VERSION 5.8 ;
BUSBITCHARS "[]" ;
DIVIDERCHAR "/" ;


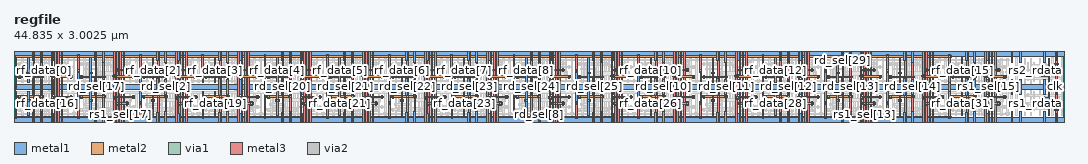
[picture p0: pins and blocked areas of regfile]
MACRO regfile
  CLASS BLOCK ;
  ORIGIN 0 0 ;
  FOREIGN regfile 0 0 ;
  SIZE 44.835 BY 3.0025 ;
  SYMMETRY X Y ;
  PIN vdd!
    DIRECTION INOUT ;
    USE POWER ;
    SHAPE ABUTMENT ;
    PORT
      LAYER metal1 ;
        RECT 0 0 44.835 0.2 ;
        RECT 44.5025 0 44.5675 0.36 ;
        RECT 43.97 0 44.035 0.45 ;
        RECT 42.95 0 43.015 0.45 ;
        RECT 42.58 0 42.645 0.45 ;
        RECT 41.5325 0 41.5975 0.3625 ;
        RECT 40.985 0 41.05 0.45 ;
        RECT 40.64 0 40.705 0.395 ;
        RECT 38.875 0 38.94 0.3625 ;
        RECT 38.3275 0 38.3925 0.45 ;
        RECT 37.9825 0 38.0475 0.395 ;
        RECT 36.2175 0 36.2825 0.3625 ;
        RECT 35.67 0 35.735 0.45 ;
        RECT 35.325 0 35.39 0.395 ;
        RECT 33.56 0 33.625 0.3625 ;
        RECT 33.0125 0 33.0775 0.45 ;
        RECT 32.6675 0 32.7325 0.395 ;
        RECT 30.9025 0 30.9675 0.3625 ;
        RECT 30.355 0 30.42 0.45 ;
        RECT 30.01 0 30.075 0.395 ;
        RECT 28.245 0 28.31 0.3625 ;
        RECT 27.6975 0 27.7625 0.45 ;
        RECT 27.3525 0 27.4175 0.395 ;
        RECT 25.5875 0 25.6525 0.3625 ;
        RECT 25.04 0 25.105 0.45 ;
        RECT 24.695 0 24.76 0.395 ;
        RECT 22.93 0 22.995 0.3625 ;
        RECT 22.3825 0 22.4475 0.45 ;
        RECT 22.0375 0 22.1025 0.395 ;
        RECT 20.2725 0 20.3375 0.3625 ;
        RECT 19.725 0 19.79 0.45 ;
        RECT 19.38 0 19.445 0.395 ;
        RECT 17.615 0 17.68 0.3625 ;
        RECT 17.0675 0 17.1325 0.45 ;
        RECT 16.7225 0 16.7875 0.395 ;
        RECT 14.9575 0 15.0225 0.3625 ;
        RECT 14.41 0 14.475 0.45 ;
        RECT 14.065 0 14.13 0.395 ;
        RECT 12.3 0 12.365 0.3625 ;
        RECT 11.7525 0 11.8175 0.45 ;
        RECT 11.4075 0 11.4725 0.395 ;
        RECT 9.6425 0 9.7075 0.3625 ;
        RECT 9.095 0 9.16 0.45 ;
        RECT 8.75 0 8.815 0.395 ;
        RECT 6.985 0 7.05 0.3625 ;
        RECT 6.4375 0 6.5025 0.45 ;
        RECT 6.0925 0 6.1575 0.395 ;
        RECT 4.3275 0 4.3925 0.3625 ;
        RECT 3.78 0 3.845 0.45 ;
        RECT 3.435 0 3.5 0.395 ;
        RECT 1.67 0 1.735 0.3625 ;
        RECT 1.1225 0 1.1875 0.45 ;
        RECT 0.7775 0 0.8425 0.395 ;
        RECT 0 2.8 44.835 3 ;
        RECT 44.5025 2.64 44.5675 3 ;
        RECT 43.97 2.55 44.035 3 ;
        RECT 42.95 2.55 43.015 3 ;
        RECT 42.58 2.55 42.645 3 ;
        RECT 41.5325 2.6375 41.5975 3 ;
        RECT 40.985 2.55 41.05 3 ;
        RECT 40.64 2.605 40.705 3 ;
        RECT 38.875 2.6375 38.94 3 ;
        RECT 38.3275 2.55 38.3925 3 ;
        RECT 37.9825 2.605 38.0475 3 ;
        RECT 36.2175 2.6375 36.2825 3 ;
        RECT 35.67 2.55 35.735 3 ;
        RECT 35.325 2.605 35.39 3 ;
        RECT 33.56 2.6375 33.625 3 ;
        RECT 33.0125 2.55 33.0775 3 ;
        RECT 32.6675 2.605 32.7325 3 ;
        RECT 30.9025 2.6375 30.9675 3 ;
        RECT 30.355 2.55 30.42 3 ;
        RECT 30.01 2.605 30.075 3 ;
        RECT 28.245 2.6375 28.31 3 ;
        RECT 27.6975 2.55 27.7625 3 ;
        RECT 27.3525 2.605 27.4175 3 ;
        RECT 25.5875 2.6375 25.6525 3 ;
        RECT 25.04 2.55 25.105 3 ;
        RECT 24.695 2.605 24.76 3 ;
        RECT 22.93 2.6375 22.995 3 ;
        RECT 22.3825 2.55 22.4475 3 ;
        RECT 22.0375 2.605 22.1025 3 ;
        RECT 20.2725 2.6375 20.3375 3 ;
        RECT 19.725 2.55 19.79 3 ;
        RECT 19.38 2.605 19.445 3 ;
        RECT 17.615 2.6375 17.68 3 ;
        RECT 17.0675 2.55 17.1325 3 ;
        RECT 16.7225 2.605 16.7875 3 ;
        RECT 14.9575 2.6375 15.0225 3 ;
        RECT 14.41 2.55 14.475 3 ;
        RECT 14.065 2.605 14.13 3 ;
        RECT 12.3 2.6375 12.365 3 ;
        RECT 11.7525 2.55 11.8175 3 ;
        RECT 11.4075 2.605 11.4725 3 ;
        RECT 9.6425 2.6375 9.7075 3 ;
        RECT 9.095 2.55 9.16 3 ;
        RECT 8.75 2.605 8.815 3 ;
        RECT 6.985 2.6375 7.05 3 ;
        RECT 6.4375 2.55 6.5025 3 ;
        RECT 6.0925 2.605 6.1575 3 ;
        RECT 4.3275 2.6375 4.3925 3 ;
        RECT 3.78 2.55 3.845 3 ;
        RECT 3.435 2.605 3.5 3 ;
        RECT 1.67 2.6375 1.735 3 ;
        RECT 1.1225 2.55 1.1875 3 ;
        RECT 0.7775 2.605 0.8425 3 ;
    END
  END vdd!
  PIN vss!
    DIRECTION INOUT ;
    USE GROUND ;
    SHAPE ABUTMENT ;
    PORT
      LAYER metal1 ;
        RECT 0 1.4 44.835 1.6 ;
        RECT 44.5025 1.1875 44.5675 1.8125 ;
        RECT 43.9725 1.185 44.0375 1.815 ;
        RECT 42.95 1.185 43.015 1.815 ;
        RECT 42.58 1.185 42.645 1.815 ;
        RECT 41.53 1.19 41.595 1.81 ;
        RECT 40.985 1.1875 41.05 1.8125 ;
        RECT 40.64 1.1425 40.705 1.8575 ;
        RECT 38.8725 1.19 38.9375 1.81 ;
        RECT 38.3275 1.1875 38.3925 1.8125 ;
        RECT 37.9825 1.1425 38.0475 1.8575 ;
        RECT 36.215 1.19 36.28 1.81 ;
        RECT 35.67 1.1875 35.735 1.8125 ;
        RECT 35.325 1.1425 35.39 1.8575 ;
        RECT 33.5575 1.19 33.6225 1.81 ;
        RECT 33.0125 1.1875 33.0775 1.8125 ;
        RECT 32.6675 1.1425 32.7325 1.8575 ;
        RECT 30.9 1.19 30.965 1.81 ;
        RECT 30.355 1.1875 30.42 1.8125 ;
        RECT 30.01 1.1425 30.075 1.8575 ;
        RECT 28.2425 1.19 28.3075 1.81 ;
        RECT 27.6975 1.1875 27.7625 1.8125 ;
        RECT 27.3525 1.1425 27.4175 1.8575 ;
        RECT 25.585 1.19 25.65 1.81 ;
        RECT 25.04 1.1875 25.105 1.8125 ;
        RECT 24.695 1.1425 24.76 1.8575 ;
        RECT 22.9275 1.19 22.9925 1.81 ;
        RECT 22.3825 1.1875 22.4475 1.8125 ;
        RECT 22.0375 1.1425 22.1025 1.8575 ;
        RECT 20.27 1.19 20.335 1.81 ;
        RECT 19.725 1.1875 19.79 1.8125 ;
        RECT 19.38 1.1425 19.445 1.8575 ;
        RECT 17.6125 1.19 17.6775 1.81 ;
        RECT 17.0675 1.1875 17.1325 1.8125 ;
        RECT 16.7225 1.1425 16.7875 1.8575 ;
        RECT 14.955 1.19 15.02 1.81 ;
        RECT 14.41 1.1875 14.475 1.8125 ;
        RECT 14.065 1.1425 14.13 1.8575 ;
        RECT 12.2975 1.19 12.3625 1.81 ;
        RECT 11.7525 1.1875 11.8175 1.8125 ;
        RECT 11.4075 1.1425 11.4725 1.8575 ;
        RECT 9.64 1.19 9.705 1.81 ;
        RECT 9.095 1.1875 9.16 1.8125 ;
        RECT 8.75 1.1425 8.815 1.8575 ;
        RECT 6.9825 1.19 7.0475 1.81 ;
        RECT 6.4375 1.1875 6.5025 1.8125 ;
        RECT 6.0925 1.1425 6.1575 1.8575 ;
        RECT 4.325 1.19 4.39 1.81 ;
        RECT 3.78 1.1875 3.845 1.8125 ;
        RECT 3.435 1.1425 3.5 1.8575 ;
        RECT 1.6675 1.19 1.7325 1.81 ;
        RECT 1.1225 1.1875 1.1875 1.8125 ;
        RECT 0.7775 1.1425 0.8425 1.8575 ;
        RECT 0.06 1.4 0.125 2.735 ;
        RECT 0.0575 2.1225 0.125 2.2575 ;
      LAYER metal2 ;
        RECT 0.055 2.1225 0.125 2.2575 ;
      LAYER via1 ;
        RECT 0.0575 2.1575 0.1225 2.2225 ;
    END
  END vss!
  PIN clk
    DIRECTION INPUT ;
    USE SIGNAL ;
    PORT
      LAYER metal1 ;
        RECT 44.445 0.49 44.58 0.555 ;
        RECT 44.445 2.445 44.58 2.51 ;
      LAYER metal3 ;
        RECT 44.4775 0 44.5475 3.0025 ;
      LAYER metal2 ;
        RECT 44.4425 0.49 44.5825 0.56 ;
        RECT 44.445 0.4875 44.58 0.56 ;
        RECT 44.4425 2.4425 44.5825 2.5125 ;
      LAYER via1 ;
        RECT 44.48 2.445 44.545 2.51 ;
        RECT 44.48 0.49 44.545 0.555 ;
      LAYER via2 ;
        RECT 44.4775 2.4425 44.5475 2.5125 ;
        RECT 44.4775 0.49 44.5475 0.56 ;
    END
  END clk
  PIN rd_mux_out
    DIRECTION INPUT ;
    USE SIGNAL ;
    PORT
      LAYER metal1 ;
        RECT 39.9225 0.265 39.9875 1.3125 ;
        RECT 39.92 0.7425 39.9875 0.8775 ;
        RECT 39.9225 1.6875 39.9875 2.735 ;
        RECT 39.92 2.1225 39.9875 2.2575 ;
        RECT 37.265 0.265 37.33 1.3125 ;
        RECT 37.2625 0.7425 37.33 0.8775 ;
        RECT 37.265 1.6875 37.33 2.735 ;
        RECT 37.2625 2.1225 37.33 2.2575 ;
        RECT 34.6075 0.265 34.6725 1.3125 ;
        RECT 34.605 0.7425 34.6725 0.8775 ;
        RECT 34.6075 1.6875 34.6725 2.735 ;
        RECT 34.605 2.1225 34.6725 2.2575 ;
        RECT 31.95 0.265 32.015 1.3125 ;
        RECT 31.9475 0.7425 32.015 0.8775 ;
        RECT 31.95 1.6875 32.015 2.735 ;
        RECT 31.9475 2.1225 32.015 2.2575 ;
        RECT 29.2925 0.265 29.3575 1.3125 ;
        RECT 29.29 0.7425 29.3575 0.8775 ;
        RECT 29.2925 1.6875 29.3575 2.735 ;
        RECT 29.29 2.1225 29.3575 2.2575 ;
        RECT 26.635 0.265 26.7 1.3125 ;
        RECT 26.6325 0.7425 26.7 0.8775 ;
        RECT 26.635 1.6875 26.7 2.735 ;
        RECT 26.6325 2.1225 26.7 2.2575 ;
        RECT 23.9775 0.265 24.0425 1.3125 ;
        RECT 23.975 0.7425 24.0425 0.8775 ;
        RECT 23.9775 1.6875 24.0425 2.735 ;
        RECT 23.975 2.1225 24.0425 2.2575 ;
        RECT 21.32 0.265 21.385 1.3125 ;
        RECT 21.3175 0.7425 21.385 0.8775 ;
        RECT 21.32 1.6875 21.385 2.735 ;
        RECT 21.3175 2.1225 21.385 2.2575 ;
        RECT 18.6625 0.265 18.7275 1.3125 ;
        RECT 18.66 0.7425 18.7275 0.8775 ;
        RECT 18.6625 1.6875 18.7275 2.735 ;
        RECT 18.66 2.1225 18.7275 2.2575 ;
        RECT 16.005 0.265 16.07 1.3125 ;
        RECT 16.0025 0.7425 16.07 0.8775 ;
        RECT 16.005 1.6875 16.07 2.735 ;
        RECT 16.0025 2.1225 16.07 2.2575 ;
        RECT 13.3475 0.265 13.4125 1.3125 ;
        RECT 13.345 0.7425 13.4125 0.8775 ;
        RECT 13.3475 1.6875 13.4125 2.735 ;
        RECT 13.345 2.1225 13.4125 2.2575 ;
        RECT 10.69 0.265 10.755 1.3125 ;
        RECT 10.6875 0.7425 10.755 0.8775 ;
        RECT 10.69 1.6875 10.755 2.735 ;
        RECT 10.6875 2.1225 10.755 2.2575 ;
        RECT 8.0325 0.265 8.0975 1.3125 ;
        RECT 8.03 0.7425 8.0975 0.8775 ;
        RECT 8.0325 1.6875 8.0975 2.735 ;
        RECT 8.03 2.1225 8.0975 2.2575 ;
        RECT 5.375 0.265 5.44 1.3125 ;
        RECT 5.3725 0.7425 5.44 0.8775 ;
        RECT 5.375 1.6875 5.44 2.735 ;
        RECT 5.3725 2.1225 5.44 2.2575 ;
        RECT 2.7175 0.265 2.7825 1.3125 ;
        RECT 2.715 0.7425 2.7825 0.8775 ;
        RECT 2.7175 1.6875 2.7825 2.735 ;
        RECT 2.715 2.1225 2.7825 2.2575 ;
        RECT 0.06 0.265 0.125 1.3125 ;
        RECT 0.0575 0.7425 0.125 0.8775 ;
      LAYER metal3 ;
        RECT 39.92 0.1375 39.99 0.8775 ;
        RECT 39.9175 0.7375 39.9875 2.8625 ;
        RECT 37.26 0.7375 37.3325 0.8775 ;
        RECT 37.2625 0.1375 37.3325 0.8775 ;
        RECT 37.26 2.1225 37.33 2.8625 ;
        RECT 34.6025 0.7375 34.675 0.8775 ;
        RECT 34.605 0.1375 34.675 0.8775 ;
        RECT 34.6025 2.1225 34.6725 2.8625 ;
        RECT 31.945 0.7375 32.0175 0.8775 ;
        RECT 31.9475 0.1375 32.0175 0.8775 ;
        RECT 31.945 2.1225 32.015 2.8625 ;
        RECT 29.2875 0.7375 29.36 0.8775 ;
        RECT 29.29 0.1375 29.36 0.8775 ;
        RECT 29.2875 2.1225 29.3575 2.8625 ;
        RECT 26.63 0.7375 26.7025 0.8775 ;
        RECT 26.6325 0.1375 26.7025 0.8775 ;
        RECT 26.63 2.1225 26.7 2.8625 ;
        RECT 23.9725 0.7375 24.045 0.8775 ;
        RECT 23.975 0.1375 24.045 0.8775 ;
        RECT 23.9725 2.1225 24.0425 2.8625 ;
        RECT 21.315 0.7375 21.3875 0.8775 ;
        RECT 21.3175 0.1375 21.3875 0.8775 ;
        RECT 21.315 2.1225 21.385 2.8625 ;
        RECT 18.6575 0.7375 18.73 0.8775 ;
        RECT 18.66 0.1375 18.73 0.8775 ;
        RECT 18.6575 2.1225 18.7275 2.8625 ;
        RECT 16 0.7375 16.0725 0.8775 ;
        RECT 16.0025 0.1375 16.0725 0.8775 ;
        RECT 16 2.1225 16.07 2.8625 ;
        RECT 13.3425 0.7375 13.415 0.8775 ;
        RECT 13.345 0.1375 13.415 0.8775 ;
        RECT 13.3425 2.1225 13.4125 2.8625 ;
        RECT 10.685 0.7375 10.7575 0.8775 ;
        RECT 10.6875 0.1375 10.7575 0.8775 ;
        RECT 10.685 2.1225 10.755 2.8625 ;
        RECT 8.0275 0.7375 8.1 0.8775 ;
        RECT 8.03 0.1375 8.1 0.8775 ;
        RECT 8.0275 2.1225 8.0975 2.8625 ;
        RECT 5.37 0.7375 5.4425 0.8775 ;
        RECT 5.3725 0.1375 5.4425 0.8775 ;
        RECT 5.37 2.1225 5.44 2.8625 ;
        RECT 2.7125 0.7375 2.785 0.8775 ;
        RECT 2.715 0.1375 2.785 0.8775 ;
        RECT 2.7125 2.1225 2.7825 2.8625 ;
        RECT 0.055 0.7375 0.1275 0.8775 ;
        RECT 0.0575 0.1375 0.1275 0.8775 ;
      LAYER metal2 ;
        RECT 0.0225 0.1725 40.025 0.2425 ;
        RECT 0.0725 2.7575 40.0225 2.8275 ;
        RECT 39.9175 0.7375 39.9875 0.8775 ;
        RECT 39.9175 2.1225 39.9875 2.2625 ;
        RECT 37.26 0.7375 37.33 0.8775 ;
        RECT 37.26 2.1225 37.33 2.2625 ;
        RECT 34.6025 0.7375 34.6725 0.8775 ;
        RECT 34.6025 2.1225 34.6725 2.2625 ;
        RECT 31.945 0.7375 32.015 0.8775 ;
        RECT 31.945 2.1225 32.015 2.2625 ;
        RECT 29.2875 0.7375 29.3575 0.8775 ;
        RECT 29.2875 2.1225 29.3575 2.2625 ;
        RECT 26.63 0.7375 26.7 0.8775 ;
        RECT 26.63 2.1225 26.7 2.2625 ;
        RECT 23.9725 0.7375 24.0425 0.8775 ;
        RECT 23.9725 2.1225 24.0425 2.2625 ;
        RECT 21.315 0.7375 21.385 0.8775 ;
        RECT 21.315 2.1225 21.385 2.2625 ;
        RECT 18.6575 0.7375 18.7275 0.8775 ;
        RECT 18.6575 2.1225 18.7275 2.2625 ;
        RECT 16 0.7375 16.07 0.8775 ;
        RECT 16 2.1225 16.07 2.2625 ;
        RECT 13.3425 0.7375 13.4125 0.8775 ;
        RECT 13.3425 2.1225 13.4125 2.2625 ;
        RECT 10.685 0.7375 10.755 0.8775 ;
        RECT 10.685 2.1225 10.755 2.2625 ;
        RECT 8.0275 0.7375 8.0975 0.8775 ;
        RECT 8.0275 2.1225 8.0975 2.2625 ;
        RECT 5.37 0.7375 5.44 0.8775 ;
        RECT 5.37 2.1225 5.44 2.2625 ;
        RECT 2.7125 0.7375 2.7825 0.8775 ;
        RECT 2.7125 2.1225 2.7825 2.2625 ;
        RECT 0.055 0.7375 0.125 0.8775 ;
      LAYER via1 ;
        RECT 0.0575 0.7775 0.1225 0.8425 ;
        RECT 2.715 2.1575 2.78 2.2225 ;
        RECT 2.715 0.7775 2.78 0.8425 ;
        RECT 5.3725 2.1575 5.4375 2.2225 ;
        RECT 5.3725 0.7775 5.4375 0.8425 ;
        RECT 8.03 2.1575 8.095 2.2225 ;
        RECT 8.03 0.7775 8.095 0.8425 ;
        RECT 10.6875 2.1575 10.7525 2.2225 ;
        RECT 10.6875 0.7775 10.7525 0.8425 ;
        RECT 13.345 2.1575 13.41 2.2225 ;
        RECT 13.345 0.7775 13.41 0.8425 ;
        RECT 16.0025 2.1575 16.0675 2.2225 ;
        RECT 16.0025 0.7775 16.0675 0.8425 ;
        RECT 18.66 2.1575 18.725 2.2225 ;
        RECT 18.66 0.7775 18.725 0.8425 ;
        RECT 21.3175 2.1575 21.3825 2.2225 ;
        RECT 21.3175 0.7775 21.3825 0.8425 ;
        RECT 23.975 2.1575 24.04 2.2225 ;
        RECT 23.975 0.7775 24.04 0.8425 ;
        RECT 26.6325 2.1575 26.6975 2.2225 ;
        RECT 26.6325 0.7775 26.6975 0.8425 ;
        RECT 29.29 2.1575 29.355 2.2225 ;
        RECT 29.29 0.7775 29.355 0.8425 ;
        RECT 31.9475 2.1575 32.0125 2.2225 ;
        RECT 31.9475 0.7775 32.0125 0.8425 ;
        RECT 34.605 2.1575 34.67 2.2225 ;
        RECT 34.605 0.7775 34.67 0.8425 ;
        RECT 37.2625 2.1575 37.3275 2.2225 ;
        RECT 37.2625 0.7775 37.3275 0.8425 ;
        RECT 39.92 2.1575 39.985 2.2225 ;
        RECT 39.92 0.7775 39.985 0.8425 ;
      LAYER via2 ;
        RECT 0.055 0.7725 0.125 0.8425 ;
        RECT 0.0575 0.1725 0.1275 0.2425 ;
        RECT 2.7125 2.7575 2.7825 2.8275 ;
        RECT 2.7125 2.1575 2.7825 2.2275 ;
        RECT 2.7125 0.7725 2.7825 0.8425 ;
        RECT 2.715 0.1725 2.785 0.2425 ;
        RECT 5.37 2.7575 5.44 2.8275 ;
        RECT 5.37 2.1575 5.44 2.2275 ;
        RECT 5.37 0.7725 5.44 0.8425 ;
        RECT 5.3725 0.1725 5.4425 0.2425 ;
        RECT 8.0275 2.7575 8.0975 2.8275 ;
        RECT 8.0275 2.1575 8.0975 2.2275 ;
        RECT 8.0275 0.7725 8.0975 0.8425 ;
        RECT 8.03 0.1725 8.1 0.2425 ;
        RECT 10.685 2.7575 10.755 2.8275 ;
        RECT 10.685 2.1575 10.755 2.2275 ;
        RECT 10.685 0.7725 10.755 0.8425 ;
        RECT 10.6875 0.1725 10.7575 0.2425 ;
        RECT 13.3425 2.7575 13.4125 2.8275 ;
        RECT 13.3425 2.1575 13.4125 2.2275 ;
        RECT 13.3425 0.7725 13.4125 0.8425 ;
        RECT 13.345 0.1725 13.415 0.2425 ;
        RECT 16 2.7575 16.07 2.8275 ;
        RECT 16 2.1575 16.07 2.2275 ;
        RECT 16 0.7725 16.07 0.8425 ;
        RECT 16.0025 0.1725 16.0725 0.2425 ;
        RECT 18.6575 2.7575 18.7275 2.8275 ;
        RECT 18.6575 2.1575 18.7275 2.2275 ;
        RECT 18.6575 0.7725 18.7275 0.8425 ;
        RECT 18.66 0.1725 18.73 0.2425 ;
        RECT 21.315 2.7575 21.385 2.8275 ;
        RECT 21.315 2.1575 21.385 2.2275 ;
        RECT 21.315 0.7725 21.385 0.8425 ;
        RECT 21.3175 0.1725 21.3875 0.2425 ;
        RECT 23.9725 2.7575 24.0425 2.8275 ;
        RECT 23.9725 2.1575 24.0425 2.2275 ;
        RECT 23.9725 0.7725 24.0425 0.8425 ;
        RECT 23.975 0.1725 24.045 0.2425 ;
        RECT 26.63 2.7575 26.7 2.8275 ;
        RECT 26.63 2.1575 26.7 2.2275 ;
        RECT 26.63 0.7725 26.7 0.8425 ;
        RECT 26.6325 0.1725 26.7025 0.2425 ;
        RECT 29.2875 2.7575 29.3575 2.8275 ;
        RECT 29.2875 2.1575 29.3575 2.2275 ;
        RECT 29.2875 0.7725 29.3575 0.8425 ;
        RECT 29.29 0.1725 29.36 0.2425 ;
        RECT 31.945 2.7575 32.015 2.8275 ;
        RECT 31.945 2.1575 32.015 2.2275 ;
        RECT 31.945 0.7725 32.015 0.8425 ;
        RECT 31.9475 0.1725 32.0175 0.2425 ;
        RECT 34.6025 2.7575 34.6725 2.8275 ;
        RECT 34.6025 2.1575 34.6725 2.2275 ;
        RECT 34.6025 0.7725 34.6725 0.8425 ;
        RECT 34.605 0.1725 34.675 0.2425 ;
        RECT 37.26 2.7575 37.33 2.8275 ;
        RECT 37.26 2.1575 37.33 2.2275 ;
        RECT 37.26 0.7725 37.33 0.8425 ;
        RECT 37.2625 0.1725 37.3325 0.2425 ;
        RECT 39.9175 2.7575 39.9875 2.8275 ;
        RECT 39.9175 2.1575 39.9875 2.2275 ;
        RECT 39.9175 0.7725 39.9875 0.8425 ;
        RECT 39.92 0.1725 39.99 0.2425 ;
    END
  END rd_mux_out
  PIN rd_sel[0]
    DIRECTION INPUT ;
    USE SIGNAL ;
    PORT
      LAYER metal1 ;
        RECT 1.105 1.885 1.24 1.95 ;
        RECT 0.1975 1.85 0.2625 1.985 ;
      LAYER metal3 ;
        RECT 1.135 0 1.205 3.0025 ;
      LAYER metal2 ;
        RECT 1.1 1.8825 1.24 1.955 ;
        RECT 0.1625 1.8825 1.24 1.9525 ;
      LAYER via1 ;
        RECT 0.1975 1.885 0.2625 1.95 ;
        RECT 1.14 1.885 1.205 1.95 ;
      LAYER via2 ;
        RECT 1.135 1.885 1.205 1.955 ;
    END
  END rd_sel[0]
  PIN rd_sel[10]
    DIRECTION INPUT ;
    USE SIGNAL ;
    PORT
      LAYER metal1 ;
        RECT 27.68 1.885 27.815 1.95 ;
        RECT 26.7725 1.85 26.8375 1.985 ;
      LAYER metal3 ;
        RECT 27.71 0 27.78 3.0025 ;
      LAYER metal2 ;
        RECT 27.675 1.8825 27.815 1.955 ;
        RECT 26.7375 1.8825 27.815 1.9525 ;
      LAYER via1 ;
        RECT 26.7725 1.885 26.8375 1.95 ;
        RECT 27.715 1.885 27.78 1.95 ;
      LAYER via2 ;
        RECT 27.71 1.885 27.78 1.955 ;
    END
  END rd_sel[10]
  PIN rd_sel[11]
    DIRECTION INPUT ;
    USE SIGNAL ;
    PORT
      LAYER metal1 ;
        RECT 30.3375 1.885 30.4725 1.95 ;
        RECT 29.43 1.85 29.495 1.985 ;
      LAYER metal3 ;
        RECT 30.3675 0 30.4375 3.0025 ;
      LAYER metal2 ;
        RECT 30.3325 1.8825 30.4725 1.955 ;
        RECT 29.395 1.8825 30.4725 1.9525 ;
      LAYER via1 ;
        RECT 29.43 1.885 29.495 1.95 ;
        RECT 30.3725 1.885 30.4375 1.95 ;
      LAYER via2 ;
        RECT 30.3675 1.885 30.4375 1.955 ;
    END
  END rd_sel[11]
  PIN rd_sel[12]
    DIRECTION INPUT ;
    USE SIGNAL ;
    PORT
      LAYER metal1 ;
        RECT 32.995 1.885 33.13 1.95 ;
        RECT 32.0875 1.85 32.1525 1.985 ;
      LAYER metal3 ;
        RECT 33.025 0 33.095 3.0025 ;
      LAYER metal2 ;
        RECT 32.99 1.8825 33.13 1.955 ;
        RECT 32.0525 1.8825 33.13 1.9525 ;
      LAYER via1 ;
        RECT 32.0875 1.885 32.1525 1.95 ;
        RECT 33.03 1.885 33.095 1.95 ;
      LAYER via2 ;
        RECT 33.025 1.885 33.095 1.955 ;
    END
  END rd_sel[12]
  PIN rd_sel[13]
    DIRECTION INPUT ;
    USE SIGNAL ;
    PORT
      LAYER metal1 ;
        RECT 35.6525 1.885 35.7875 1.95 ;
        RECT 34.745 1.85 34.81 1.985 ;
      LAYER metal3 ;
        RECT 35.6825 0 35.7525 3.0025 ;
      LAYER metal2 ;
        RECT 35.6475 1.8825 35.7875 1.955 ;
        RECT 34.71 1.8825 35.7875 1.9525 ;
      LAYER via1 ;
        RECT 34.745 1.885 34.81 1.95 ;
        RECT 35.6875 1.885 35.7525 1.95 ;
      LAYER via2 ;
        RECT 35.6825 1.885 35.7525 1.955 ;
    END
  END rd_sel[13]
  PIN rd_sel[14]
    DIRECTION INPUT ;
    USE SIGNAL ;
    PORT
      LAYER metal1 ;
        RECT 38.31 1.885 38.445 1.95 ;
        RECT 37.4025 1.85 37.4675 1.985 ;
      LAYER metal3 ;
        RECT 38.34 0 38.41 3.0025 ;
      LAYER metal2 ;
        RECT 38.305 1.8825 38.445 1.955 ;
        RECT 37.3675 1.8825 38.445 1.9525 ;
      LAYER via1 ;
        RECT 37.4025 1.885 37.4675 1.95 ;
        RECT 38.345 1.885 38.41 1.95 ;
      LAYER via2 ;
        RECT 38.34 1.885 38.41 1.955 ;
    END
  END rd_sel[14]
  PIN rd_sel[15]
    DIRECTION INPUT ;
    USE SIGNAL ;
    PORT
      LAYER metal1 ;
        RECT 40.9675 1.885 41.1025 1.95 ;
        RECT 40.06 1.85 40.125 1.985 ;
      LAYER metal3 ;
        RECT 40.9975 0 41.0675 3.0025 ;
      LAYER metal2 ;
        RECT 40.9625 1.8825 41.1025 1.955 ;
        RECT 40.025 1.8825 41.1025 1.9525 ;
      LAYER via1 ;
        RECT 40.06 1.885 40.125 1.95 ;
        RECT 41.0025 1.885 41.0675 1.95 ;
      LAYER via2 ;
        RECT 40.9975 1.885 41.0675 1.955 ;
    END
  END rd_sel[15]
  PIN rd_sel[16]
    DIRECTION INPUT ;
    USE SIGNAL ;
    PORT
      LAYER metal1 ;
        RECT 1.105 1.05 1.24 1.115 ;
        RECT 0.1975 1.015 0.2625 1.15 ;
      LAYER metal3 ;
        RECT 0.815 0 0.885 3.0025 ;
      LAYER metal2 ;
        RECT 0.1625 1.0475 1.24 1.1175 ;
      LAYER via1 ;
        RECT 0.1975 1.05 0.2625 1.115 ;
        RECT 1.14 1.05 1.205 1.115 ;
      LAYER via2 ;
        RECT 0.815 1.0475 0.885 1.1175 ;
    END
  END rd_sel[16]
  PIN rd_sel[17]
    DIRECTION INPUT ;
    USE SIGNAL ;
    PORT
      LAYER metal1 ;
        RECT 3.7625 1.05 3.8975 1.115 ;
        RECT 2.855 1.015 2.92 1.15 ;
      LAYER metal3 ;
        RECT 3.4725 0 3.5425 3.0025 ;
      LAYER metal2 ;
        RECT 2.82 1.0475 3.8975 1.1175 ;
      LAYER via1 ;
        RECT 2.855 1.05 2.92 1.115 ;
        RECT 3.7975 1.05 3.8625 1.115 ;
      LAYER via2 ;
        RECT 3.4725 1.0475 3.5425 1.1175 ;
    END
  END rd_sel[17]
  PIN rd_sel[18]
    DIRECTION INPUT ;
    USE SIGNAL ;
    PORT
      LAYER metal1 ;
        RECT 6.42 1.05 6.555 1.115 ;
        RECT 5.5125 1.015 5.5775 1.15 ;
      LAYER metal3 ;
        RECT 6.13 0 6.2 3.0025 ;
      LAYER metal2 ;
        RECT 5.4775 1.0475 6.555 1.1175 ;
      LAYER via1 ;
        RECT 5.5125 1.05 5.5775 1.115 ;
        RECT 6.455 1.05 6.52 1.115 ;
      LAYER via2 ;
        RECT 6.13 1.0475 6.2 1.1175 ;
    END
  END rd_sel[18]
  PIN rd_sel[19]
    DIRECTION INPUT ;
    USE SIGNAL ;
    PORT
      LAYER metal1 ;
        RECT 9.0775 1.05 9.2125 1.115 ;
        RECT 8.17 1.015 8.235 1.15 ;
      LAYER metal3 ;
        RECT 8.7875 0 8.8575 3.0025 ;
      LAYER metal2 ;
        RECT 8.135 1.0475 9.2125 1.1175 ;
      LAYER via1 ;
        RECT 8.17 1.05 8.235 1.115 ;
        RECT 9.1125 1.05 9.1775 1.115 ;
      LAYER via2 ;
        RECT 8.7875 1.0475 8.8575 1.1175 ;
    END
  END rd_sel[19]
  PIN rd_sel[1]
    DIRECTION INPUT ;
    USE SIGNAL ;
    PORT
      LAYER metal1 ;
        RECT 3.7625 1.885 3.8975 1.95 ;
        RECT 2.855 1.85 2.92 1.985 ;
      LAYER metal3 ;
        RECT 3.7925 0 3.8625 3.0025 ;
      LAYER metal2 ;
        RECT 3.7575 1.8825 3.8975 1.955 ;
        RECT 2.82 1.8825 3.8975 1.9525 ;
      LAYER via1 ;
        RECT 2.855 1.885 2.92 1.95 ;
        RECT 3.7975 1.885 3.8625 1.95 ;
      LAYER via2 ;
        RECT 3.7925 1.885 3.8625 1.955 ;
    END
  END rd_sel[1]
  PIN rd_sel[20]
    DIRECTION INPUT ;
    USE SIGNAL ;
    PORT
      LAYER metal1 ;
        RECT 11.735 1.05 11.87 1.115 ;
        RECT 10.8275 1.015 10.8925 1.15 ;
      LAYER metal3 ;
        RECT 11.445 0 11.515 3.0025 ;
      LAYER metal2 ;
        RECT 10.7925 1.0475 11.87 1.1175 ;
      LAYER via1 ;
        RECT 10.8275 1.05 10.8925 1.115 ;
        RECT 11.77 1.05 11.835 1.115 ;
      LAYER via2 ;
        RECT 11.445 1.0475 11.515 1.1175 ;
    END
  END rd_sel[20]
  PIN rd_sel[21]
    DIRECTION INPUT ;
    USE SIGNAL ;
    PORT
      LAYER metal1 ;
        RECT 14.3925 1.05 14.5275 1.115 ;
        RECT 13.485 1.015 13.55 1.15 ;
      LAYER metal3 ;
        RECT 14.1025 0 14.1725 3.0025 ;
      LAYER metal2 ;
        RECT 13.45 1.0475 14.5275 1.1175 ;
      LAYER via1 ;
        RECT 13.485 1.05 13.55 1.115 ;
        RECT 14.4275 1.05 14.4925 1.115 ;
      LAYER via2 ;
        RECT 14.1025 1.0475 14.1725 1.1175 ;
    END
  END rd_sel[21]
  PIN rd_sel[22]
    DIRECTION INPUT ;
    USE SIGNAL ;
    PORT
      LAYER metal1 ;
        RECT 17.05 1.05 17.185 1.115 ;
        RECT 16.1425 1.015 16.2075 1.15 ;
      LAYER metal3 ;
        RECT 16.76 0 16.83 3.0025 ;
      LAYER metal2 ;
        RECT 16.1075 1.0475 17.185 1.1175 ;
      LAYER via1 ;
        RECT 16.1425 1.05 16.2075 1.115 ;
        RECT 17.085 1.05 17.15 1.115 ;
      LAYER via2 ;
        RECT 16.76 1.0475 16.83 1.1175 ;
    END
  END rd_sel[22]
  PIN rd_sel[23]
    DIRECTION INPUT ;
    USE SIGNAL ;
    PORT
      LAYER metal1 ;
        RECT 19.7075 1.05 19.8425 1.115 ;
        RECT 18.8 1.015 18.865 1.15 ;
      LAYER metal3 ;
        RECT 19.4175 0 19.4875 3.0025 ;
      LAYER metal2 ;
        RECT 18.765 1.0475 19.8425 1.1175 ;
      LAYER via1 ;
        RECT 18.8 1.05 18.865 1.115 ;
        RECT 19.7425 1.05 19.8075 1.115 ;
      LAYER via2 ;
        RECT 19.4175 1.0475 19.4875 1.1175 ;
    END
  END rd_sel[23]
  PIN rd_sel[24]
    DIRECTION INPUT ;
    USE SIGNAL ;
    PORT
      LAYER metal1 ;
        RECT 22.365 1.05 22.5 1.115 ;
        RECT 21.4575 1.015 21.5225 1.15 ;
      LAYER metal3 ;
        RECT 22.075 0 22.145 3.0025 ;
      LAYER metal2 ;
        RECT 21.4225 1.0475 22.5 1.1175 ;
      LAYER via1 ;
        RECT 21.4575 1.05 21.5225 1.115 ;
        RECT 22.4 1.05 22.465 1.115 ;
      LAYER via2 ;
        RECT 22.075 1.0475 22.145 1.1175 ;
    END
  END rd_sel[24]
  PIN rd_sel[25]
    DIRECTION INPUT ;
    USE SIGNAL ;
    PORT
      LAYER metal1 ;
        RECT 25.0225 1.05 25.1575 1.115 ;
        RECT 24.115 1.015 24.18 1.15 ;
      LAYER metal3 ;
        RECT 24.7325 0 24.8025 3.0025 ;
      LAYER metal2 ;
        RECT 24.08 1.0475 25.1575 1.1175 ;
      LAYER via1 ;
        RECT 24.115 1.05 24.18 1.115 ;
        RECT 25.0575 1.05 25.1225 1.115 ;
      LAYER via2 ;
        RECT 24.7325 1.0475 24.8025 1.1175 ;
    END
  END rd_sel[25]
  PIN rd_sel[26]
    DIRECTION INPUT ;
    USE SIGNAL ;
    PORT
      LAYER metal1 ;
        RECT 27.68 1.05 27.815 1.115 ;
        RECT 26.7725 1.015 26.8375 1.15 ;
      LAYER metal3 ;
        RECT 27.39 0 27.46 3.0025 ;
      LAYER metal2 ;
        RECT 26.7375 1.0475 27.815 1.1175 ;
      LAYER via1 ;
        RECT 26.7725 1.05 26.8375 1.115 ;
        RECT 27.715 1.05 27.78 1.115 ;
      LAYER via2 ;
        RECT 27.39 1.0475 27.46 1.1175 ;
    END
  END rd_sel[26]
  PIN rd_sel[27]
    DIRECTION INPUT ;
    USE SIGNAL ;
    PORT
      LAYER metal1 ;
        RECT 30.3375 1.05 30.4725 1.115 ;
        RECT 29.43 1.015 29.495 1.15 ;
      LAYER metal3 ;
        RECT 30.0475 0 30.1175 3.0025 ;
      LAYER metal2 ;
        RECT 29.395 1.0475 30.4725 1.1175 ;
      LAYER via1 ;
        RECT 29.43 1.05 29.495 1.115 ;
        RECT 30.3725 1.05 30.4375 1.115 ;
      LAYER via2 ;
        RECT 30.0475 1.0475 30.1175 1.1175 ;
    END
  END rd_sel[27]
  PIN rd_sel[28]
    DIRECTION INPUT ;
    USE SIGNAL ;
    PORT
      LAYER metal1 ;
        RECT 32.995 1.05 33.13 1.115 ;
        RECT 32.0875 1.015 32.1525 1.15 ;
      LAYER metal3 ;
        RECT 32.705 0 32.775 3.0025 ;
      LAYER metal2 ;
        RECT 32.0525 1.0475 33.13 1.1175 ;
      LAYER via1 ;
        RECT 32.0875 1.05 32.1525 1.115 ;
        RECT 33.03 1.05 33.095 1.115 ;
      LAYER via2 ;
        RECT 32.705 1.0475 32.775 1.1175 ;
    END
  END rd_sel[28]
  PIN rd_sel[29]
    DIRECTION INPUT ;
    USE SIGNAL ;
    PORT
      LAYER metal1 ;
        RECT 35.6525 1.05 35.7875 1.115 ;
        RECT 34.745 1.015 34.81 1.15 ;
      LAYER metal3 ;
        RECT 35.3625 0 35.4325 3.0025 ;
      LAYER metal2 ;
        RECT 34.71 1.0475 35.7875 1.1175 ;
      LAYER via1 ;
        RECT 34.745 1.05 34.81 1.115 ;
        RECT 35.6875 1.05 35.7525 1.115 ;
      LAYER via2 ;
        RECT 35.3625 1.0475 35.4325 1.1175 ;
    END
  END rd_sel[29]
  PIN rd_sel[2]
    DIRECTION INPUT ;
    USE SIGNAL ;
    PORT
      LAYER metal1 ;
        RECT 6.42 1.885 6.555 1.95 ;
        RECT 5.5125 1.85 5.5775 1.985 ;
      LAYER metal3 ;
        RECT 6.45 0 6.52 3.0025 ;
      LAYER metal2 ;
        RECT 6.415 1.8825 6.555 1.955 ;
        RECT 5.4775 1.8825 6.555 1.9525 ;
      LAYER via1 ;
        RECT 5.5125 1.885 5.5775 1.95 ;
        RECT 6.455 1.885 6.52 1.95 ;
      LAYER via2 ;
        RECT 6.45 1.885 6.52 1.955 ;
    END
  END rd_sel[2]
  PIN rd_sel[30]
    DIRECTION INPUT ;
    USE SIGNAL ;
    PORT
      LAYER metal1 ;
        RECT 38.31 1.05 38.445 1.115 ;
        RECT 37.4025 1.015 37.4675 1.15 ;
      LAYER metal3 ;
        RECT 38.02 0 38.09 3.0025 ;
      LAYER metal2 ;
        RECT 37.3675 1.0475 38.445 1.1175 ;
      LAYER via1 ;
        RECT 37.4025 1.05 37.4675 1.115 ;
        RECT 38.345 1.05 38.41 1.115 ;
      LAYER via2 ;
        RECT 38.02 1.0475 38.09 1.1175 ;
    END
  END rd_sel[30]
  PIN rd_sel[31]
    DIRECTION INPUT ;
    USE SIGNAL ;
    PORT
      LAYER metal1 ;
        RECT 40.9675 1.05 41.1025 1.115 ;
        RECT 40.06 1.015 40.125 1.15 ;
      LAYER metal3 ;
        RECT 40.6775 0 40.7475 3.0025 ;
      LAYER metal2 ;
        RECT 40.025 1.0475 41.1025 1.1175 ;
      LAYER via1 ;
        RECT 40.06 1.05 40.125 1.115 ;
        RECT 41.0025 1.05 41.0675 1.115 ;
      LAYER via2 ;
        RECT 40.6775 1.0475 40.7475 1.1175 ;
    END
  END rd_sel[31]
  PIN rd_sel[3]
    DIRECTION INPUT ;
    USE SIGNAL ;
    PORT
      LAYER metal1 ;
        RECT 9.0775 1.885 9.2125 1.95 ;
        RECT 8.17 1.85 8.235 1.985 ;
      LAYER metal3 ;
        RECT 9.1075 0 9.1775 3.0025 ;
      LAYER metal2 ;
        RECT 9.0725 1.8825 9.2125 1.955 ;
        RECT 8.135 1.8825 9.2125 1.9525 ;
      LAYER via1 ;
        RECT 8.17 1.885 8.235 1.95 ;
        RECT 9.1125 1.885 9.1775 1.95 ;
      LAYER via2 ;
        RECT 9.1075 1.885 9.1775 1.955 ;
    END
  END rd_sel[3]
  PIN rd_sel[4]
    DIRECTION INPUT ;
    USE SIGNAL ;
    PORT
      LAYER metal1 ;
        RECT 11.735 1.885 11.87 1.95 ;
        RECT 10.8275 1.85 10.8925 1.985 ;
      LAYER metal3 ;
        RECT 11.765 0 11.835 3.0025 ;
      LAYER metal2 ;
        RECT 11.73 1.8825 11.87 1.955 ;
        RECT 10.7925 1.8825 11.87 1.9525 ;
      LAYER via1 ;
        RECT 10.8275 1.885 10.8925 1.95 ;
        RECT 11.77 1.885 11.835 1.95 ;
      LAYER via2 ;
        RECT 11.765 1.885 11.835 1.955 ;
    END
  END rd_sel[4]
  PIN rd_sel[5]
    DIRECTION INPUT ;
    USE SIGNAL ;
    PORT
      LAYER metal1 ;
        RECT 14.3925 1.885 14.5275 1.95 ;
        RECT 13.485 1.85 13.55 1.985 ;
      LAYER metal3 ;
        RECT 14.4225 0 14.4925 3.0025 ;
      LAYER metal2 ;
        RECT 14.3875 1.8825 14.5275 1.955 ;
        RECT 13.45 1.8825 14.5275 1.9525 ;
      LAYER via1 ;
        RECT 13.485 1.885 13.55 1.95 ;
        RECT 14.4275 1.885 14.4925 1.95 ;
      LAYER via2 ;
        RECT 14.4225 1.885 14.4925 1.955 ;
    END
  END rd_sel[5]
  PIN rd_sel[6]
    DIRECTION INPUT ;
    USE SIGNAL ;
    PORT
      LAYER metal1 ;
        RECT 17.05 1.885 17.185 1.95 ;
        RECT 16.1425 1.85 16.2075 1.985 ;
      LAYER metal3 ;
        RECT 17.08 0 17.15 3.0025 ;
      LAYER metal2 ;
        RECT 17.045 1.8825 17.185 1.955 ;
        RECT 16.1075 1.8825 17.185 1.9525 ;
      LAYER via1 ;
        RECT 16.1425 1.885 16.2075 1.95 ;
        RECT 17.085 1.885 17.15 1.95 ;
      LAYER via2 ;
        RECT 17.08 1.885 17.15 1.955 ;
    END
  END rd_sel[6]
  PIN rd_sel[7]
    DIRECTION INPUT ;
    USE SIGNAL ;
    PORT
      LAYER metal1 ;
        RECT 19.7075 1.885 19.8425 1.95 ;
        RECT 18.8 1.85 18.865 1.985 ;
      LAYER metal3 ;
        RECT 19.7375 0 19.8075 3.0025 ;
      LAYER metal2 ;
        RECT 19.7025 1.8825 19.8425 1.955 ;
        RECT 18.765 1.8825 19.8425 1.9525 ;
      LAYER via1 ;
        RECT 18.8 1.885 18.865 1.95 ;
        RECT 19.7425 1.885 19.8075 1.95 ;
      LAYER via2 ;
        RECT 19.7375 1.885 19.8075 1.955 ;
    END
  END rd_sel[7]
  PIN rd_sel[8]
    DIRECTION INPUT ;
    USE SIGNAL ;
    PORT
      LAYER metal1 ;
        RECT 22.365 1.885 22.5 1.95 ;
        RECT 21.4575 1.85 21.5225 1.985 ;
      LAYER metal3 ;
        RECT 22.395 0 22.465 3.0025 ;
      LAYER metal2 ;
        RECT 22.36 1.8825 22.5 1.955 ;
        RECT 21.4225 1.8825 22.5 1.9525 ;
      LAYER via1 ;
        RECT 21.4575 1.885 21.5225 1.95 ;
        RECT 22.4 1.885 22.465 1.95 ;
      LAYER via2 ;
        RECT 22.395 1.885 22.465 1.955 ;
    END
  END rd_sel[8]
  PIN rd_sel[9]
    DIRECTION INPUT ;
    USE SIGNAL ;
    PORT
      LAYER metal1 ;
        RECT 25.0225 1.885 25.1575 1.95 ;
        RECT 24.115 1.85 24.18 1.985 ;
      LAYER metal3 ;
        RECT 25.0525 0 25.1225 3.0025 ;
      LAYER metal2 ;
        RECT 25.0175 1.8825 25.1575 1.955 ;
        RECT 24.08 1.8825 25.1575 1.9525 ;
      LAYER via1 ;
        RECT 24.115 1.885 24.18 1.95 ;
        RECT 25.0575 1.885 25.1225 1.95 ;
      LAYER via2 ;
        RECT 25.0525 1.885 25.1225 1.955 ;
    END
  END rd_sel[9]
  PIN rf_data[0]
    DIRECTION OUTPUT ;
    USE SIGNAL ;
    PORT
      LAYER metal1 ;
        RECT 0.5875 1.6875 0.6525 2.735 ;
      LAYER metal2 ;
        RECT 0.5525 2.055 0.6875 2.125 ;
      LAYER via1 ;
        RECT 0.5875 2.0575 0.6525 2.1225 ;
    END
  END rf_data[0]
  PIN rf_data[10]
    DIRECTION OUTPUT ;
    USE SIGNAL ;
    PORT
      LAYER metal1 ;
        RECT 27.1625 1.6875 27.2275 2.735 ;
      LAYER metal2 ;
        RECT 27.1275 2.055 27.2625 2.125 ;
      LAYER via1 ;
        RECT 27.1625 2.0575 27.2275 2.1225 ;
    END
  END rf_data[10]
  PIN rf_data[11]
    DIRECTION OUTPUT ;
    USE SIGNAL ;
    PORT
      LAYER metal1 ;
        RECT 29.82 1.6875 29.885 2.735 ;
      LAYER metal2 ;
        RECT 29.785 2.055 29.92 2.125 ;
      LAYER via1 ;
        RECT 29.82 2.0575 29.885 2.1225 ;
    END
  END rf_data[11]
  PIN rf_data[12]
    DIRECTION OUTPUT ;
    USE SIGNAL ;
    PORT
      LAYER metal1 ;
        RECT 32.4775 1.6875 32.5425 2.735 ;
      LAYER metal2 ;
        RECT 32.4425 2.055 32.5775 2.125 ;
      LAYER via1 ;
        RECT 32.4775 2.0575 32.5425 2.1225 ;
    END
  END rf_data[12]
  PIN rf_data[13]
    DIRECTION OUTPUT ;
    USE SIGNAL ;
    PORT
      LAYER metal1 ;
        RECT 35.135 1.6875 35.2 2.735 ;
      LAYER metal2 ;
        RECT 35.1 2.055 35.235 2.125 ;
      LAYER via1 ;
        RECT 35.135 2.0575 35.2 2.1225 ;
    END
  END rf_data[13]
  PIN rf_data[14]
    DIRECTION OUTPUT ;
    USE SIGNAL ;
    PORT
      LAYER metal1 ;
        RECT 37.7925 1.6875 37.8575 2.735 ;
      LAYER metal2 ;
        RECT 37.7575 2.055 37.8925 2.125 ;
      LAYER via1 ;
        RECT 37.7925 2.0575 37.8575 2.1225 ;
    END
  END rf_data[14]
  PIN rf_data[15]
    DIRECTION OUTPUT ;
    USE SIGNAL ;
    PORT
      LAYER metal1 ;
        RECT 40.45 1.6875 40.515 2.735 ;
      LAYER metal2 ;
        RECT 40.415 2.055 40.55 2.125 ;
      LAYER via1 ;
        RECT 40.45 2.0575 40.515 2.1225 ;
    END
  END rf_data[15]
  PIN rf_data[16]
    DIRECTION OUTPUT ;
    USE SIGNAL ;
    PORT
      LAYER metal1 ;
        RECT 0.5875 0.265 0.6525 1.3125 ;
      LAYER metal2 ;
        RECT 0.5525 0.875 0.6875 0.945 ;
      LAYER via1 ;
        RECT 0.5875 0.8775 0.6525 0.9425 ;
    END
  END rf_data[16]
  PIN rf_data[17]
    DIRECTION OUTPUT ;
    USE SIGNAL ;
    PORT
      LAYER metal1 ;
        RECT 3.245 0.265 3.31 1.3125 ;
      LAYER metal2 ;
        RECT 3.21 0.875 3.345 0.945 ;
      LAYER via1 ;
        RECT 3.245 0.8775 3.31 0.9425 ;
    END
  END rf_data[17]
  PIN rf_data[18]
    DIRECTION OUTPUT ;
    USE SIGNAL ;
    PORT
      LAYER metal1 ;
        RECT 5.9025 0.265 5.9675 1.3125 ;
      LAYER metal2 ;
        RECT 5.8675 0.875 6.0025 0.945 ;
      LAYER via1 ;
        RECT 5.9025 0.8775 5.9675 0.9425 ;
    END
  END rf_data[18]
  PIN rf_data[19]
    DIRECTION OUTPUT ;
    USE SIGNAL ;
    PORT
      LAYER metal1 ;
        RECT 8.56 0.265 8.625 1.3125 ;
      LAYER metal2 ;
        RECT 8.525 0.875 8.66 0.945 ;
      LAYER via1 ;
        RECT 8.56 0.8775 8.625 0.9425 ;
    END
  END rf_data[19]
  PIN rf_data[1]
    DIRECTION OUTPUT ;
    USE SIGNAL ;
    PORT
      LAYER metal1 ;
        RECT 3.245 1.6875 3.31 2.735 ;
      LAYER metal2 ;
        RECT 3.21 2.055 3.345 2.125 ;
      LAYER via1 ;
        RECT 3.245 2.0575 3.31 2.1225 ;
    END
  END rf_data[1]
  PIN rf_data[20]
    DIRECTION OUTPUT ;
    USE SIGNAL ;
    PORT
      LAYER metal1 ;
        RECT 11.2175 0.265 11.2825 1.3125 ;
      LAYER metal2 ;
        RECT 11.1825 0.875 11.3175 0.945 ;
      LAYER via1 ;
        RECT 11.2175 0.8775 11.2825 0.9425 ;
    END
  END rf_data[20]
  PIN rf_data[21]
    DIRECTION OUTPUT ;
    USE SIGNAL ;
    PORT
      LAYER metal1 ;
        RECT 13.875 0.265 13.94 1.3125 ;
      LAYER metal2 ;
        RECT 13.84 0.875 13.975 0.945 ;
      LAYER via1 ;
        RECT 13.875 0.8775 13.94 0.9425 ;
    END
  END rf_data[21]
  PIN rf_data[22]
    DIRECTION OUTPUT ;
    USE SIGNAL ;
    PORT
      LAYER metal1 ;
        RECT 16.5325 0.265 16.5975 1.3125 ;
      LAYER metal2 ;
        RECT 16.4975 0.875 16.6325 0.945 ;
      LAYER via1 ;
        RECT 16.5325 0.8775 16.5975 0.9425 ;
    END
  END rf_data[22]
  PIN rf_data[23]
    DIRECTION OUTPUT ;
    USE SIGNAL ;
    PORT
      LAYER metal1 ;
        RECT 19.19 0.265 19.255 1.3125 ;
      LAYER metal2 ;
        RECT 19.155 0.875 19.29 0.945 ;
      LAYER via1 ;
        RECT 19.19 0.8775 19.255 0.9425 ;
    END
  END rf_data[23]
  PIN rf_data[24]
    DIRECTION OUTPUT ;
    USE SIGNAL ;
    PORT
      LAYER metal1 ;
        RECT 21.8475 0.265 21.9125 1.3125 ;
      LAYER metal2 ;
        RECT 21.8125 0.875 21.9475 0.945 ;
      LAYER via1 ;
        RECT 21.8475 0.8775 21.9125 0.9425 ;
    END
  END rf_data[24]
  PIN rf_data[25]
    DIRECTION OUTPUT ;
    USE SIGNAL ;
    PORT
      LAYER metal1 ;
        RECT 24.505 0.265 24.57 1.3125 ;
      LAYER metal2 ;
        RECT 24.47 0.875 24.605 0.945 ;
      LAYER via1 ;
        RECT 24.505 0.8775 24.57 0.9425 ;
    END
  END rf_data[25]
  PIN rf_data[26]
    DIRECTION OUTPUT ;
    USE SIGNAL ;
    PORT
      LAYER metal1 ;
        RECT 27.1625 0.265 27.2275 1.3125 ;
      LAYER metal2 ;
        RECT 27.1275 0.875 27.2625 0.945 ;
      LAYER via1 ;
        RECT 27.1625 0.8775 27.2275 0.9425 ;
    END
  END rf_data[26]
  PIN rf_data[27]
    DIRECTION OUTPUT ;
    USE SIGNAL ;
    PORT
      LAYER metal1 ;
        RECT 29.82 0.265 29.885 1.3125 ;
      LAYER metal2 ;
        RECT 29.785 0.875 29.92 0.945 ;
      LAYER via1 ;
        RECT 29.82 0.8775 29.885 0.9425 ;
    END
  END rf_data[27]
  PIN rf_data[28]
    DIRECTION OUTPUT ;
    USE SIGNAL ;
    PORT
      LAYER metal1 ;
        RECT 32.4775 0.265 32.5425 1.3125 ;
      LAYER metal2 ;
        RECT 32.4425 0.875 32.5775 0.945 ;
      LAYER via1 ;
        RECT 32.4775 0.8775 32.5425 0.9425 ;
    END
  END rf_data[28]
  PIN rf_data[29]
    DIRECTION OUTPUT ;
    USE SIGNAL ;
    PORT
      LAYER metal1 ;
        RECT 35.135 0.265 35.2 1.3125 ;
      LAYER metal2 ;
        RECT 35.1 0.875 35.235 0.945 ;
      LAYER via1 ;
        RECT 35.135 0.8775 35.2 0.9425 ;
    END
  END rf_data[29]
  PIN rf_data[2]
    DIRECTION OUTPUT ;
    USE SIGNAL ;
    PORT
      LAYER metal1 ;
        RECT 5.9025 1.6875 5.9675 2.735 ;
      LAYER metal2 ;
        RECT 5.8675 2.055 6.0025 2.125 ;
      LAYER via1 ;
        RECT 5.9025 2.0575 5.9675 2.1225 ;
    END
  END rf_data[2]
  PIN rf_data[30]
    DIRECTION OUTPUT ;
    USE SIGNAL ;
    PORT
      LAYER metal1 ;
        RECT 37.7925 0.265 37.8575 1.3125 ;
      LAYER metal2 ;
        RECT 37.7575 0.875 37.8925 0.945 ;
      LAYER via1 ;
        RECT 37.7925 0.8775 37.8575 0.9425 ;
    END
  END rf_data[30]
  PIN rf_data[31]
    DIRECTION OUTPUT ;
    USE SIGNAL ;
    PORT
      LAYER metal1 ;
        RECT 40.45 0.265 40.515 1.3125 ;
      LAYER metal2 ;
        RECT 40.415 0.875 40.55 0.945 ;
      LAYER via1 ;
        RECT 40.45 0.8775 40.515 0.9425 ;
    END
  END rf_data[31]
  PIN rf_data[3]
    DIRECTION OUTPUT ;
    USE SIGNAL ;
    PORT
      LAYER metal1 ;
        RECT 8.56 1.6875 8.625 2.735 ;
      LAYER metal2 ;
        RECT 8.525 2.055 8.66 2.125 ;
      LAYER via1 ;
        RECT 8.56 2.0575 8.625 2.1225 ;
    END
  END rf_data[3]
  PIN rf_data[4]
    DIRECTION OUTPUT ;
    USE SIGNAL ;
    PORT
      LAYER metal1 ;
        RECT 11.2175 1.6875 11.2825 2.735 ;
      LAYER metal2 ;
        RECT 11.1825 2.055 11.3175 2.125 ;
      LAYER via1 ;
        RECT 11.2175 2.0575 11.2825 2.1225 ;
    END
  END rf_data[4]
  PIN rf_data[5]
    DIRECTION OUTPUT ;
    USE SIGNAL ;
    PORT
      LAYER metal1 ;
        RECT 13.875 1.6875 13.94 2.735 ;
      LAYER metal2 ;
        RECT 13.84 2.055 13.975 2.125 ;
      LAYER via1 ;
        RECT 13.875 2.0575 13.94 2.1225 ;
    END
  END rf_data[5]
  PIN rf_data[6]
    DIRECTION OUTPUT ;
    USE SIGNAL ;
    PORT
      LAYER metal1 ;
        RECT 16.5325 1.6875 16.5975 2.735 ;
      LAYER metal2 ;
        RECT 16.4975 2.055 16.6325 2.125 ;
      LAYER via1 ;
        RECT 16.5325 2.0575 16.5975 2.1225 ;
    END
  END rf_data[6]
  PIN rf_data[7]
    DIRECTION OUTPUT ;
    USE SIGNAL ;
    PORT
      LAYER metal1 ;
        RECT 19.19 1.6875 19.255 2.735 ;
      LAYER metal2 ;
        RECT 19.155 2.055 19.29 2.125 ;
      LAYER via1 ;
        RECT 19.19 2.0575 19.255 2.1225 ;
    END
  END rf_data[7]
  PIN rf_data[8]
    DIRECTION OUTPUT ;
    USE SIGNAL ;
    PORT
      LAYER metal1 ;
        RECT 21.8475 1.6875 21.9125 2.735 ;
      LAYER metal2 ;
        RECT 21.8125 2.055 21.9475 2.125 ;
      LAYER via1 ;
        RECT 21.8475 2.0575 21.9125 2.1225 ;
    END
  END rf_data[8]
  PIN rf_data[9]
    DIRECTION OUTPUT ;
    USE SIGNAL ;
    PORT
      LAYER metal1 ;
        RECT 24.505 1.6875 24.57 2.735 ;
      LAYER metal2 ;
        RECT 24.47 2.055 24.605 2.125 ;
      LAYER via1 ;
        RECT 24.505 2.0575 24.57 2.1225 ;
    END
  END rf_data[9]
  PIN rs1_rdata
    DIRECTION OUTPUT ;
    USE SIGNAL ;
    PORT
      LAYER metal1 ;
        RECT 44.16 0.2875 44.225 1.335 ;
        RECT 43.9175 0.9725 44.225 1.0375 ;
        RECT 43.9175 0.935 43.9825 1.07 ;
      LAYER metal2 ;
        RECT 43.8825 0.9675 44.0175 1.0375 ;
      LAYER via1 ;
        RECT 43.9175 0.97 43.9825 1.035 ;
    END
  END rs1_rdata
  PIN rs1_sel[0]
    DIRECTION INPUT ;
    USE SIGNAL ;
    PORT
      LAYER metal1 ;
        RECT 2.1425 2.145 2.2075 2.2825 ;
        RECT 1.7275 2.1475 1.7925 2.2825 ;
      LAYER metal3 ;
        RECT 1.7275 0 1.7975 3.0025 ;
      LAYER metal2 ;
        RECT 1.6925 2.18 2.2425 2.25 ;
      LAYER via1 ;
        RECT 1.7275 2.1825 1.7925 2.2475 ;
        RECT 2.1425 2.1825 2.2075 2.2475 ;
      LAYER via2 ;
        RECT 1.7275 2.18 1.7975 2.25 ;
    END
  END rs1_sel[0]
  PIN rs1_sel[10]
    DIRECTION INPUT ;
    USE SIGNAL ;
    PORT
      LAYER metal1 ;
        RECT 28.7175 2.145 28.7825 2.2825 ;
        RECT 28.3025 2.1475 28.3675 2.2825 ;
      LAYER metal3 ;
        RECT 28.3025 0 28.3725 3.0025 ;
      LAYER metal2 ;
        RECT 28.2675 2.18 28.8175 2.25 ;
      LAYER via1 ;
        RECT 28.3025 2.1825 28.3675 2.2475 ;
        RECT 28.7175 2.1825 28.7825 2.2475 ;
      LAYER via2 ;
        RECT 28.3025 2.18 28.3725 2.25 ;
    END
  END rs1_sel[10]
  PIN rs1_sel[11]
    DIRECTION INPUT ;
    USE SIGNAL ;
    PORT
      LAYER metal1 ;
        RECT 31.375 2.145 31.44 2.2825 ;
        RECT 30.96 2.1475 31.025 2.2825 ;
      LAYER metal3 ;
        RECT 30.96 0 31.03 3.0025 ;
      LAYER metal2 ;
        RECT 30.925 2.18 31.475 2.25 ;
      LAYER via1 ;
        RECT 30.96 2.1825 31.025 2.2475 ;
        RECT 31.375 2.1825 31.44 2.2475 ;
      LAYER via2 ;
        RECT 30.96 2.18 31.03 2.25 ;
    END
  END rs1_sel[11]
  PIN rs1_sel[12]
    DIRECTION INPUT ;
    USE SIGNAL ;
    PORT
      LAYER metal1 ;
        RECT 34.0325 2.145 34.0975 2.2825 ;
        RECT 33.6175 2.1475 33.6825 2.2825 ;
      LAYER metal3 ;
        RECT 33.6175 0 33.6875 3.0025 ;
      LAYER metal2 ;
        RECT 33.5825 2.18 34.1325 2.25 ;
      LAYER via1 ;
        RECT 33.6175 2.1825 33.6825 2.2475 ;
        RECT 34.0325 2.1825 34.0975 2.2475 ;
      LAYER via2 ;
        RECT 33.6175 2.18 33.6875 2.25 ;
    END
  END rs1_sel[12]
  PIN rs1_sel[13]
    DIRECTION INPUT ;
    USE SIGNAL ;
    PORT
      LAYER metal1 ;
        RECT 36.69 2.145 36.755 2.2825 ;
        RECT 36.275 2.1475 36.34 2.2825 ;
      LAYER metal3 ;
        RECT 36.275 0 36.345 3.0025 ;
      LAYER metal2 ;
        RECT 36.24 2.18 36.79 2.25 ;
      LAYER via1 ;
        RECT 36.275 2.1825 36.34 2.2475 ;
        RECT 36.69 2.1825 36.755 2.2475 ;
      LAYER via2 ;
        RECT 36.275 2.18 36.345 2.25 ;
    END
  END rs1_sel[13]
  PIN rs1_sel[14]
    DIRECTION INPUT ;
    USE SIGNAL ;
    PORT
      LAYER metal1 ;
        RECT 39.3475 2.145 39.4125 2.2825 ;
        RECT 38.9325 2.1475 38.9975 2.2825 ;
      LAYER metal3 ;
        RECT 38.9325 0 39.0025 3.0025 ;
      LAYER metal2 ;
        RECT 38.8975 2.18 39.4475 2.25 ;
      LAYER via1 ;
        RECT 38.9325 2.1825 38.9975 2.2475 ;
        RECT 39.3475 2.1825 39.4125 2.2475 ;
      LAYER via2 ;
        RECT 38.9325 2.18 39.0025 2.25 ;
    END
  END rs1_sel[14]
  PIN rs1_sel[15]
    DIRECTION INPUT ;
    USE SIGNAL ;
    PORT
      LAYER metal1 ;
        RECT 42.005 2.145 42.07 2.2825 ;
        RECT 41.59 2.1475 41.655 2.2825 ;
      LAYER metal3 ;
        RECT 41.59 0 41.66 3.0025 ;
      LAYER metal2 ;
        RECT 41.555 2.18 42.105 2.25 ;
      LAYER via1 ;
        RECT 41.59 2.1825 41.655 2.2475 ;
        RECT 42.005 2.1825 42.07 2.2475 ;
      LAYER via2 ;
        RECT 41.59 2.18 41.66 2.25 ;
    END
  END rs1_sel[15]
  PIN rs1_sel[16]
    DIRECTION INPUT ;
    USE SIGNAL ;
    PORT
      LAYER metal1 ;
        RECT 2.1425 0.7175 2.2075 0.855 ;
        RECT 1.7275 0.7175 1.7925 0.8525 ;
      LAYER metal3 ;
        RECT 1.8675 0 1.9375 3.0025 ;
      LAYER metal2 ;
        RECT 1.6925 0.75 2.2425 0.82 ;
      LAYER via1 ;
        RECT 1.7275 0.7525 1.7925 0.8175 ;
        RECT 2.1425 0.7525 2.2075 0.8175 ;
      LAYER via2 ;
        RECT 1.8675 0.75 1.9375 0.82 ;
    END
  END rs1_sel[16]
  PIN rs1_sel[17]
    DIRECTION INPUT ;
    USE SIGNAL ;
    PORT
      LAYER metal1 ;
        RECT 4.8 0.7175 4.865 0.855 ;
        RECT 4.385 0.7175 4.45 0.8525 ;
      LAYER metal3 ;
        RECT 4.525 0 4.595 3.0025 ;
      LAYER metal2 ;
        RECT 4.35 0.75 4.9 0.82 ;
      LAYER via1 ;
        RECT 4.385 0.7525 4.45 0.8175 ;
        RECT 4.8 0.7525 4.865 0.8175 ;
      LAYER via2 ;
        RECT 4.525 0.75 4.595 0.82 ;
    END
  END rs1_sel[17]
  PIN rs1_sel[18]
    DIRECTION INPUT ;
    USE SIGNAL ;
    PORT
      LAYER metal1 ;
        RECT 7.4575 0.7175 7.5225 0.855 ;
        RECT 7.0425 0.7175 7.1075 0.8525 ;
      LAYER metal3 ;
        RECT 7.1825 0 7.2525 3.0025 ;
      LAYER metal2 ;
        RECT 7.0075 0.75 7.5575 0.82 ;
      LAYER via1 ;
        RECT 7.0425 0.7525 7.1075 0.8175 ;
        RECT 7.4575 0.7525 7.5225 0.8175 ;
      LAYER via2 ;
        RECT 7.1825 0.75 7.2525 0.82 ;
    END
  END rs1_sel[18]
  PIN rs1_sel[19]
    DIRECTION INPUT ;
    USE SIGNAL ;
    PORT
      LAYER metal1 ;
        RECT 10.115 0.7175 10.18 0.855 ;
        RECT 9.7 0.7175 9.765 0.8525 ;
      LAYER metal3 ;
        RECT 9.84 0 9.91 3.0025 ;
      LAYER metal2 ;
        RECT 9.665 0.75 10.215 0.82 ;
      LAYER via1 ;
        RECT 9.7 0.7525 9.765 0.8175 ;
        RECT 10.115 0.7525 10.18 0.8175 ;
      LAYER via2 ;
        RECT 9.84 0.75 9.91 0.82 ;
    END
  END rs1_sel[19]
  PIN rs1_sel[1]
    DIRECTION INPUT ;
    USE SIGNAL ;
    PORT
      LAYER metal1 ;
        RECT 4.8 2.145 4.865 2.2825 ;
        RECT 4.385 2.1475 4.45 2.2825 ;
      LAYER metal3 ;
        RECT 4.385 0 4.455 3.0025 ;
      LAYER metal2 ;
        RECT 4.35 2.18 4.9 2.25 ;
      LAYER via1 ;
        RECT 4.385 2.1825 4.45 2.2475 ;
        RECT 4.8 2.1825 4.865 2.2475 ;
      LAYER via2 ;
        RECT 4.385 2.18 4.455 2.25 ;
    END
  END rs1_sel[1]
  PIN rs1_sel[20]
    DIRECTION INPUT ;
    USE SIGNAL ;
    PORT
      LAYER metal1 ;
        RECT 12.7725 0.7175 12.8375 0.855 ;
        RECT 12.3575 0.7175 12.4225 0.8525 ;
      LAYER metal3 ;
        RECT 12.4975 0 12.5675 3.0025 ;
      LAYER metal2 ;
        RECT 12.3225 0.75 12.8725 0.82 ;
      LAYER via1 ;
        RECT 12.3575 0.7525 12.4225 0.8175 ;
        RECT 12.7725 0.7525 12.8375 0.8175 ;
      LAYER via2 ;
        RECT 12.4975 0.75 12.5675 0.82 ;
    END
  END rs1_sel[20]
  PIN rs1_sel[21]
    DIRECTION INPUT ;
    USE SIGNAL ;
    PORT
      LAYER metal1 ;
        RECT 15.43 0.7175 15.495 0.855 ;
        RECT 15.015 0.7175 15.08 0.8525 ;
      LAYER metal3 ;
        RECT 15.155 0 15.225 3.0025 ;
      LAYER metal2 ;
        RECT 14.98 0.75 15.53 0.82 ;
      LAYER via1 ;
        RECT 15.015 0.7525 15.08 0.8175 ;
        RECT 15.43 0.7525 15.495 0.8175 ;
      LAYER via2 ;
        RECT 15.155 0.75 15.225 0.82 ;
    END
  END rs1_sel[21]
  PIN rs1_sel[22]
    DIRECTION INPUT ;
    USE SIGNAL ;
    PORT
      LAYER metal1 ;
        RECT 18.0875 0.7175 18.1525 0.855 ;
        RECT 17.6725 0.7175 17.7375 0.8525 ;
      LAYER metal3 ;
        RECT 17.8125 0 17.8825 3.0025 ;
      LAYER metal2 ;
        RECT 17.6375 0.75 18.1875 0.82 ;
      LAYER via1 ;
        RECT 17.6725 0.7525 17.7375 0.8175 ;
        RECT 18.0875 0.7525 18.1525 0.8175 ;
      LAYER via2 ;
        RECT 17.8125 0.75 17.8825 0.82 ;
    END
  END rs1_sel[22]
  PIN rs1_sel[23]
    DIRECTION INPUT ;
    USE SIGNAL ;
    PORT
      LAYER metal1 ;
        RECT 20.745 0.7175 20.81 0.855 ;
        RECT 20.33 0.7175 20.395 0.8525 ;
      LAYER metal3 ;
        RECT 20.47 0 20.54 3.0025 ;
      LAYER metal2 ;
        RECT 20.295 0.75 20.845 0.82 ;
      LAYER via1 ;
        RECT 20.33 0.7525 20.395 0.8175 ;
        RECT 20.745 0.7525 20.81 0.8175 ;
      LAYER via2 ;
        RECT 20.47 0.75 20.54 0.82 ;
    END
  END rs1_sel[23]
  PIN rs1_sel[24]
    DIRECTION INPUT ;
    USE SIGNAL ;
    PORT
      LAYER metal1 ;
        RECT 23.4025 0.7175 23.4675 0.855 ;
        RECT 22.9875 0.7175 23.0525 0.8525 ;
      LAYER metal3 ;
        RECT 23.1275 0 23.1975 3.0025 ;
      LAYER metal2 ;
        RECT 22.9525 0.75 23.5025 0.82 ;
      LAYER via1 ;
        RECT 22.9875 0.7525 23.0525 0.8175 ;
        RECT 23.4025 0.7525 23.4675 0.8175 ;
      LAYER via2 ;
        RECT 23.1275 0.75 23.1975 0.82 ;
    END
  END rs1_sel[24]
  PIN rs1_sel[25]
    DIRECTION INPUT ;
    USE SIGNAL ;
    PORT
      LAYER metal1 ;
        RECT 26.06 0.7175 26.125 0.855 ;
        RECT 25.645 0.7175 25.71 0.8525 ;
      LAYER metal3 ;
        RECT 25.785 0 25.855 3.0025 ;
      LAYER metal2 ;
        RECT 25.61 0.75 26.16 0.82 ;
      LAYER via1 ;
        RECT 25.645 0.7525 25.71 0.8175 ;
        RECT 26.06 0.7525 26.125 0.8175 ;
      LAYER via2 ;
        RECT 25.785 0.75 25.855 0.82 ;
    END
  END rs1_sel[25]
  PIN rs1_sel[26]
    DIRECTION INPUT ;
    USE SIGNAL ;
    PORT
      LAYER metal1 ;
        RECT 28.7175 0.7175 28.7825 0.855 ;
        RECT 28.3025 0.7175 28.3675 0.8525 ;
      LAYER metal3 ;
        RECT 28.4425 0 28.5125 3.0025 ;
      LAYER metal2 ;
        RECT 28.2675 0.75 28.8175 0.82 ;
      LAYER via1 ;
        RECT 28.3025 0.7525 28.3675 0.8175 ;
        RECT 28.7175 0.7525 28.7825 0.8175 ;
      LAYER via2 ;
        RECT 28.4425 0.75 28.5125 0.82 ;
    END
  END rs1_sel[26]
  PIN rs1_sel[27]
    DIRECTION INPUT ;
    USE SIGNAL ;
    PORT
      LAYER metal1 ;
        RECT 31.375 0.7175 31.44 0.855 ;
        RECT 30.96 0.7175 31.025 0.8525 ;
      LAYER metal3 ;
        RECT 31.1 0 31.17 3.0025 ;
      LAYER metal2 ;
        RECT 30.925 0.75 31.475 0.82 ;
      LAYER via1 ;
        RECT 30.96 0.7525 31.025 0.8175 ;
        RECT 31.375 0.7525 31.44 0.8175 ;
      LAYER via2 ;
        RECT 31.1 0.75 31.17 0.82 ;
    END
  END rs1_sel[27]
  PIN rs1_sel[28]
    DIRECTION INPUT ;
    USE SIGNAL ;
    PORT
      LAYER metal1 ;
        RECT 34.0325 0.7175 34.0975 0.855 ;
        RECT 33.6175 0.7175 33.6825 0.8525 ;
      LAYER metal3 ;
        RECT 33.7575 0 33.8275 3.0025 ;
      LAYER metal2 ;
        RECT 33.5825 0.75 34.1325 0.82 ;
      LAYER via1 ;
        RECT 33.6175 0.7525 33.6825 0.8175 ;
        RECT 34.0325 0.7525 34.0975 0.8175 ;
      LAYER via2 ;
        RECT 33.7575 0.75 33.8275 0.82 ;
    END
  END rs1_sel[28]
  PIN rs1_sel[29]
    DIRECTION INPUT ;
    USE SIGNAL ;
    PORT
      LAYER metal1 ;
        RECT 36.69 0.7175 36.755 0.855 ;
        RECT 36.275 0.7175 36.34 0.8525 ;
      LAYER metal3 ;
        RECT 36.415 0 36.485 3.0025 ;
      LAYER metal2 ;
        RECT 36.24 0.75 36.79 0.82 ;
      LAYER via1 ;
        RECT 36.275 0.7525 36.34 0.8175 ;
        RECT 36.69 0.7525 36.755 0.8175 ;
      LAYER via2 ;
        RECT 36.415 0.75 36.485 0.82 ;
    END
  END rs1_sel[29]
  PIN rs1_sel[2]
    DIRECTION INPUT ;
    USE SIGNAL ;
    PORT
      LAYER metal1 ;
        RECT 7.4575 2.145 7.5225 2.2825 ;
        RECT 7.0425 2.1475 7.1075 2.2825 ;
      LAYER metal3 ;
        RECT 7.0425 0 7.1125 3.0025 ;
      LAYER metal2 ;
        RECT 7.0075 2.18 7.5575 2.25 ;
      LAYER via1 ;
        RECT 7.0425 2.1825 7.1075 2.2475 ;
        RECT 7.4575 2.1825 7.5225 2.2475 ;
      LAYER via2 ;
        RECT 7.0425 2.18 7.1125 2.25 ;
    END
  END rs1_sel[2]
  PIN rs1_sel[30]
    DIRECTION INPUT ;
    USE SIGNAL ;
    PORT
      LAYER metal1 ;
        RECT 39.3475 0.7175 39.4125 0.855 ;
        RECT 38.9325 0.7175 38.9975 0.8525 ;
      LAYER metal3 ;
        RECT 39.0725 0 39.1425 3.0025 ;
      LAYER metal2 ;
        RECT 38.8975 0.75 39.4475 0.82 ;
      LAYER via1 ;
        RECT 38.9325 0.7525 38.9975 0.8175 ;
        RECT 39.3475 0.7525 39.4125 0.8175 ;
      LAYER via2 ;
        RECT 39.0725 0.75 39.1425 0.82 ;
    END
  END rs1_sel[30]
  PIN rs1_sel[31]
    DIRECTION INPUT ;
    USE SIGNAL ;
    PORT
      LAYER metal1 ;
        RECT 42.005 0.7175 42.07 0.855 ;
        RECT 41.59 0.7175 41.655 0.8525 ;
      LAYER metal3 ;
        RECT 41.73 0 41.8 3.0025 ;
      LAYER metal2 ;
        RECT 41.555 0.75 42.105 0.82 ;
      LAYER via1 ;
        RECT 41.59 0.7525 41.655 0.8175 ;
        RECT 42.005 0.7525 42.07 0.8175 ;
      LAYER via2 ;
        RECT 41.73 0.75 41.8 0.82 ;
    END
  END rs1_sel[31]
  PIN rs1_sel[3]
    DIRECTION INPUT ;
    USE SIGNAL ;
    PORT
      LAYER metal1 ;
        RECT 10.115 2.145 10.18 2.2825 ;
        RECT 9.7 2.1475 9.765 2.2825 ;
      LAYER metal3 ;
        RECT 9.7 0 9.77 3.0025 ;
      LAYER metal2 ;
        RECT 9.665 2.18 10.215 2.25 ;
      LAYER via1 ;
        RECT 9.7 2.1825 9.765 2.2475 ;
        RECT 10.115 2.1825 10.18 2.2475 ;
      LAYER via2 ;
        RECT 9.7 2.18 9.77 2.25 ;
    END
  END rs1_sel[3]
  PIN rs1_sel[4]
    DIRECTION INPUT ;
    USE SIGNAL ;
    PORT
      LAYER metal1 ;
        RECT 12.7725 2.145 12.8375 2.2825 ;
        RECT 12.3575 2.1475 12.4225 2.2825 ;
      LAYER metal3 ;
        RECT 12.3575 0 12.4275 3.0025 ;
      LAYER metal2 ;
        RECT 12.3225 2.18 12.8725 2.25 ;
      LAYER via1 ;
        RECT 12.3575 2.1825 12.4225 2.2475 ;
        RECT 12.7725 2.1825 12.8375 2.2475 ;
      LAYER via2 ;
        RECT 12.3575 2.18 12.4275 2.25 ;
    END
  END rs1_sel[4]
  PIN rs1_sel[5]
    DIRECTION INPUT ;
    USE SIGNAL ;
    PORT
      LAYER metal1 ;
        RECT 15.43 2.145 15.495 2.2825 ;
        RECT 15.015 2.1475 15.08 2.2825 ;
      LAYER metal3 ;
        RECT 15.015 0 15.085 3.0025 ;
      LAYER metal2 ;
        RECT 14.98 2.18 15.53 2.25 ;
      LAYER via1 ;
        RECT 15.015 2.1825 15.08 2.2475 ;
        RECT 15.43 2.1825 15.495 2.2475 ;
      LAYER via2 ;
        RECT 15.015 2.18 15.085 2.25 ;
    END
  END rs1_sel[5]
  PIN rs1_sel[6]
    DIRECTION INPUT ;
    USE SIGNAL ;
    PORT
      LAYER metal1 ;
        RECT 18.0875 2.145 18.1525 2.2825 ;
        RECT 17.6725 2.1475 17.7375 2.2825 ;
      LAYER metal3 ;
        RECT 17.6725 0 17.7425 3.0025 ;
      LAYER metal2 ;
        RECT 17.6375 2.18 18.1875 2.25 ;
      LAYER via1 ;
        RECT 17.6725 2.1825 17.7375 2.2475 ;
        RECT 18.0875 2.1825 18.1525 2.2475 ;
      LAYER via2 ;
        RECT 17.6725 2.18 17.7425 2.25 ;
    END
  END rs1_sel[6]
  PIN rs1_sel[7]
    DIRECTION INPUT ;
    USE SIGNAL ;
    PORT
      LAYER metal1 ;
        RECT 20.745 2.145 20.81 2.2825 ;
        RECT 20.33 2.1475 20.395 2.2825 ;
      LAYER metal3 ;
        RECT 20.33 0 20.4 3.0025 ;
      LAYER metal2 ;
        RECT 20.295 2.18 20.845 2.25 ;
      LAYER via1 ;
        RECT 20.33 2.1825 20.395 2.2475 ;
        RECT 20.745 2.1825 20.81 2.2475 ;
      LAYER via2 ;
        RECT 20.33 2.18 20.4 2.25 ;
    END
  END rs1_sel[7]
  PIN rs1_sel[8]
    DIRECTION INPUT ;
    USE SIGNAL ;
    PORT
      LAYER metal1 ;
        RECT 23.4025 2.145 23.4675 2.2825 ;
        RECT 22.9875 2.1475 23.0525 2.2825 ;
      LAYER metal3 ;
        RECT 22.9875 0 23.0575 3.0025 ;
      LAYER metal2 ;
        RECT 22.9525 2.18 23.5025 2.25 ;
      LAYER via1 ;
        RECT 22.9875 2.1825 23.0525 2.2475 ;
        RECT 23.4025 2.1825 23.4675 2.2475 ;
      LAYER via2 ;
        RECT 22.9875 2.18 23.0575 2.25 ;
    END
  END rs1_sel[8]
  PIN rs1_sel[9]
    DIRECTION INPUT ;
    USE SIGNAL ;
    PORT
      LAYER metal1 ;
        RECT 26.06 2.145 26.125 2.2825 ;
        RECT 25.645 2.1475 25.71 2.2825 ;
      LAYER metal3 ;
        RECT 25.645 0 25.715 3.0025 ;
      LAYER metal2 ;
        RECT 25.61 2.18 26.16 2.25 ;
      LAYER via1 ;
        RECT 25.645 2.1825 25.71 2.2475 ;
        RECT 26.06 2.1825 26.125 2.2475 ;
      LAYER via2 ;
        RECT 25.645 2.18 25.715 2.25 ;
    END
  END rs1_sel[9]
  PIN rs2_rdata
    DIRECTION OUTPUT ;
    USE SIGNAL ;
    PORT
      LAYER metal1 ;
        RECT 44.16 1.665 44.225 2.7125 ;
        RECT 43.9175 1.9625 44.225 2.0275 ;
        RECT 43.9175 1.93 43.9825 2.065 ;
      LAYER metal2 ;
        RECT 43.8825 1.9625 44.0175 2.0325 ;
      LAYER via1 ;
        RECT 43.9175 1.965 43.9825 2.03 ;
    END
  END rs2_rdata
  PIN rs2_sel[0]
    DIRECTION INPUT ;
    USE SIGNAL ;
    PORT
      LAYER metal1 ;
        RECT 2.4025 1.8625 2.4675 1.9975 ;
        RECT 1.6175 1.895 1.6825 2.03 ;
      LAYER metal3 ;
        RECT 1.5875 0 1.6575 3.0025 ;
      LAYER metal2 ;
        RECT 1.5825 1.895 2.5025 1.965 ;
        RECT 1.5525 1.9275 1.7175 1.9975 ;
      LAYER via1 ;
        RECT 1.6175 1.93 1.6825 1.995 ;
        RECT 2.4025 1.8975 2.4675 1.9625 ;
      LAYER via2 ;
        RECT 1.5875 1.9275 1.6575 1.9975 ;
    END
  END rs2_sel[0]
  PIN rs2_sel[10]
    DIRECTION INPUT ;
    USE SIGNAL ;
    PORT
      LAYER metal1 ;
        RECT 28.9775 1.8625 29.0425 1.9975 ;
        RECT 28.1925 1.895 28.2575 2.03 ;
      LAYER metal3 ;
        RECT 28.1625 0 28.2325 3.0025 ;
      LAYER metal2 ;
        RECT 28.1575 1.895 29.0775 1.965 ;
        RECT 28.1275 1.9275 28.2925 1.9975 ;
      LAYER via1 ;
        RECT 28.1925 1.93 28.2575 1.995 ;
        RECT 28.9775 1.8975 29.0425 1.9625 ;
      LAYER via2 ;
        RECT 28.1625 1.9275 28.2325 1.9975 ;
    END
  END rs2_sel[10]
  PIN rs2_sel[11]
    DIRECTION INPUT ;
    USE SIGNAL ;
    PORT
      LAYER metal1 ;
        RECT 31.635 1.8625 31.7 1.9975 ;
        RECT 30.85 1.895 30.915 2.03 ;
      LAYER metal3 ;
        RECT 30.82 0 30.89 3.0025 ;
      LAYER metal2 ;
        RECT 30.815 1.895 31.735 1.965 ;
        RECT 30.785 1.9275 30.95 1.9975 ;
      LAYER via1 ;
        RECT 30.85 1.93 30.915 1.995 ;
        RECT 31.635 1.8975 31.7 1.9625 ;
      LAYER via2 ;
        RECT 30.82 1.9275 30.89 1.9975 ;
    END
  END rs2_sel[11]
  PIN rs2_sel[12]
    DIRECTION INPUT ;
    USE SIGNAL ;
    PORT
      LAYER metal1 ;
        RECT 34.2925 1.8625 34.3575 1.9975 ;
        RECT 33.5075 1.895 33.5725 2.03 ;
      LAYER metal3 ;
        RECT 33.4775 0 33.5475 3.0025 ;
      LAYER metal2 ;
        RECT 33.4725 1.895 34.3925 1.965 ;
        RECT 33.4425 1.9275 33.6075 1.9975 ;
      LAYER via1 ;
        RECT 33.5075 1.93 33.5725 1.995 ;
        RECT 34.2925 1.8975 34.3575 1.9625 ;
      LAYER via2 ;
        RECT 33.4775 1.9275 33.5475 1.9975 ;
    END
  END rs2_sel[12]
  PIN rs2_sel[13]
    DIRECTION INPUT ;
    USE SIGNAL ;
    PORT
      LAYER metal1 ;
        RECT 36.95 1.8625 37.015 1.9975 ;
        RECT 36.165 1.895 36.23 2.03 ;
      LAYER metal3 ;
        RECT 36.135 0 36.205 3.0025 ;
      LAYER metal2 ;
        RECT 36.13 1.895 37.05 1.965 ;
        RECT 36.1 1.9275 36.265 1.9975 ;
      LAYER via1 ;
        RECT 36.165 1.93 36.23 1.995 ;
        RECT 36.95 1.8975 37.015 1.9625 ;
      LAYER via2 ;
        RECT 36.135 1.9275 36.205 1.9975 ;
    END
  END rs2_sel[13]
  PIN rs2_sel[14]
    DIRECTION INPUT ;
    USE SIGNAL ;
    PORT
      LAYER metal1 ;
        RECT 39.6075 1.8625 39.6725 1.9975 ;
        RECT 38.8225 1.895 38.8875 2.03 ;
      LAYER metal3 ;
        RECT 38.7925 0 38.8625 3.0025 ;
      LAYER metal2 ;
        RECT 38.7875 1.895 39.7075 1.965 ;
        RECT 38.7575 1.9275 38.9225 1.9975 ;
      LAYER via1 ;
        RECT 38.8225 1.93 38.8875 1.995 ;
        RECT 39.6075 1.8975 39.6725 1.9625 ;
      LAYER via2 ;
        RECT 38.7925 1.9275 38.8625 1.9975 ;
    END
  END rs2_sel[14]
  PIN rs2_sel[15]
    DIRECTION INPUT ;
    USE SIGNAL ;
    PORT
      LAYER metal1 ;
        RECT 42.265 1.8625 42.33 1.9975 ;
        RECT 41.48 1.895 41.545 2.03 ;
      LAYER metal3 ;
        RECT 41.45 0 41.52 3.0025 ;
      LAYER metal2 ;
        RECT 41.445 1.895 42.365 1.965 ;
        RECT 41.415 1.9275 41.58 1.9975 ;
      LAYER via1 ;
        RECT 41.48 1.93 41.545 1.995 ;
        RECT 42.265 1.8975 42.33 1.9625 ;
      LAYER via2 ;
        RECT 41.45 1.9275 41.52 1.9975 ;
    END
  END rs2_sel[15]
  PIN rs2_sel[16]
    DIRECTION INPUT ;
    USE SIGNAL ;
    PORT
      LAYER metal1 ;
        RECT 2.4025 1.0025 2.4675 1.1375 ;
        RECT 1.6175 0.97 1.6825 1.105 ;
      LAYER metal3 ;
        RECT 2.0075 0 2.0775 3.0025 ;
      LAYER metal2 ;
        RECT 1.5825 1.035 2.5025 1.105 ;
        RECT 1.5825 1.0025 1.7175 1.105 ;
      LAYER via1 ;
        RECT 1.6175 1.005 1.6825 1.07 ;
        RECT 2.4025 1.0375 2.4675 1.1025 ;
      LAYER via2 ;
        RECT 2.0075 1.035 2.0775 1.105 ;
    END
  END rs2_sel[16]
  PIN rs2_sel[17]
    DIRECTION INPUT ;
    USE SIGNAL ;
    PORT
      LAYER metal1 ;
        RECT 5.06 1.0025 5.125 1.1375 ;
        RECT 4.275 0.97 4.34 1.105 ;
      LAYER metal3 ;
        RECT 4.665 0 4.735 3.0025 ;
      LAYER metal2 ;
        RECT 4.24 1.035 5.16 1.105 ;
        RECT 4.24 1.0025 4.375 1.105 ;
      LAYER via1 ;
        RECT 4.275 1.005 4.34 1.07 ;
        RECT 5.06 1.0375 5.125 1.1025 ;
      LAYER via2 ;
        RECT 4.665 1.035 4.735 1.105 ;
    END
  END rs2_sel[17]
  PIN rs2_sel[18]
    DIRECTION INPUT ;
    USE SIGNAL ;
    PORT
      LAYER metal1 ;
        RECT 7.7175 1.0025 7.7825 1.1375 ;
        RECT 6.9325 0.97 6.9975 1.105 ;
      LAYER metal3 ;
        RECT 7.3225 0 7.3925 3.0025 ;
      LAYER metal2 ;
        RECT 6.8975 1.035 7.8175 1.105 ;
        RECT 6.8975 1.0025 7.0325 1.105 ;
      LAYER via1 ;
        RECT 6.9325 1.005 6.9975 1.07 ;
        RECT 7.7175 1.0375 7.7825 1.1025 ;
      LAYER via2 ;
        RECT 7.3225 1.035 7.3925 1.105 ;
    END
  END rs2_sel[18]
  PIN rs2_sel[19]
    DIRECTION INPUT ;
    USE SIGNAL ;
    PORT
      LAYER metal1 ;
        RECT 10.375 1.0025 10.44 1.1375 ;
        RECT 9.59 0.97 9.655 1.105 ;
      LAYER metal3 ;
        RECT 9.98 0 10.05 3.0025 ;
      LAYER metal2 ;
        RECT 9.555 1.035 10.475 1.105 ;
        RECT 9.555 1.0025 9.69 1.105 ;
      LAYER via1 ;
        RECT 9.59 1.005 9.655 1.07 ;
        RECT 10.375 1.0375 10.44 1.1025 ;
      LAYER via2 ;
        RECT 9.98 1.035 10.05 1.105 ;
    END
  END rs2_sel[19]
  PIN rs2_sel[1]
    DIRECTION INPUT ;
    USE SIGNAL ;
    PORT
      LAYER metal1 ;
        RECT 5.06 1.8625 5.125 1.9975 ;
        RECT 4.275 1.895 4.34 2.03 ;
      LAYER metal3 ;
        RECT 4.245 0 4.315 3.0025 ;
      LAYER metal2 ;
        RECT 4.24 1.895 5.16 1.965 ;
        RECT 4.21 1.9275 4.375 1.9975 ;
      LAYER via1 ;
        RECT 4.275 1.93 4.34 1.995 ;
        RECT 5.06 1.8975 5.125 1.9625 ;
      LAYER via2 ;
        RECT 4.245 1.9275 4.315 1.9975 ;
    END
  END rs2_sel[1]
  PIN rs2_sel[20]
    DIRECTION INPUT ;
    USE SIGNAL ;
    PORT
      LAYER metal1 ;
        RECT 13.0325 1.0025 13.0975 1.1375 ;
        RECT 12.2475 0.97 12.3125 1.105 ;
      LAYER metal3 ;
        RECT 12.6375 0 12.7075 3.0025 ;
      LAYER metal2 ;
        RECT 12.2125 1.035 13.1325 1.105 ;
        RECT 12.2125 1.0025 12.3475 1.105 ;
      LAYER via1 ;
        RECT 12.2475 1.005 12.3125 1.07 ;
        RECT 13.0325 1.0375 13.0975 1.1025 ;
      LAYER via2 ;
        RECT 12.6375 1.035 12.7075 1.105 ;
    END
  END rs2_sel[20]
  PIN rs2_sel[21]
    DIRECTION INPUT ;
    USE SIGNAL ;
    PORT
      LAYER metal1 ;
        RECT 15.69 1.0025 15.755 1.1375 ;
        RECT 14.905 0.97 14.97 1.105 ;
      LAYER metal3 ;
        RECT 15.295 0 15.365 3.0025 ;
      LAYER metal2 ;
        RECT 14.87 1.035 15.79 1.105 ;
        RECT 14.87 1.0025 15.005 1.105 ;
      LAYER via1 ;
        RECT 14.905 1.005 14.97 1.07 ;
        RECT 15.69 1.0375 15.755 1.1025 ;
      LAYER via2 ;
        RECT 15.295 1.035 15.365 1.105 ;
    END
  END rs2_sel[21]
  PIN rs2_sel[22]
    DIRECTION INPUT ;
    USE SIGNAL ;
    PORT
      LAYER metal1 ;
        RECT 18.3475 1.0025 18.4125 1.1375 ;
        RECT 17.5625 0.97 17.6275 1.105 ;
      LAYER metal3 ;
        RECT 17.9525 0 18.0225 3.0025 ;
      LAYER metal2 ;
        RECT 17.5275 1.035 18.4475 1.105 ;
        RECT 17.5275 1.0025 17.6625 1.105 ;
      LAYER via1 ;
        RECT 17.5625 1.005 17.6275 1.07 ;
        RECT 18.3475 1.0375 18.4125 1.1025 ;
      LAYER via2 ;
        RECT 17.9525 1.035 18.0225 1.105 ;
    END
  END rs2_sel[22]
  PIN rs2_sel[23]
    DIRECTION INPUT ;
    USE SIGNAL ;
    PORT
      LAYER metal1 ;
        RECT 21.005 1.0025 21.07 1.1375 ;
        RECT 20.22 0.97 20.285 1.105 ;
      LAYER metal3 ;
        RECT 20.61 0 20.68 3.0025 ;
      LAYER metal2 ;
        RECT 20.185 1.035 21.105 1.105 ;
        RECT 20.185 1.0025 20.32 1.105 ;
      LAYER via1 ;
        RECT 20.22 1.005 20.285 1.07 ;
        RECT 21.005 1.0375 21.07 1.1025 ;
      LAYER via2 ;
        RECT 20.61 1.035 20.68 1.105 ;
    END
  END rs2_sel[23]
  PIN rs2_sel[24]
    DIRECTION INPUT ;
    USE SIGNAL ;
    PORT
      LAYER metal1 ;
        RECT 23.6625 1.0025 23.7275 1.1375 ;
        RECT 22.8775 0.97 22.9425 1.105 ;
      LAYER metal3 ;
        RECT 23.2675 0 23.3375 3.0025 ;
      LAYER metal2 ;
        RECT 22.8425 1.035 23.7625 1.105 ;
        RECT 22.8425 1.0025 22.9775 1.105 ;
      LAYER via1 ;
        RECT 22.8775 1.005 22.9425 1.07 ;
        RECT 23.6625 1.0375 23.7275 1.1025 ;
      LAYER via2 ;
        RECT 23.2675 1.035 23.3375 1.105 ;
    END
  END rs2_sel[24]
  PIN rs2_sel[25]
    DIRECTION INPUT ;
    USE SIGNAL ;
    PORT
      LAYER metal1 ;
        RECT 26.32 1.0025 26.385 1.1375 ;
        RECT 25.535 0.97 25.6 1.105 ;
      LAYER metal3 ;
        RECT 25.925 0 25.995 3.0025 ;
      LAYER metal2 ;
        RECT 25.5 1.035 26.42 1.105 ;
        RECT 25.5 1.0025 25.635 1.105 ;
      LAYER via1 ;
        RECT 25.535 1.005 25.6 1.07 ;
        RECT 26.32 1.0375 26.385 1.1025 ;
      LAYER via2 ;
        RECT 25.925 1.035 25.995 1.105 ;
    END
  END rs2_sel[25]
  PIN rs2_sel[26]
    DIRECTION INPUT ;
    USE SIGNAL ;
    PORT
      LAYER metal1 ;
        RECT 28.9775 1.0025 29.0425 1.1375 ;
        RECT 28.1925 0.97 28.2575 1.105 ;
      LAYER metal3 ;
        RECT 28.5825 0 28.6525 3.0025 ;
      LAYER metal2 ;
        RECT 28.1575 1.035 29.0775 1.105 ;
        RECT 28.1575 1.0025 28.2925 1.105 ;
      LAYER via1 ;
        RECT 28.1925 1.005 28.2575 1.07 ;
        RECT 28.9775 1.0375 29.0425 1.1025 ;
      LAYER via2 ;
        RECT 28.5825 1.035 28.6525 1.105 ;
    END
  END rs2_sel[26]
  PIN rs2_sel[27]
    DIRECTION INPUT ;
    USE SIGNAL ;
    PORT
      LAYER metal1 ;
        RECT 31.635 1.0025 31.7 1.1375 ;
        RECT 30.85 0.97 30.915 1.105 ;
      LAYER metal3 ;
        RECT 31.24 0 31.31 3.0025 ;
      LAYER metal2 ;
        RECT 30.815 1.035 31.735 1.105 ;
        RECT 30.815 1.0025 30.95 1.105 ;
      LAYER via1 ;
        RECT 30.85 1.005 30.915 1.07 ;
        RECT 31.635 1.0375 31.7 1.1025 ;
      LAYER via2 ;
        RECT 31.24 1.035 31.31 1.105 ;
    END
  END rs2_sel[27]
  PIN rs2_sel[28]
    DIRECTION INPUT ;
    USE SIGNAL ;
    PORT
      LAYER metal1 ;
        RECT 34.2925 1.0025 34.3575 1.1375 ;
        RECT 33.5075 0.97 33.5725 1.105 ;
      LAYER metal3 ;
        RECT 33.8975 0 33.9675 3.0025 ;
      LAYER metal2 ;
        RECT 33.4725 1.035 34.3925 1.105 ;
        RECT 33.4725 1.0025 33.6075 1.105 ;
      LAYER via1 ;
        RECT 33.5075 1.005 33.5725 1.07 ;
        RECT 34.2925 1.0375 34.3575 1.1025 ;
      LAYER via2 ;
        RECT 33.8975 1.035 33.9675 1.105 ;
    END
  END rs2_sel[28]
  PIN rs2_sel[29]
    DIRECTION INPUT ;
    USE SIGNAL ;
    PORT
      LAYER metal1 ;
        RECT 36.95 1.0025 37.015 1.1375 ;
        RECT 36.165 0.97 36.23 1.105 ;
      LAYER metal3 ;
        RECT 36.555 0 36.625 3.0025 ;
      LAYER metal2 ;
        RECT 36.13 1.035 37.05 1.105 ;
        RECT 36.13 1.0025 36.265 1.105 ;
      LAYER via1 ;
        RECT 36.165 1.005 36.23 1.07 ;
        RECT 36.95 1.0375 37.015 1.1025 ;
      LAYER via2 ;
        RECT 36.555 1.035 36.625 1.105 ;
    END
  END rs2_sel[29]
  PIN rs2_sel[2]
    DIRECTION INPUT ;
    USE SIGNAL ;
    PORT
      LAYER metal1 ;
        RECT 7.7175 1.8625 7.7825 1.9975 ;
        RECT 6.9325 1.895 6.9975 2.03 ;
      LAYER metal3 ;
        RECT 6.9025 0 6.9725 3.0025 ;
      LAYER metal2 ;
        RECT 6.8975 1.895 7.8175 1.965 ;
        RECT 6.8675 1.9275 7.0325 1.9975 ;
      LAYER via1 ;
        RECT 6.9325 1.93 6.9975 1.995 ;
        RECT 7.7175 1.8975 7.7825 1.9625 ;
      LAYER via2 ;
        RECT 6.9025 1.9275 6.9725 1.9975 ;
    END
  END rs2_sel[2]
  PIN rs2_sel[30]
    DIRECTION INPUT ;
    USE SIGNAL ;
    PORT
      LAYER metal1 ;
        RECT 39.6075 1.0025 39.6725 1.1375 ;
        RECT 38.8225 0.97 38.8875 1.105 ;
      LAYER metal3 ;
        RECT 39.2125 0 39.2825 3.0025 ;
      LAYER metal2 ;
        RECT 38.7875 1.035 39.7075 1.105 ;
        RECT 38.7875 1.0025 38.9225 1.105 ;
      LAYER via1 ;
        RECT 38.8225 1.005 38.8875 1.07 ;
        RECT 39.6075 1.0375 39.6725 1.1025 ;
      LAYER via2 ;
        RECT 39.2125 1.035 39.2825 1.105 ;
    END
  END rs2_sel[30]
  PIN rs2_sel[31]
    DIRECTION INPUT ;
    USE SIGNAL ;
    PORT
      LAYER metal1 ;
        RECT 42.265 1.0025 42.33 1.1375 ;
        RECT 41.48 0.97 41.545 1.105 ;
      LAYER metal3 ;
        RECT 41.87 0 41.94 3.0025 ;
      LAYER metal2 ;
        RECT 41.445 1.035 42.365 1.105 ;
        RECT 41.445 1.0025 41.58 1.105 ;
      LAYER via1 ;
        RECT 41.48 1.005 41.545 1.07 ;
        RECT 42.265 1.0375 42.33 1.1025 ;
      LAYER via2 ;
        RECT 41.87 1.035 41.94 1.105 ;
    END
  END rs2_sel[31]
  PIN rs2_sel[3]
    DIRECTION INPUT ;
    USE SIGNAL ;
    PORT
      LAYER metal1 ;
        RECT 10.375 1.8625 10.44 1.9975 ;
        RECT 9.59 1.895 9.655 2.03 ;
      LAYER metal3 ;
        RECT 9.56 0 9.63 3.0025 ;
      LAYER metal2 ;
        RECT 9.555 1.895 10.475 1.965 ;
        RECT 9.525 1.9275 9.69 1.9975 ;
      LAYER via1 ;
        RECT 9.59 1.93 9.655 1.995 ;
        RECT 10.375 1.8975 10.44 1.9625 ;
      LAYER via2 ;
        RECT 9.56 1.9275 9.63 1.9975 ;
    END
  END rs2_sel[3]
  PIN rs2_sel[4]
    DIRECTION INPUT ;
    USE SIGNAL ;
    PORT
      LAYER metal1 ;
        RECT 13.0325 1.8625 13.0975 1.9975 ;
        RECT 12.2475 1.895 12.3125 2.03 ;
      LAYER metal3 ;
        RECT 12.2175 0 12.2875 3.0025 ;
      LAYER metal2 ;
        RECT 12.2125 1.895 13.1325 1.965 ;
        RECT 12.1825 1.9275 12.3475 1.9975 ;
      LAYER via1 ;
        RECT 12.2475 1.93 12.3125 1.995 ;
        RECT 13.0325 1.8975 13.0975 1.9625 ;
      LAYER via2 ;
        RECT 12.2175 1.9275 12.2875 1.9975 ;
    END
  END rs2_sel[4]
  PIN rs2_sel[5]
    DIRECTION INPUT ;
    USE SIGNAL ;
    PORT
      LAYER metal1 ;
        RECT 15.69 1.8625 15.755 1.9975 ;
        RECT 14.905 1.895 14.97 2.03 ;
      LAYER metal3 ;
        RECT 14.875 0 14.945 3.0025 ;
      LAYER metal2 ;
        RECT 14.87 1.895 15.79 1.965 ;
        RECT 14.84 1.9275 15.005 1.9975 ;
      LAYER via1 ;
        RECT 14.905 1.93 14.97 1.995 ;
        RECT 15.69 1.8975 15.755 1.9625 ;
      LAYER via2 ;
        RECT 14.875 1.9275 14.945 1.9975 ;
    END
  END rs2_sel[5]
  PIN rs2_sel[6]
    DIRECTION INPUT ;
    USE SIGNAL ;
    PORT
      LAYER metal1 ;
        RECT 18.3475 1.8625 18.4125 1.9975 ;
        RECT 17.5625 1.895 17.6275 2.03 ;
      LAYER metal3 ;
        RECT 17.5325 0 17.6025 3.0025 ;
      LAYER metal2 ;
        RECT 17.5275 1.895 18.4475 1.965 ;
        RECT 17.4975 1.9275 17.6625 1.9975 ;
      LAYER via1 ;
        RECT 17.5625 1.93 17.6275 1.995 ;
        RECT 18.3475 1.8975 18.4125 1.9625 ;
      LAYER via2 ;
        RECT 17.5325 1.9275 17.6025 1.9975 ;
    END
  END rs2_sel[6]
  PIN rs2_sel[7]
    DIRECTION INPUT ;
    USE SIGNAL ;
    PORT
      LAYER metal1 ;
        RECT 21.005 1.8625 21.07 1.9975 ;
        RECT 20.22 1.895 20.285 2.03 ;
      LAYER metal3 ;
        RECT 20.19 0 20.26 3.0025 ;
      LAYER metal2 ;
        RECT 20.185 1.895 21.105 1.965 ;
        RECT 20.155 1.9275 20.32 1.9975 ;
      LAYER via1 ;
        RECT 20.22 1.93 20.285 1.995 ;
        RECT 21.005 1.8975 21.07 1.9625 ;
      LAYER via2 ;
        RECT 20.19 1.9275 20.26 1.9975 ;
    END
  END rs2_sel[7]
  PIN rs2_sel[8]
    DIRECTION INPUT ;
    USE SIGNAL ;
    PORT
      LAYER metal1 ;
        RECT 23.6625 1.8625 23.7275 1.9975 ;
        RECT 22.8775 1.895 22.9425 2.03 ;
      LAYER metal3 ;
        RECT 22.8475 0 22.9175 3.0025 ;
      LAYER metal2 ;
        RECT 22.8425 1.895 23.7625 1.965 ;
        RECT 22.8125 1.9275 22.9775 1.9975 ;
      LAYER via1 ;
        RECT 22.8775 1.93 22.9425 1.995 ;
        RECT 23.6625 1.8975 23.7275 1.9625 ;
      LAYER via2 ;
        RECT 22.8475 1.9275 22.9175 1.9975 ;
    END
  END rs2_sel[8]
  PIN rs2_sel[9]
    DIRECTION INPUT ;
    USE SIGNAL ;
    PORT
      LAYER metal1 ;
        RECT 26.32 1.8625 26.385 1.9975 ;
        RECT 25.535 1.895 25.6 2.03 ;
      LAYER metal3 ;
        RECT 25.505 0 25.575 3.0025 ;
      LAYER metal2 ;
        RECT 25.5 1.895 26.42 1.965 ;
        RECT 25.47 1.9275 25.635 1.9975 ;
      LAYER via1 ;
        RECT 25.535 1.93 25.6 1.995 ;
        RECT 26.32 1.8975 26.385 1.9625 ;
      LAYER via2 ;
        RECT 25.505 1.9275 25.575 1.9975 ;
    END
  END rs2_sel[9]
  OBS
    LAYER metal1 ;
      RECT 44.315 0.265 44.38 1.335 ;
      RECT 44.5575 0.935 44.6225 1.07 ;
      RECT 44.315 0.9725 44.6225 1.0375 ;
      RECT 44.315 0.7075 44.3825 0.8425 ;
      RECT 44.315 1.665 44.38 2.735 ;
      RECT 44.315 2.1575 44.3825 2.2925 ;
      RECT 44.5575 1.93 44.6225 2.065 ;
      RECT 44.315 1.9625 44.6225 2.0275 ;
      RECT 42.765 0.265 42.83 1.3125 ;
      RECT 42.765 0.5975 42.8325 0.7325 ;
      RECT 42.765 1.6875 42.83 2.735 ;
      RECT 42.765 2.2675 42.8325 2.4025 ;
      RECT 42.395 0.2675 42.46 1.315 ;
      RECT 42.3925 0.2825 42.46 0.4175 ;
      RECT 42.395 1.685 42.46 2.7325 ;
      RECT 42.3925 2.5825 42.46 2.7175 ;
      RECT 41.325 0.2675 41.39 1.335 ;
      RECT 41.325 0.5425 41.3925 0.6775 ;
      RECT 41.325 1.665 41.39 2.7325 ;
      RECT 41.325 2.3225 41.3925 2.4575 ;
      RECT 41.17 0.2675 41.235 1.315 ;
      RECT 41.17 0.4675 41.2375 0.6025 ;
      RECT 41.17 1.685 41.235 2.7325 ;
      RECT 41.17 2.3975 41.2375 2.5325 ;
      RECT 39.7375 0.2675 39.8025 1.315 ;
      RECT 39.735 0.2825 39.8025 0.4175 ;
      RECT 39.7375 1.685 39.8025 2.7325 ;
      RECT 39.735 2.5825 39.8025 2.7175 ;
      RECT 38.6675 0.2675 38.7325 1.335 ;
      RECT 38.6675 0.5425 38.735 0.6775 ;
      RECT 38.6675 1.665 38.7325 2.7325 ;
      RECT 38.6675 2.3225 38.735 2.4575 ;
      RECT 38.5125 0.2675 38.5775 1.315 ;
      RECT 38.5125 0.4675 38.58 0.6025 ;
      RECT 38.5125 1.685 38.5775 2.7325 ;
      RECT 38.5125 2.3975 38.58 2.5325 ;
      RECT 37.08 0.2675 37.145 1.315 ;
      RECT 37.0775 0.2825 37.145 0.4175 ;
      RECT 37.08 1.685 37.145 2.7325 ;
      RECT 37.0775 2.5825 37.145 2.7175 ;
      RECT 36.01 0.2675 36.075 1.335 ;
      RECT 36.01 0.5425 36.0775 0.6775 ;
      RECT 36.01 1.665 36.075 2.7325 ;
      RECT 36.01 2.3225 36.0775 2.4575 ;
      RECT 35.855 0.2675 35.92 1.315 ;
      RECT 35.855 0.4675 35.9225 0.6025 ;
      RECT 35.855 1.685 35.92 2.7325 ;
      RECT 35.855 2.3975 35.9225 2.5325 ;
      RECT 34.4225 0.2675 34.4875 1.315 ;
      RECT 34.42 0.2825 34.4875 0.4175 ;
      RECT 34.4225 1.685 34.4875 2.7325 ;
      RECT 34.42 2.5825 34.4875 2.7175 ;
      RECT 33.3525 0.2675 33.4175 1.335 ;
      RECT 33.3525 0.5425 33.42 0.6775 ;
      RECT 33.3525 1.665 33.4175 2.7325 ;
      RECT 33.3525 2.3225 33.42 2.4575 ;
      RECT 33.1975 0.2675 33.2625 1.315 ;
      RECT 33.1975 0.4675 33.265 0.6025 ;
      RECT 33.1975 1.685 33.2625 2.7325 ;
      RECT 33.1975 2.3975 33.265 2.5325 ;
      RECT 31.765 0.2675 31.83 1.315 ;
      RECT 31.7625 0.2825 31.83 0.4175 ;
      RECT 31.765 1.685 31.83 2.7325 ;
      RECT 31.7625 2.5825 31.83 2.7175 ;
      RECT 30.695 0.2675 30.76 1.335 ;
      RECT 30.695 0.5425 30.7625 0.6775 ;
      RECT 30.695 1.665 30.76 2.7325 ;
      RECT 30.695 2.3225 30.7625 2.4575 ;
      RECT 30.54 0.2675 30.605 1.315 ;
      RECT 30.54 0.4675 30.6075 0.6025 ;
      RECT 30.54 1.685 30.605 2.7325 ;
      RECT 30.54 2.3975 30.6075 2.5325 ;
      RECT 29.1075 0.2675 29.1725 1.315 ;
      RECT 29.105 0.2825 29.1725 0.4175 ;
      RECT 29.1075 1.685 29.1725 2.7325 ;
      RECT 29.105 2.5825 29.1725 2.7175 ;
      RECT 28.0375 0.2675 28.1025 1.335 ;
      RECT 28.0375 0.5425 28.105 0.6775 ;
      RECT 28.0375 1.665 28.1025 2.7325 ;
      RECT 28.0375 2.3225 28.105 2.4575 ;
      RECT 27.8825 0.2675 27.9475 1.315 ;
      RECT 27.8825 0.4675 27.95 0.6025 ;
      RECT 27.8825 1.685 27.9475 2.7325 ;
      RECT 27.8825 2.3975 27.95 2.5325 ;
      RECT 26.45 0.2675 26.515 1.315 ;
      RECT 26.4475 0.2825 26.515 0.4175 ;
      RECT 26.45 1.685 26.515 2.7325 ;
      RECT 26.4475 2.5825 26.515 2.7175 ;
      RECT 25.38 0.2675 25.445 1.335 ;
      RECT 25.38 0.5425 25.4475 0.6775 ;
      RECT 25.38 1.665 25.445 2.7325 ;
      RECT 25.38 2.3225 25.4475 2.4575 ;
      RECT 25.225 0.2675 25.29 1.315 ;
      RECT 25.225 0.4675 25.2925 0.6025 ;
      RECT 25.225 1.685 25.29 2.7325 ;
      RECT 25.225 2.3975 25.2925 2.5325 ;
      RECT 23.7925 0.2675 23.8575 1.315 ;
      RECT 23.79 0.2825 23.8575 0.4175 ;
      RECT 23.7925 1.685 23.8575 2.7325 ;
      RECT 23.79 2.5825 23.8575 2.7175 ;
      RECT 22.7225 0.2675 22.7875 1.335 ;
      RECT 22.7225 0.5425 22.79 0.6775 ;
      RECT 22.7225 1.665 22.7875 2.7325 ;
      RECT 22.7225 2.3225 22.79 2.4575 ;
      RECT 22.5675 0.2675 22.6325 1.315 ;
      RECT 22.5675 0.4675 22.635 0.6025 ;
      RECT 22.5675 1.685 22.6325 2.7325 ;
      RECT 22.5675 2.3975 22.635 2.5325 ;
      RECT 21.135 0.2675 21.2 1.315 ;
      RECT 21.1325 0.2825 21.2 0.4175 ;
      RECT 21.135 1.685 21.2 2.7325 ;
      RECT 21.1325 2.5825 21.2 2.7175 ;
      RECT 20.065 0.2675 20.13 1.335 ;
      RECT 20.065 0.5425 20.1325 0.6775 ;
      RECT 20.065 1.665 20.13 2.7325 ;
      RECT 20.065 2.3225 20.1325 2.4575 ;
      RECT 19.91 0.2675 19.975 1.315 ;
      RECT 19.91 0.4675 19.9775 0.6025 ;
      RECT 19.91 1.685 19.975 2.7325 ;
      RECT 19.91 2.3975 19.9775 2.5325 ;
      RECT 18.4775 0.2675 18.5425 1.315 ;
      RECT 18.475 0.2825 18.5425 0.4175 ;
      RECT 18.4775 1.685 18.5425 2.7325 ;
      RECT 18.475 2.5825 18.5425 2.7175 ;
      RECT 17.4075 0.2675 17.4725 1.335 ;
      RECT 17.4075 0.5425 17.475 0.6775 ;
      RECT 17.4075 1.665 17.4725 2.7325 ;
      RECT 17.4075 2.3225 17.475 2.4575 ;
      RECT 17.2525 0.2675 17.3175 1.315 ;
      RECT 17.2525 0.4675 17.32 0.6025 ;
      RECT 17.2525 1.685 17.3175 2.7325 ;
      RECT 17.2525 2.3975 17.32 2.5325 ;
      RECT 15.82 0.2675 15.885 1.315 ;
      RECT 15.8175 0.2825 15.885 0.4175 ;
      RECT 15.82 1.685 15.885 2.7325 ;
      RECT 15.8175 2.5825 15.885 2.7175 ;
      RECT 14.75 0.2675 14.815 1.335 ;
      RECT 14.75 0.5425 14.8175 0.6775 ;
      RECT 14.75 1.665 14.815 2.7325 ;
      RECT 14.75 2.3225 14.8175 2.4575 ;
      RECT 14.595 0.2675 14.66 1.315 ;
      RECT 14.595 0.4675 14.6625 0.6025 ;
      RECT 14.595 1.685 14.66 2.7325 ;
      RECT 14.595 2.3975 14.6625 2.5325 ;
      RECT 13.1625 0.2675 13.2275 1.315 ;
      RECT 13.16 0.2825 13.2275 0.4175 ;
      RECT 13.1625 1.685 13.2275 2.7325 ;
      RECT 13.16 2.5825 13.2275 2.7175 ;
      RECT 12.0925 0.2675 12.1575 1.335 ;
      RECT 12.0925 0.5425 12.16 0.6775 ;
      RECT 12.0925 1.665 12.1575 2.7325 ;
      RECT 12.0925 2.3225 12.16 2.4575 ;
      RECT 11.9375 0.2675 12.0025 1.315 ;
      RECT 11.9375 0.4675 12.005 0.6025 ;
      RECT 11.9375 1.685 12.0025 2.7325 ;
      RECT 11.9375 2.3975 12.005 2.5325 ;
      RECT 10.505 0.2675 10.57 1.315 ;
      RECT 10.5025 0.2825 10.57 0.4175 ;
      RECT 10.505 1.685 10.57 2.7325 ;
      RECT 10.5025 2.5825 10.57 2.7175 ;
      RECT 9.435 0.2675 9.5 1.335 ;
      RECT 9.435 0.5425 9.5025 0.6775 ;
      RECT 9.435 1.665 9.5 2.7325 ;
      RECT 9.435 2.3225 9.5025 2.4575 ;
      RECT 9.28 0.2675 9.345 1.315 ;
      RECT 9.28 0.4675 9.3475 0.6025 ;
      RECT 9.28 1.685 9.345 2.7325 ;
      RECT 9.28 2.3975 9.3475 2.5325 ;
      RECT 7.8475 0.2675 7.9125 1.315 ;
      RECT 7.845 0.2825 7.9125 0.4175 ;
      RECT 7.8475 1.685 7.9125 2.7325 ;
      RECT 7.845 2.5825 7.9125 2.7175 ;
      RECT 6.7775 0.2675 6.8425 1.335 ;
      RECT 6.7775 0.5425 6.845 0.6775 ;
      RECT 6.7775 1.665 6.8425 2.7325 ;
      RECT 6.7775 2.3225 6.845 2.4575 ;
      RECT 6.6225 0.2675 6.6875 1.315 ;
      RECT 6.6225 0.4675 6.69 0.6025 ;
      RECT 6.6225 1.685 6.6875 2.7325 ;
      RECT 6.6225 2.3975 6.69 2.5325 ;
      RECT 5.19 0.2675 5.255 1.315 ;
      RECT 5.1875 0.2825 5.255 0.4175 ;
      RECT 5.19 1.685 5.255 2.7325 ;
      RECT 5.1875 2.5825 5.255 2.7175 ;
      RECT 4.12 0.2675 4.185 1.335 ;
      RECT 4.12 0.5425 4.1875 0.6775 ;
      RECT 4.12 1.665 4.185 2.7325 ;
      RECT 4.12 2.3225 4.1875 2.4575 ;
      RECT 3.965 0.2675 4.03 1.315 ;
      RECT 3.965 0.4675 4.0325 0.6025 ;
      RECT 3.965 1.685 4.03 2.7325 ;
      RECT 3.965 2.3975 4.0325 2.5325 ;
      RECT 2.5325 0.2675 2.5975 1.315 ;
      RECT 2.53 0.2825 2.5975 0.4175 ;
      RECT 2.5325 1.685 2.5975 2.7325 ;
      RECT 2.53 2.5825 2.5975 2.7175 ;
      RECT 1.4625 0.2675 1.5275 1.335 ;
      RECT 1.4625 0.5425 1.53 0.6775 ;
      RECT 1.4625 1.665 1.5275 2.7325 ;
      RECT 1.4625 2.3225 1.53 2.4575 ;
      RECT 1.3075 0.2675 1.3725 1.315 ;
      RECT 1.3075 0.4675 1.375 0.6025 ;
      RECT 1.3075 1.685 1.3725 2.7325 ;
      RECT 1.3075 2.3975 1.375 2.5325 ;
      RECT 44.71 0.265 44.775 1.335 ;
      RECT 44.71 1.665 44.775 2.735 ;
      RECT 44.02 0.515 44.085 0.65 ;
      RECT 44.02 2.35 44.085 2.485 ;
      RECT 43.785 0.2875 43.85 1.335 ;
      RECT 43.785 1.665 43.85 2.7125 ;
      RECT 43.655 0.71 43.72 0.845 ;
      RECT 43.655 2.155 43.72 2.29 ;
      RECT 43.525 0.4725 43.59 1.2875 ;
      RECT 43.525 1.7125 43.59 2.5275 ;
      RECT 43.395 0.2875 43.46 1.335 ;
      RECT 43.395 1.665 43.46 2.7125 ;
      RECT 43.265 0.455 43.33 0.845 ;
      RECT 43.265 1.075 43.33 1.21 ;
      RECT 43.265 1.79 43.33 1.925 ;
      RECT 43.265 2.155 43.33 2.545 ;
      RECT 43.135 0.2875 43.2 1.335 ;
      RECT 43.135 1.665 43.2 2.7125 ;
      RECT 42.9325 0.835 43.0675 0.9 ;
      RECT 42.9325 2.1 43.0675 2.165 ;
      RECT 42.5625 0.835 42.6975 0.9 ;
      RECT 42.5625 2.1 42.6975 2.165 ;
      RECT 42.265 0.5775 42.33 0.7125 ;
      RECT 42.265 2.2875 42.33 2.4225 ;
      RECT 42.135 0.2675 42.2 1.315 ;
      RECT 42.135 1.685 42.2 2.7325 ;
      RECT 42.005 0.4325 42.07 0.5925 ;
      RECT 42.005 2.4075 42.07 2.5675 ;
      RECT 41.875 0.2675 41.94 1.315 ;
      RECT 41.875 1.685 41.94 2.7325 ;
      RECT 41.72 0.2675 41.785 1.3275 ;
      RECT 41.72 1.6725 41.785 2.7325 ;
      RECT 40.83 0.265 40.895 1.3125 ;
      RECT 40.83 1.6875 40.895 2.735 ;
      RECT 40.7 0.6675 40.765 0.8025 ;
      RECT 40.7 2.1975 40.765 2.3325 ;
      RECT 40.5925 0.46 40.6575 0.595 ;
      RECT 40.5925 2.405 40.6575 2.54 ;
      RECT 40.32 0.4625 40.385 1.1375 ;
      RECT 40.32 1.8625 40.385 2.5375 ;
      RECT 40.19 0.265 40.255 1.3125 ;
      RECT 40.19 1.6875 40.255 2.735 ;
      RECT 40.06 0.4625 40.125 0.5975 ;
      RECT 40.06 2.4025 40.125 2.5375 ;
      RECT 39.6075 0.5775 39.6725 0.7125 ;
      RECT 39.6075 2.2875 39.6725 2.4225 ;
      RECT 39.4775 0.2675 39.5425 1.315 ;
      RECT 39.4775 1.685 39.5425 2.7325 ;
      RECT 39.3475 0.4325 39.4125 0.5925 ;
      RECT 39.3475 2.4075 39.4125 2.5675 ;
      RECT 39.2175 0.2675 39.2825 1.315 ;
      RECT 39.2175 1.685 39.2825 2.7325 ;
      RECT 39.0625 0.2675 39.1275 1.3275 ;
      RECT 39.0625 1.6725 39.1275 2.7325 ;
      RECT 38.1725 0.265 38.2375 1.3125 ;
      RECT 38.1725 1.6875 38.2375 2.735 ;
      RECT 38.0425 0.6675 38.1075 0.8025 ;
      RECT 38.0425 2.1975 38.1075 2.3325 ;
      RECT 37.935 0.46 38 0.595 ;
      RECT 37.935 2.405 38 2.54 ;
      RECT 37.6625 0.4625 37.7275 1.1375 ;
      RECT 37.6625 1.8625 37.7275 2.5375 ;
      RECT 37.5325 0.265 37.5975 1.3125 ;
      RECT 37.5325 1.6875 37.5975 2.735 ;
      RECT 37.4025 0.4625 37.4675 0.5975 ;
      RECT 37.4025 2.4025 37.4675 2.5375 ;
      RECT 36.95 0.5775 37.015 0.7125 ;
      RECT 36.95 2.2875 37.015 2.4225 ;
      RECT 36.82 0.2675 36.885 1.315 ;
      RECT 36.82 1.685 36.885 2.7325 ;
      RECT 36.69 0.4325 36.755 0.5925 ;
      RECT 36.69 2.4075 36.755 2.5675 ;
      RECT 36.56 0.2675 36.625 1.315 ;
      RECT 36.56 1.685 36.625 2.7325 ;
      RECT 36.405 0.2675 36.47 1.3275 ;
      RECT 36.405 1.6725 36.47 2.7325 ;
      RECT 35.515 0.265 35.58 1.3125 ;
      RECT 35.515 1.6875 35.58 2.735 ;
      RECT 35.385 0.6675 35.45 0.8025 ;
      RECT 35.385 2.1975 35.45 2.3325 ;
      RECT 35.2775 0.46 35.3425 0.595 ;
      RECT 35.2775 2.405 35.3425 2.54 ;
      RECT 35.005 0.4625 35.07 1.1375 ;
      RECT 35.005 1.8625 35.07 2.5375 ;
      RECT 34.875 0.265 34.94 1.3125 ;
      RECT 34.875 1.6875 34.94 2.735 ;
      RECT 34.745 0.4625 34.81 0.5975 ;
      RECT 34.745 2.4025 34.81 2.5375 ;
      RECT 34.2925 0.5775 34.3575 0.7125 ;
      RECT 34.2925 2.2875 34.3575 2.4225 ;
      RECT 34.1625 0.2675 34.2275 1.315 ;
      RECT 34.1625 1.685 34.2275 2.7325 ;
      RECT 34.0325 0.4325 34.0975 0.5925 ;
      RECT 34.0325 2.4075 34.0975 2.5675 ;
      RECT 33.9025 0.2675 33.9675 1.315 ;
      RECT 33.9025 1.685 33.9675 2.7325 ;
      RECT 33.7475 0.2675 33.8125 1.3275 ;
      RECT 33.7475 1.6725 33.8125 2.7325 ;
      RECT 32.8575 0.265 32.9225 1.3125 ;
      RECT 32.8575 1.6875 32.9225 2.735 ;
      RECT 32.7275 0.6675 32.7925 0.8025 ;
      RECT 32.7275 2.1975 32.7925 2.3325 ;
      RECT 32.62 0.46 32.685 0.595 ;
      RECT 32.62 2.405 32.685 2.54 ;
      RECT 32.3475 0.4625 32.4125 1.1375 ;
      RECT 32.3475 1.8625 32.4125 2.5375 ;
      RECT 32.2175 0.265 32.2825 1.3125 ;
      RECT 32.2175 1.6875 32.2825 2.735 ;
      RECT 32.0875 0.4625 32.1525 0.5975 ;
      RECT 32.0875 2.4025 32.1525 2.5375 ;
      RECT 31.635 0.5775 31.7 0.7125 ;
      RECT 31.635 2.2875 31.7 2.4225 ;
      RECT 31.505 0.2675 31.57 1.315 ;
      RECT 31.505 1.685 31.57 2.7325 ;
      RECT 31.375 0.4325 31.44 0.5925 ;
      RECT 31.375 2.4075 31.44 2.5675 ;
      RECT 31.245 0.2675 31.31 1.315 ;
      RECT 31.245 1.685 31.31 2.7325 ;
      RECT 31.09 0.2675 31.155 1.3275 ;
      RECT 31.09 1.6725 31.155 2.7325 ;
      RECT 30.2 0.265 30.265 1.3125 ;
      RECT 30.2 1.6875 30.265 2.735 ;
      RECT 30.07 0.6675 30.135 0.8025 ;
      RECT 30.07 2.1975 30.135 2.3325 ;
      RECT 29.9625 0.46 30.0275 0.595 ;
      RECT 29.9625 2.405 30.0275 2.54 ;
      RECT 29.69 0.4625 29.755 1.1375 ;
      RECT 29.69 1.8625 29.755 2.5375 ;
      RECT 29.56 0.265 29.625 1.3125 ;
      RECT 29.56 1.6875 29.625 2.735 ;
      RECT 29.43 0.4625 29.495 0.5975 ;
      RECT 29.43 2.4025 29.495 2.5375 ;
      RECT 28.9775 0.5775 29.0425 0.7125 ;
      RECT 28.9775 2.2875 29.0425 2.4225 ;
      RECT 28.8475 0.2675 28.9125 1.315 ;
      RECT 28.8475 1.685 28.9125 2.7325 ;
      RECT 28.7175 0.4325 28.7825 0.5925 ;
      RECT 28.7175 2.4075 28.7825 2.5675 ;
      RECT 28.5875 0.2675 28.6525 1.315 ;
      RECT 28.5875 1.685 28.6525 2.7325 ;
      RECT 28.4325 0.2675 28.4975 1.3275 ;
      RECT 28.4325 1.6725 28.4975 2.7325 ;
      RECT 27.5425 0.265 27.6075 1.3125 ;
      RECT 27.5425 1.6875 27.6075 2.735 ;
      RECT 27.4125 0.6675 27.4775 0.8025 ;
      RECT 27.4125 2.1975 27.4775 2.3325 ;
      RECT 27.305 0.46 27.37 0.595 ;
      RECT 27.305 2.405 27.37 2.54 ;
      RECT 27.0325 0.4625 27.0975 1.1375 ;
      RECT 27.0325 1.8625 27.0975 2.5375 ;
      RECT 26.9025 0.265 26.9675 1.3125 ;
      RECT 26.9025 1.6875 26.9675 2.735 ;
      RECT 26.7725 0.4625 26.8375 0.5975 ;
      RECT 26.7725 2.4025 26.8375 2.5375 ;
      RECT 26.32 0.5775 26.385 0.7125 ;
      RECT 26.32 2.2875 26.385 2.4225 ;
      RECT 26.19 0.2675 26.255 1.315 ;
      RECT 26.19 1.685 26.255 2.7325 ;
      RECT 26.06 0.4325 26.125 0.5925 ;
      RECT 26.06 2.4075 26.125 2.5675 ;
      RECT 25.93 0.2675 25.995 1.315 ;
      RECT 25.93 1.685 25.995 2.7325 ;
      RECT 25.775 0.2675 25.84 1.3275 ;
      RECT 25.775 1.6725 25.84 2.7325 ;
      RECT 24.885 0.265 24.95 1.3125 ;
      RECT 24.885 1.6875 24.95 2.735 ;
      RECT 24.755 0.6675 24.82 0.8025 ;
      RECT 24.755 2.1975 24.82 2.3325 ;
      RECT 24.6475 0.46 24.7125 0.595 ;
      RECT 24.6475 2.405 24.7125 2.54 ;
      RECT 24.375 0.4625 24.44 1.1375 ;
      RECT 24.375 1.8625 24.44 2.5375 ;
      RECT 24.245 0.265 24.31 1.3125 ;
      RECT 24.245 1.6875 24.31 2.735 ;
      RECT 24.115 0.4625 24.18 0.5975 ;
      RECT 24.115 2.4025 24.18 2.5375 ;
      RECT 23.6625 0.5775 23.7275 0.7125 ;
      RECT 23.6625 2.2875 23.7275 2.4225 ;
      RECT 23.5325 0.2675 23.5975 1.315 ;
      RECT 23.5325 1.685 23.5975 2.7325 ;
      RECT 23.4025 0.4325 23.4675 0.5925 ;
      RECT 23.4025 2.4075 23.4675 2.5675 ;
      RECT 23.2725 0.2675 23.3375 1.315 ;
      RECT 23.2725 1.685 23.3375 2.7325 ;
      RECT 23.1175 0.2675 23.1825 1.3275 ;
      RECT 23.1175 1.6725 23.1825 2.7325 ;
      RECT 22.2275 0.265 22.2925 1.3125 ;
      RECT 22.2275 1.6875 22.2925 2.735 ;
      RECT 22.0975 0.6675 22.1625 0.8025 ;
      RECT 22.0975 2.1975 22.1625 2.3325 ;
      RECT 21.99 0.46 22.055 0.595 ;
      RECT 21.99 2.405 22.055 2.54 ;
      RECT 21.7175 0.4625 21.7825 1.1375 ;
      RECT 21.7175 1.8625 21.7825 2.5375 ;
      RECT 21.5875 0.265 21.6525 1.3125 ;
      RECT 21.5875 1.6875 21.6525 2.735 ;
      RECT 21.4575 0.4625 21.5225 0.5975 ;
      RECT 21.4575 2.4025 21.5225 2.5375 ;
      RECT 21.005 0.5775 21.07 0.7125 ;
      RECT 21.005 2.2875 21.07 2.4225 ;
      RECT 20.875 0.2675 20.94 1.315 ;
      RECT 20.875 1.685 20.94 2.7325 ;
      RECT 20.745 0.4325 20.81 0.5925 ;
      RECT 20.745 2.4075 20.81 2.5675 ;
      RECT 20.615 0.2675 20.68 1.315 ;
      RECT 20.615 1.685 20.68 2.7325 ;
      RECT 20.46 0.2675 20.525 1.3275 ;
      RECT 20.46 1.6725 20.525 2.7325 ;
      RECT 19.57 0.265 19.635 1.3125 ;
      RECT 19.57 1.6875 19.635 2.735 ;
      RECT 19.44 0.6675 19.505 0.8025 ;
      RECT 19.44 2.1975 19.505 2.3325 ;
      RECT 19.3325 0.46 19.3975 0.595 ;
      RECT 19.3325 2.405 19.3975 2.54 ;
      RECT 19.06 0.4625 19.125 1.1375 ;
      RECT 19.06 1.8625 19.125 2.5375 ;
      RECT 18.93 0.265 18.995 1.3125 ;
      RECT 18.93 1.6875 18.995 2.735 ;
      RECT 18.8 0.4625 18.865 0.5975 ;
      RECT 18.8 2.4025 18.865 2.5375 ;
      RECT 18.3475 0.5775 18.4125 0.7125 ;
      RECT 18.3475 2.2875 18.4125 2.4225 ;
      RECT 18.2175 0.2675 18.2825 1.315 ;
      RECT 18.2175 1.685 18.2825 2.7325 ;
      RECT 18.0875 0.4325 18.1525 0.5925 ;
      RECT 18.0875 2.4075 18.1525 2.5675 ;
      RECT 17.9575 0.2675 18.0225 1.315 ;
      RECT 17.9575 1.685 18.0225 2.7325 ;
      RECT 17.8025 0.2675 17.8675 1.3275 ;
      RECT 17.8025 1.6725 17.8675 2.7325 ;
      RECT 16.9125 0.265 16.9775 1.3125 ;
      RECT 16.9125 1.6875 16.9775 2.735 ;
      RECT 16.7825 0.6675 16.8475 0.8025 ;
      RECT 16.7825 2.1975 16.8475 2.3325 ;
      RECT 16.675 0.46 16.74 0.595 ;
      RECT 16.675 2.405 16.74 2.54 ;
      RECT 16.4025 0.4625 16.4675 1.1375 ;
      RECT 16.4025 1.8625 16.4675 2.5375 ;
      RECT 16.2725 0.265 16.3375 1.3125 ;
      RECT 16.2725 1.6875 16.3375 2.735 ;
      RECT 16.1425 0.4625 16.2075 0.5975 ;
      RECT 16.1425 2.4025 16.2075 2.5375 ;
      RECT 15.69 0.5775 15.755 0.7125 ;
      RECT 15.69 2.2875 15.755 2.4225 ;
      RECT 15.56 0.2675 15.625 1.315 ;
      RECT 15.56 1.685 15.625 2.7325 ;
      RECT 15.43 0.4325 15.495 0.5925 ;
      RECT 15.43 2.4075 15.495 2.5675 ;
      RECT 15.3 0.2675 15.365 1.315 ;
      RECT 15.3 1.685 15.365 2.7325 ;
      RECT 15.145 0.2675 15.21 1.3275 ;
      RECT 15.145 1.6725 15.21 2.7325 ;
      RECT 14.255 0.265 14.32 1.3125 ;
      RECT 14.255 1.6875 14.32 2.735 ;
      RECT 14.125 0.6675 14.19 0.8025 ;
      RECT 14.125 2.1975 14.19 2.3325 ;
      RECT 14.0175 0.46 14.0825 0.595 ;
      RECT 14.0175 2.405 14.0825 2.54 ;
      RECT 13.745 0.4625 13.81 1.1375 ;
      RECT 13.745 1.8625 13.81 2.5375 ;
      RECT 13.615 0.265 13.68 1.3125 ;
      RECT 13.615 1.6875 13.68 2.735 ;
      RECT 13.485 0.4625 13.55 0.5975 ;
      RECT 13.485 2.4025 13.55 2.5375 ;
      RECT 13.0325 0.5775 13.0975 0.7125 ;
      RECT 13.0325 2.2875 13.0975 2.4225 ;
      RECT 12.9025 0.2675 12.9675 1.315 ;
      RECT 12.9025 1.685 12.9675 2.7325 ;
      RECT 12.7725 0.4325 12.8375 0.5925 ;
      RECT 12.7725 2.4075 12.8375 2.5675 ;
      RECT 12.6425 0.2675 12.7075 1.315 ;
      RECT 12.6425 1.685 12.7075 2.7325 ;
      RECT 12.4875 0.2675 12.5525 1.3275 ;
      RECT 12.4875 1.6725 12.5525 2.7325 ;
      RECT 11.5975 0.265 11.6625 1.3125 ;
      RECT 11.5975 1.6875 11.6625 2.735 ;
      RECT 11.4675 0.6675 11.5325 0.8025 ;
      RECT 11.4675 2.1975 11.5325 2.3325 ;
      RECT 11.36 0.46 11.425 0.595 ;
      RECT 11.36 2.405 11.425 2.54 ;
      RECT 11.0875 0.4625 11.1525 1.1375 ;
      RECT 11.0875 1.8625 11.1525 2.5375 ;
      RECT 10.9575 0.265 11.0225 1.3125 ;
      RECT 10.9575 1.6875 11.0225 2.735 ;
      RECT 10.8275 0.4625 10.8925 0.5975 ;
      RECT 10.8275 2.4025 10.8925 2.5375 ;
      RECT 10.375 0.5775 10.44 0.7125 ;
      RECT 10.375 2.2875 10.44 2.4225 ;
      RECT 10.245 0.2675 10.31 1.315 ;
      RECT 10.245 1.685 10.31 2.7325 ;
      RECT 10.115 0.4325 10.18 0.5925 ;
      RECT 10.115 2.4075 10.18 2.5675 ;
      RECT 9.985 0.2675 10.05 1.315 ;
      RECT 9.985 1.685 10.05 2.7325 ;
      RECT 9.83 0.2675 9.895 1.3275 ;
      RECT 9.83 1.6725 9.895 2.7325 ;
      RECT 8.94 0.265 9.005 1.3125 ;
      RECT 8.94 1.6875 9.005 2.735 ;
      RECT 8.81 0.6675 8.875 0.8025 ;
      RECT 8.81 2.1975 8.875 2.3325 ;
      RECT 8.7025 0.46 8.7675 0.595 ;
      RECT 8.7025 2.405 8.7675 2.54 ;
      RECT 8.43 0.4625 8.495 1.1375 ;
      RECT 8.43 1.8625 8.495 2.5375 ;
      RECT 8.3 0.265 8.365 1.3125 ;
      RECT 8.3 1.6875 8.365 2.735 ;
      RECT 8.17 0.4625 8.235 0.5975 ;
      RECT 8.17 2.4025 8.235 2.5375 ;
      RECT 7.7175 0.5775 7.7825 0.7125 ;
      RECT 7.7175 2.2875 7.7825 2.4225 ;
      RECT 7.5875 0.2675 7.6525 1.315 ;
      RECT 7.5875 1.685 7.6525 2.7325 ;
      RECT 7.4575 0.4325 7.5225 0.5925 ;
      RECT 7.4575 2.4075 7.5225 2.5675 ;
      RECT 7.3275 0.2675 7.3925 1.315 ;
      RECT 7.3275 1.685 7.3925 2.7325 ;
      RECT 7.1725 0.2675 7.2375 1.3275 ;
      RECT 7.1725 1.6725 7.2375 2.7325 ;
      RECT 6.2825 0.265 6.3475 1.3125 ;
      RECT 6.2825 1.6875 6.3475 2.735 ;
      RECT 6.1525 0.6675 6.2175 0.8025 ;
      RECT 6.1525 2.1975 6.2175 2.3325 ;
      RECT 6.045 0.46 6.11 0.595 ;
      RECT 6.045 2.405 6.11 2.54 ;
      RECT 5.7725 0.4625 5.8375 1.1375 ;
      RECT 5.7725 1.8625 5.8375 2.5375 ;
      RECT 5.6425 0.265 5.7075 1.3125 ;
      RECT 5.6425 1.6875 5.7075 2.735 ;
      RECT 5.5125 0.4625 5.5775 0.5975 ;
      RECT 5.5125 2.4025 5.5775 2.5375 ;
      RECT 5.06 0.5775 5.125 0.7125 ;
      RECT 5.06 2.2875 5.125 2.4225 ;
      RECT 4.93 0.2675 4.995 1.315 ;
      RECT 4.93 1.685 4.995 2.7325 ;
      RECT 4.8 0.4325 4.865 0.5925 ;
      RECT 4.8 2.4075 4.865 2.5675 ;
      RECT 4.67 0.2675 4.735 1.315 ;
      RECT 4.67 1.685 4.735 2.7325 ;
      RECT 4.515 0.2675 4.58 1.3275 ;
      RECT 4.515 1.6725 4.58 2.7325 ;
      RECT 3.625 0.265 3.69 1.3125 ;
      RECT 3.625 1.6875 3.69 2.735 ;
      RECT 3.495 0.6675 3.56 0.8025 ;
      RECT 3.495 2.1975 3.56 2.3325 ;
      RECT 3.3875 0.46 3.4525 0.595 ;
      RECT 3.3875 2.405 3.4525 2.54 ;
      RECT 3.115 0.4625 3.18 1.1375 ;
      RECT 3.115 1.8625 3.18 2.5375 ;
      RECT 2.985 0.265 3.05 1.3125 ;
      RECT 2.985 1.6875 3.05 2.735 ;
      RECT 2.855 0.4625 2.92 0.5975 ;
      RECT 2.855 2.4025 2.92 2.5375 ;
      RECT 2.4025 0.5775 2.4675 0.7125 ;
      RECT 2.4025 2.2875 2.4675 2.4225 ;
      RECT 2.2725 0.2675 2.3375 1.315 ;
      RECT 2.2725 1.685 2.3375 2.7325 ;
      RECT 2.1425 0.4325 2.2075 0.5925 ;
      RECT 2.1425 2.4075 2.2075 2.5675 ;
      RECT 2.0125 0.2675 2.0775 1.315 ;
      RECT 2.0125 1.685 2.0775 2.7325 ;
      RECT 1.8575 0.2675 1.9225 1.3275 ;
      RECT 1.8575 1.6725 1.9225 2.7325 ;
      RECT 0.9675 0.265 1.0325 1.3125 ;
      RECT 0.9675 1.6875 1.0325 2.735 ;
      RECT 0.8375 0.6675 0.9025 0.8025 ;
      RECT 0.8375 2.1975 0.9025 2.3325 ;
      RECT 0.73 0.46 0.795 0.595 ;
      RECT 0.73 2.405 0.795 2.54 ;
      RECT 0.4575 0.4625 0.5225 1.1375 ;
      RECT 0.4575 1.8625 0.5225 2.5375 ;
      RECT 0.3275 0.265 0.3925 1.3125 ;
      RECT 0.3275 1.6875 0.3925 2.735 ;
      RECT 0.1975 0.4625 0.2625 0.5975 ;
      RECT 0.1975 2.4025 0.2625 2.5375 ;
    LAYER metal2 ;
      RECT 44.7075 1.1075 44.7775 1.2425 ;
      RECT 43.23 1.1075 44.7775 1.1775 ;
      RECT 43.23 1.8225 44.7775 1.8925 ;
      RECT 44.7075 1.7575 44.7775 1.8925 ;
      RECT 43.23 0.7425 43.755 0.8125 ;
      RECT 43.7175 0.74 44.4175 0.81 ;
      RECT 43.7175 2.19 44.4175 2.26 ;
      RECT 43.23 2.1875 43.755 2.2575 ;
      RECT 43.3925 0.5475 44.12 0.6175 ;
      RECT 43.3925 0.4825 43.4625 0.6175 ;
      RECT 43.3925 2.3825 43.4625 2.5175 ;
      RECT 43.3925 2.3825 44.12 2.4525 ;
      RECT 42.9325 0.8325 43.0675 0.9025 ;
      RECT 42.935 0.655 43.005 0.9025 ;
      RECT 42.765 0.5975 42.835 0.7325 ;
      RECT 42.765 0.655 43.005 0.725 ;
      RECT 42.765 2.2675 42.835 2.4025 ;
      RECT 42.765 2.295 43.025 2.365 ;
      RECT 42.955 2.0975 43.025 2.365 ;
      RECT 42.9325 2.0975 43.0675 2.1675 ;
      RECT 42.135 1.215 42.6375 1.285 ;
      RECT 42.5675 0.8325 42.6375 1.285 ;
      RECT 0.0725 1.2125 42.2225 1.2825 ;
      RECT 42.5625 0.8325 42.6975 0.9025 ;
      RECT 42.3525 2.1 42.6075 2.17 ;
      RECT 42.5625 2.0975 42.6975 2.1675 ;
      RECT 42.3525 0.3125 42.4925 0.385 ;
      RECT 39.7 0.3125 39.835 0.385 ;
      RECT 37.0425 0.3125 37.1775 0.385 ;
      RECT 34.385 0.3125 34.52 0.385 ;
      RECT 31.7275 0.3125 31.8625 0.385 ;
      RECT 29.07 0.3125 29.205 0.385 ;
      RECT 26.4125 0.3125 26.5475 0.385 ;
      RECT 23.755 0.3125 23.89 0.385 ;
      RECT 21.0975 0.3125 21.2325 0.385 ;
      RECT 18.44 0.3125 18.575 0.385 ;
      RECT 15.7825 0.3125 15.9175 0.385 ;
      RECT 13.125 0.3125 13.26 0.385 ;
      RECT 10.4675 0.3125 10.6025 0.385 ;
      RECT 7.81 0.3125 7.945 0.385 ;
      RECT 5.1525 0.3125 5.2875 0.385 ;
      RECT 2.495 0.3125 2.63 0.385 ;
      RECT 0.0725 0.3125 42.4925 0.3825 ;
      RECT 0.0725 2.6175 42.4925 2.6875 ;
      RECT 42.3575 2.615 42.4925 2.6875 ;
      RECT 39.7 2.615 39.835 2.6875 ;
      RECT 37.0425 2.615 37.1775 2.6875 ;
      RECT 34.385 2.615 34.52 2.6875 ;
      RECT 31.7275 2.615 31.8625 2.6875 ;
      RECT 29.07 2.615 29.205 2.6875 ;
      RECT 26.4125 2.615 26.5475 2.6875 ;
      RECT 23.755 2.615 23.89 2.6875 ;
      RECT 21.0975 2.615 21.2325 2.6875 ;
      RECT 18.44 2.615 18.575 2.6875 ;
      RECT 15.7825 2.615 15.9175 2.6875 ;
      RECT 13.125 2.615 13.26 2.6875 ;
      RECT 10.4675 2.615 10.6025 2.6875 ;
      RECT 7.81 2.615 7.945 2.6875 ;
      RECT 5.1525 2.615 5.2875 2.6875 ;
      RECT 2.495 2.615 2.63 2.6875 ;
      RECT 41.325 0.61 42.365 0.68 ;
      RECT 41.325 0.5425 41.395 0.68 ;
      RECT 41.325 2.32 41.395 2.4575 ;
      RECT 41.325 2.32 42.365 2.39 ;
      RECT 0.0725 1.72 42.175 1.79 ;
      RECT 41.84 1.7175 41.975 1.79 ;
      RECT 39.1825 1.7175 39.3175 1.79 ;
      RECT 36.525 1.7175 36.66 1.79 ;
      RECT 33.8675 1.7175 34.0025 1.79 ;
      RECT 31.21 1.7175 31.345 1.79 ;
      RECT 28.5525 1.7175 28.6875 1.79 ;
      RECT 25.895 1.7175 26.03 1.79 ;
      RECT 23.2375 1.7175 23.3725 1.79 ;
      RECT 20.58 1.7175 20.715 1.79 ;
      RECT 17.9225 1.7175 18.0575 1.79 ;
      RECT 15.265 1.7175 15.4 1.79 ;
      RECT 12.6075 1.7175 12.7425 1.79 ;
      RECT 9.95 1.7175 10.085 1.79 ;
      RECT 7.2925 1.7175 7.4275 1.79 ;
      RECT 4.635 1.7175 4.77 1.79 ;
      RECT 1.9775 1.7175 2.1125 1.79 ;
      RECT 38.6675 0.61 39.7075 0.68 ;
      RECT 38.6675 0.5425 38.7375 0.68 ;
      RECT 38.6675 2.32 38.7375 2.4575 ;
      RECT 38.6675 2.32 39.7075 2.39 ;
      RECT 36.01 0.61 37.05 0.68 ;
      RECT 36.01 0.5425 36.08 0.68 ;
      RECT 36.01 2.32 36.08 2.4575 ;
      RECT 36.01 2.32 37.05 2.39 ;
      RECT 33.3525 0.61 34.3925 0.68 ;
      RECT 33.3525 0.5425 33.4225 0.68 ;
      RECT 33.3525 2.32 33.4225 2.4575 ;
      RECT 33.3525 2.32 34.3925 2.39 ;
      RECT 30.695 0.61 31.735 0.68 ;
      RECT 30.695 0.5425 30.765 0.68 ;
      RECT 30.695 2.32 30.765 2.4575 ;
      RECT 30.695 2.32 31.735 2.39 ;
      RECT 28.0375 0.61 29.0775 0.68 ;
      RECT 28.0375 0.5425 28.1075 0.68 ;
      RECT 28.0375 2.32 28.1075 2.4575 ;
      RECT 28.0375 2.32 29.0775 2.39 ;
      RECT 25.38 0.61 26.42 0.68 ;
      RECT 25.38 0.5425 25.45 0.68 ;
      RECT 25.38 2.32 25.45 2.4575 ;
      RECT 25.38 2.32 26.42 2.39 ;
      RECT 22.7225 0.61 23.7625 0.68 ;
      RECT 22.7225 0.5425 22.7925 0.68 ;
      RECT 22.7225 2.32 22.7925 2.4575 ;
      RECT 22.7225 2.32 23.7625 2.39 ;
      RECT 20.065 0.61 21.105 0.68 ;
      RECT 20.065 0.5425 20.135 0.68 ;
      RECT 20.065 2.32 20.135 2.4575 ;
      RECT 20.065 2.32 21.105 2.39 ;
      RECT 17.4075 0.61 18.4475 0.68 ;
      RECT 17.4075 0.5425 17.4775 0.68 ;
      RECT 17.4075 2.32 17.4775 2.4575 ;
      RECT 17.4075 2.32 18.4475 2.39 ;
      RECT 14.75 0.61 15.79 0.68 ;
      RECT 14.75 0.5425 14.82 0.68 ;
      RECT 14.75 2.32 14.82 2.4575 ;
      RECT 14.75 2.32 15.79 2.39 ;
      RECT 12.0925 0.61 13.1325 0.68 ;
      RECT 12.0925 0.5425 12.1625 0.68 ;
      RECT 12.0925 2.32 12.1625 2.4575 ;
      RECT 12.0925 2.32 13.1325 2.39 ;
      RECT 9.435 0.61 10.475 0.68 ;
      RECT 9.435 0.5425 9.505 0.68 ;
      RECT 9.435 2.32 9.505 2.4575 ;
      RECT 9.435 2.32 10.475 2.39 ;
      RECT 6.7775 0.61 7.8175 0.68 ;
      RECT 6.7775 0.5425 6.8475 0.68 ;
      RECT 6.7775 2.32 6.8475 2.4575 ;
      RECT 6.7775 2.32 7.8175 2.39 ;
      RECT 4.12 0.61 5.16 0.68 ;
      RECT 4.12 0.5425 4.19 0.68 ;
      RECT 4.12 2.32 4.19 2.4575 ;
      RECT 4.12 2.32 5.16 2.39 ;
      RECT 1.4625 0.61 2.5025 0.68 ;
      RECT 1.4625 0.5425 1.5325 0.68 ;
      RECT 1.4625 2.32 1.5325 2.4575 ;
      RECT 1.4625 2.32 2.5025 2.39 ;
      RECT 42.095 0.895 42.235 0.965 ;
      RECT 42.095 2.035 42.235 2.105 ;
      RECT 41.685 0.465 42.105 0.535 ;
      RECT 41.685 2.465 42.105 2.535 ;
      RECT 41.17 0.46 41.24 0.6025 ;
      RECT 41.17 2.3975 41.24 2.54 ;
      RECT 40.5575 0.4925 40.93 0.5625 ;
      RECT 40.79 0.895 40.93 0.965 ;
      RECT 40.79 2.035 40.93 2.105 ;
      RECT 40.5575 2.4375 40.93 2.5075 ;
      RECT 40.155 0.7 40.8 0.77 ;
      RECT 40.155 2.23 40.8 2.3 ;
      RECT 40.025 0.495 40.42 0.565 ;
      RECT 40.025 2.435 40.42 2.505 ;
      RECT 39.4375 0.895 39.5775 0.965 ;
      RECT 39.4375 2.035 39.5775 2.105 ;
      RECT 39.0275 0.465 39.4475 0.535 ;
      RECT 39.0275 2.465 39.4475 2.535 ;
      RECT 38.5125 0.46 38.5825 0.6025 ;
      RECT 38.5125 2.3975 38.5825 2.54 ;
      RECT 37.9 0.4925 38.2725 0.5625 ;
      RECT 38.1325 0.895 38.2725 0.965 ;
      RECT 38.1325 2.035 38.2725 2.105 ;
      RECT 37.9 2.4375 38.2725 2.5075 ;
      RECT 37.4975 0.7 38.1425 0.77 ;
      RECT 37.4975 2.23 38.1425 2.3 ;
      RECT 37.3675 0.495 37.7625 0.565 ;
      RECT 37.3675 2.435 37.7625 2.505 ;
      RECT 36.78 0.895 36.92 0.965 ;
      RECT 36.78 2.035 36.92 2.105 ;
      RECT 36.37 0.465 36.79 0.535 ;
      RECT 36.37 2.465 36.79 2.535 ;
      RECT 35.855 0.46 35.925 0.6025 ;
      RECT 35.855 2.3975 35.925 2.54 ;
      RECT 35.2425 0.4925 35.615 0.5625 ;
      RECT 35.475 0.895 35.615 0.965 ;
      RECT 35.475 2.035 35.615 2.105 ;
      RECT 35.2425 2.4375 35.615 2.5075 ;
      RECT 34.84 0.7 35.485 0.77 ;
      RECT 34.84 2.23 35.485 2.3 ;
      RECT 34.71 0.495 35.105 0.565 ;
      RECT 34.71 2.435 35.105 2.505 ;
      RECT 34.1225 0.895 34.2625 0.965 ;
      RECT 34.1225 2.035 34.2625 2.105 ;
      RECT 33.7125 0.465 34.1325 0.535 ;
      RECT 33.7125 2.465 34.1325 2.535 ;
      RECT 33.1975 0.46 33.2675 0.6025 ;
      RECT 33.1975 2.3975 33.2675 2.54 ;
      RECT 32.585 0.4925 32.9575 0.5625 ;
      RECT 32.8175 0.895 32.9575 0.965 ;
      RECT 32.8175 2.035 32.9575 2.105 ;
      RECT 32.585 2.4375 32.9575 2.5075 ;
      RECT 32.1825 0.7 32.8275 0.77 ;
      RECT 32.1825 2.23 32.8275 2.3 ;
      RECT 32.0525 0.495 32.4475 0.565 ;
      RECT 32.0525 2.435 32.4475 2.505 ;
      RECT 31.465 0.895 31.605 0.965 ;
      RECT 31.465 2.035 31.605 2.105 ;
      RECT 31.055 0.465 31.475 0.535 ;
      RECT 31.055 2.465 31.475 2.535 ;
      RECT 30.54 0.46 30.61 0.6025 ;
      RECT 30.54 2.3975 30.61 2.54 ;
      RECT 29.9275 0.4925 30.3 0.5625 ;
      RECT 30.16 0.895 30.3 0.965 ;
      RECT 30.16 2.035 30.3 2.105 ;
      RECT 29.9275 2.4375 30.3 2.5075 ;
      RECT 29.525 0.7 30.17 0.77 ;
      RECT 29.525 2.23 30.17 2.3 ;
      RECT 29.395 0.495 29.79 0.565 ;
      RECT 29.395 2.435 29.79 2.505 ;
      RECT 28.8075 0.895 28.9475 0.965 ;
      RECT 28.8075 2.035 28.9475 2.105 ;
      RECT 28.3975 0.465 28.8175 0.535 ;
      RECT 28.3975 2.465 28.8175 2.535 ;
      RECT 27.8825 0.46 27.9525 0.6025 ;
      RECT 27.8825 2.3975 27.9525 2.54 ;
      RECT 27.27 0.4925 27.6425 0.5625 ;
      RECT 27.5025 0.895 27.6425 0.965 ;
      RECT 27.5025 2.035 27.6425 2.105 ;
      RECT 27.27 2.4375 27.6425 2.5075 ;
      RECT 26.8675 0.7 27.5125 0.77 ;
      RECT 26.8675 2.23 27.5125 2.3 ;
      RECT 26.7375 0.495 27.1325 0.565 ;
      RECT 26.7375 2.435 27.1325 2.505 ;
      RECT 26.15 0.895 26.29 0.965 ;
      RECT 26.15 2.035 26.29 2.105 ;
      RECT 25.74 0.465 26.16 0.535 ;
      RECT 25.74 2.465 26.16 2.535 ;
      RECT 25.225 0.46 25.295 0.6025 ;
      RECT 25.225 2.3975 25.295 2.54 ;
      RECT 24.6125 0.4925 24.985 0.5625 ;
      RECT 24.845 0.895 24.985 0.965 ;
      RECT 24.845 2.035 24.985 2.105 ;
      RECT 24.6125 2.4375 24.985 2.5075 ;
      RECT 24.21 0.7 24.855 0.77 ;
      RECT 24.21 2.23 24.855 2.3 ;
      RECT 24.08 0.495 24.475 0.565 ;
      RECT 24.08 2.435 24.475 2.505 ;
      RECT 23.4925 0.895 23.6325 0.965 ;
      RECT 23.4925 2.035 23.6325 2.105 ;
      RECT 23.0825 0.465 23.5025 0.535 ;
      RECT 23.0825 2.465 23.5025 2.535 ;
      RECT 22.5675 0.46 22.6375 0.6025 ;
      RECT 22.5675 2.3975 22.6375 2.54 ;
      RECT 21.955 0.4925 22.3275 0.5625 ;
      RECT 22.1875 0.895 22.3275 0.965 ;
      RECT 22.1875 2.035 22.3275 2.105 ;
      RECT 21.955 2.4375 22.3275 2.5075 ;
      RECT 21.5525 0.7 22.1975 0.77 ;
      RECT 21.5525 2.23 22.1975 2.3 ;
      RECT 21.4225 0.495 21.8175 0.565 ;
      RECT 21.4225 2.435 21.8175 2.505 ;
      RECT 20.835 0.895 20.975 0.965 ;
      RECT 20.835 2.035 20.975 2.105 ;
      RECT 20.425 0.465 20.845 0.535 ;
      RECT 20.425 2.465 20.845 2.535 ;
      RECT 19.91 0.46 19.98 0.6025 ;
      RECT 19.91 2.3975 19.98 2.54 ;
      RECT 19.2975 0.4925 19.67 0.5625 ;
      RECT 19.53 0.895 19.67 0.965 ;
      RECT 19.53 2.035 19.67 2.105 ;
      RECT 19.2975 2.4375 19.67 2.5075 ;
      RECT 18.895 0.7 19.54 0.77 ;
      RECT 18.895 2.23 19.54 2.3 ;
      RECT 18.765 0.495 19.16 0.565 ;
      RECT 18.765 2.435 19.16 2.505 ;
      RECT 18.1775 0.895 18.3175 0.965 ;
      RECT 18.1775 2.035 18.3175 2.105 ;
      RECT 17.7675 0.465 18.1875 0.535 ;
      RECT 17.7675 2.465 18.1875 2.535 ;
      RECT 17.2525 0.46 17.3225 0.6025 ;
      RECT 17.2525 2.3975 17.3225 2.54 ;
      RECT 16.64 0.4925 17.0125 0.5625 ;
      RECT 16.8725 0.895 17.0125 0.965 ;
      RECT 16.8725 2.035 17.0125 2.105 ;
      RECT 16.64 2.4375 17.0125 2.5075 ;
      RECT 16.2375 0.7 16.8825 0.77 ;
      RECT 16.2375 2.23 16.8825 2.3 ;
      RECT 16.1075 0.495 16.5025 0.565 ;
      RECT 16.1075 2.435 16.5025 2.505 ;
      RECT 15.52 0.895 15.66 0.965 ;
      RECT 15.52 2.035 15.66 2.105 ;
      RECT 15.11 0.465 15.53 0.535 ;
      RECT 15.11 2.465 15.53 2.535 ;
      RECT 14.595 0.46 14.665 0.6025 ;
      RECT 14.595 2.3975 14.665 2.54 ;
      RECT 13.9825 0.4925 14.355 0.5625 ;
      RECT 14.215 0.895 14.355 0.965 ;
      RECT 14.215 2.035 14.355 2.105 ;
      RECT 13.9825 2.4375 14.355 2.5075 ;
      RECT 13.58 0.7 14.225 0.77 ;
      RECT 13.58 2.23 14.225 2.3 ;
      RECT 13.45 0.495 13.845 0.565 ;
      RECT 13.45 2.435 13.845 2.505 ;
      RECT 12.8625 0.895 13.0025 0.965 ;
      RECT 12.8625 2.035 13.0025 2.105 ;
      RECT 12.4525 0.465 12.8725 0.535 ;
      RECT 12.4525 2.465 12.8725 2.535 ;
      RECT 11.9375 0.46 12.0075 0.6025 ;
      RECT 11.9375 2.3975 12.0075 2.54 ;
      RECT 11.325 0.4925 11.6975 0.5625 ;
      RECT 11.5575 0.895 11.6975 0.965 ;
      RECT 11.5575 2.035 11.6975 2.105 ;
      RECT 11.325 2.4375 11.6975 2.5075 ;
      RECT 10.9225 0.7 11.5675 0.77 ;
      RECT 10.9225 2.23 11.5675 2.3 ;
      RECT 10.7925 0.495 11.1875 0.565 ;
      RECT 10.7925 2.435 11.1875 2.505 ;
      RECT 10.205 0.895 10.345 0.965 ;
      RECT 10.205 2.035 10.345 2.105 ;
      RECT 9.795 0.465 10.215 0.535 ;
      RECT 9.795 2.465 10.215 2.535 ;
      RECT 9.28 0.46 9.35 0.6025 ;
      RECT 9.28 2.3975 9.35 2.54 ;
      RECT 8.6675 0.4925 9.04 0.5625 ;
      RECT 8.9 0.895 9.04 0.965 ;
      RECT 8.9 2.035 9.04 2.105 ;
      RECT 8.6675 2.4375 9.04 2.5075 ;
      RECT 8.265 0.7 8.91 0.77 ;
      RECT 8.265 2.23 8.91 2.3 ;
      RECT 8.135 0.495 8.53 0.565 ;
      RECT 8.135 2.435 8.53 2.505 ;
      RECT 7.5475 0.895 7.6875 0.965 ;
      RECT 7.5475 2.035 7.6875 2.105 ;
      RECT 7.1375 0.465 7.5575 0.535 ;
      RECT 7.1375 2.465 7.5575 2.535 ;
      RECT 6.6225 0.46 6.6925 0.6025 ;
      RECT 6.6225 2.3975 6.6925 2.54 ;
      RECT 6.01 0.4925 6.3825 0.5625 ;
      RECT 6.2425 0.895 6.3825 0.965 ;
      RECT 6.2425 2.035 6.3825 2.105 ;
      RECT 6.01 2.4375 6.3825 2.5075 ;
      RECT 5.6075 0.7 6.2525 0.77 ;
      RECT 5.6075 2.23 6.2525 2.3 ;
      RECT 5.4775 0.495 5.8725 0.565 ;
      RECT 5.4775 2.435 5.8725 2.505 ;
      RECT 4.89 0.895 5.03 0.965 ;
      RECT 4.89 2.035 5.03 2.105 ;
      RECT 4.48 0.465 4.9 0.535 ;
      RECT 4.48 2.465 4.9 2.535 ;
      RECT 3.965 0.46 4.035 0.6025 ;
      RECT 3.965 2.3975 4.035 2.54 ;
      RECT 3.3525 0.4925 3.725 0.5625 ;
      RECT 3.585 0.895 3.725 0.965 ;
      RECT 3.585 2.035 3.725 2.105 ;
      RECT 3.3525 2.4375 3.725 2.5075 ;
      RECT 2.95 0.7 3.595 0.77 ;
      RECT 2.95 2.23 3.595 2.3 ;
      RECT 2.82 0.495 3.215 0.565 ;
      RECT 2.82 2.435 3.215 2.505 ;
      RECT 2.2325 0.895 2.3725 0.965 ;
      RECT 2.2325 2.035 2.3725 2.105 ;
      RECT 1.8225 0.465 2.2425 0.535 ;
      RECT 1.8225 2.465 2.2425 2.535 ;
      RECT 1.3075 0.46 1.3775 0.6025 ;
      RECT 1.3075 2.3975 1.3775 2.54 ;
      RECT 0.695 0.4925 1.0675 0.5625 ;
      RECT 0.9275 0.895 1.0675 0.965 ;
      RECT 0.9275 2.035 1.0675 2.105 ;
      RECT 0.695 2.4375 1.0675 2.5075 ;
      RECT 0.2925 0.7 0.9375 0.77 ;
      RECT 0.2925 2.23 0.9375 2.3 ;
      RECT 0.1625 0.495 0.5575 0.565 ;
      RECT 0.1625 2.435 0.5575 2.505 ;
    LAYER metal3 ;
      RECT 42.3875 0.28 42.4575 2.7225 ;
      RECT 42.13 0.86 42.2 1 ;
      RECT 42.13 2 42.2 2.14 ;
      RECT 42.07 1.1775 42.14 1.825 ;
      RECT 41.17 0.46 41.24 0.6 ;
      RECT 41.17 2.4 41.24 2.54 ;
      RECT 40.825 0.86 40.895 1 ;
      RECT 40.825 2 40.895 2.14 ;
      RECT 40.315 0.46 40.385 0.6 ;
      RECT 40.315 2.4 40.385 2.54 ;
      RECT 39.4725 0.86 39.5425 1 ;
      RECT 39.4725 2 39.5425 2.14 ;
      RECT 38.5125 0.46 38.5825 0.6 ;
      RECT 38.5125 2.4 38.5825 2.54 ;
      RECT 38.1675 0.86 38.2375 1 ;
      RECT 38.1675 2 38.2375 2.14 ;
      RECT 37.6575 0.46 37.7275 0.6 ;
      RECT 37.6575 2.4 37.7275 2.54 ;
      RECT 36.815 0.86 36.885 1 ;
      RECT 36.815 2 36.885 2.14 ;
      RECT 35.855 0.46 35.925 0.6 ;
      RECT 35.855 2.4 35.925 2.54 ;
      RECT 35.51 0.86 35.58 1 ;
      RECT 35.51 2 35.58 2.14 ;
      RECT 35 0.46 35.07 0.6 ;
      RECT 35 2.4 35.07 2.54 ;
      RECT 34.1575 0.86 34.2275 1 ;
      RECT 34.1575 2 34.2275 2.14 ;
      RECT 33.1975 0.46 33.2675 0.6 ;
      RECT 33.1975 2.4 33.2675 2.54 ;
      RECT 32.8525 0.86 32.9225 1 ;
      RECT 32.8525 2 32.9225 2.14 ;
      RECT 32.3425 0.46 32.4125 0.6 ;
      RECT 32.3425 2.4 32.4125 2.54 ;
      RECT 31.5 0.86 31.57 1 ;
      RECT 31.5 2 31.57 2.14 ;
      RECT 30.54 0.46 30.61 0.6 ;
      RECT 30.54 2.4 30.61 2.54 ;
      RECT 30.195 0.86 30.265 1 ;
      RECT 30.195 2 30.265 2.14 ;
      RECT 29.685 0.46 29.755 0.6 ;
      RECT 29.685 2.4 29.755 2.54 ;
      RECT 28.8425 0.86 28.9125 1 ;
      RECT 28.8425 2 28.9125 2.14 ;
      RECT 27.8825 0.46 27.9525 0.6 ;
      RECT 27.8825 2.4 27.9525 2.54 ;
      RECT 27.5375 0.86 27.6075 1 ;
      RECT 27.5375 2 27.6075 2.14 ;
      RECT 27.0275 0.46 27.0975 0.6 ;
      RECT 27.0275 2.4 27.0975 2.54 ;
      RECT 26.185 0.86 26.255 1 ;
      RECT 26.185 2 26.255 2.14 ;
      RECT 25.225 0.46 25.295 0.6 ;
      RECT 25.225 2.4 25.295 2.54 ;
      RECT 24.88 0.86 24.95 1 ;
      RECT 24.88 2 24.95 2.14 ;
      RECT 24.37 0.46 24.44 0.6 ;
      RECT 24.37 2.4 24.44 2.54 ;
      RECT 23.5275 0.86 23.5975 1 ;
      RECT 23.5275 2 23.5975 2.14 ;
      RECT 22.5675 0.46 22.6375 0.6 ;
      RECT 22.5675 2.4 22.6375 2.54 ;
      RECT 22.2225 0.86 22.2925 1 ;
      RECT 22.2225 2 22.2925 2.14 ;
      RECT 21.7125 0.46 21.7825 0.6 ;
      RECT 21.7125 2.4 21.7825 2.54 ;
      RECT 20.87 0.86 20.94 1 ;
      RECT 20.87 2 20.94 2.14 ;
      RECT 19.91 0.46 19.98 0.6 ;
      RECT 19.91 2.4 19.98 2.54 ;
      RECT 19.565 0.86 19.635 1 ;
      RECT 19.565 2 19.635 2.14 ;
      RECT 19.055 0.46 19.125 0.6 ;
      RECT 19.055 2.4 19.125 2.54 ;
      RECT 18.2125 0.86 18.2825 1 ;
      RECT 18.2125 2 18.2825 2.14 ;
      RECT 17.2525 0.46 17.3225 0.6 ;
      RECT 17.2525 2.4 17.3225 2.54 ;
      RECT 16.9075 0.86 16.9775 1 ;
      RECT 16.9075 2 16.9775 2.14 ;
      RECT 16.3975 0.46 16.4675 0.6 ;
      RECT 16.3975 2.4 16.4675 2.54 ;
      RECT 15.555 0.86 15.625 1 ;
      RECT 15.555 2 15.625 2.14 ;
      RECT 14.595 0.46 14.665 0.6 ;
      RECT 14.595 2.4 14.665 2.54 ;
      RECT 14.25 0.86 14.32 1 ;
      RECT 14.25 2 14.32 2.14 ;
      RECT 13.74 0.46 13.81 0.6 ;
      RECT 13.74 2.4 13.81 2.54 ;
      RECT 12.8975 0.86 12.9675 1 ;
      RECT 12.8975 2 12.9675 2.14 ;
      RECT 11.9375 0.46 12.0075 0.6 ;
      RECT 11.9375 2.4 12.0075 2.54 ;
      RECT 11.5925 0.86 11.6625 1 ;
      RECT 11.5925 2 11.6625 2.14 ;
      RECT 11.0825 0.46 11.1525 0.6 ;
      RECT 11.0825 2.4 11.1525 2.54 ;
      RECT 10.24 0.86 10.31 1 ;
      RECT 10.24 2 10.31 2.14 ;
      RECT 9.28 0.46 9.35 0.6 ;
      RECT 9.28 2.4 9.35 2.54 ;
      RECT 8.935 0.86 9.005 1 ;
      RECT 8.935 2 9.005 2.14 ;
      RECT 8.425 0.46 8.495 0.6 ;
      RECT 8.425 2.4 8.495 2.54 ;
      RECT 7.5825 0.86 7.6525 1 ;
      RECT 7.5825 2 7.6525 2.14 ;
      RECT 6.6225 0.46 6.6925 0.6 ;
      RECT 6.6225 2.4 6.6925 2.54 ;
      RECT 6.2775 0.86 6.3475 1 ;
      RECT 6.2775 2 6.3475 2.14 ;
      RECT 5.7675 0.46 5.8375 0.6 ;
      RECT 5.7675 2.4 5.8375 2.54 ;
      RECT 4.925 0.86 4.995 1 ;
      RECT 4.925 2 4.995 2.14 ;
      RECT 3.965 0.46 4.035 0.6 ;
      RECT 3.965 2.4 4.035 2.54 ;
      RECT 3.62 0.86 3.69 1 ;
      RECT 3.62 2 3.69 2.14 ;
      RECT 3.11 0.46 3.18 0.6 ;
      RECT 3.11 2.4 3.18 2.54 ;
      RECT 2.2675 0.86 2.3375 1 ;
      RECT 2.2675 2 2.3375 2.14 ;
      RECT 1.3075 0.46 1.3775 0.6 ;
      RECT 1.3075 2.4 1.3775 2.54 ;
      RECT 0.9625 0.86 1.0325 1 ;
      RECT 0.9625 2 1.0325 2.14 ;
      RECT 0.4525 0.46 0.5225 0.6 ;
      RECT 0.4525 2.4 0.5225 2.54 ;
    LAYER metal4 ;
      RECT 40.79 0.86 42.235 1 ;
      RECT 40.79 2 42.235 2.14 ;
      RECT 40.28 0.46 41.275 0.6 ;
      RECT 40.28 2.4 41.275 2.54 ;
      RECT 38.1325 0.86 39.5775 1 ;
      RECT 38.1325 2 39.5775 2.14 ;
      RECT 37.6225 0.46 38.6175 0.6 ;
      RECT 37.6225 2.4 38.6175 2.54 ;
      RECT 35.475 0.86 36.92 1 ;
      RECT 35.475 2 36.92 2.14 ;
      RECT 34.965 0.46 35.96 0.6 ;
      RECT 34.965 2.4 35.96 2.54 ;
      RECT 32.8175 0.86 34.2625 1 ;
      RECT 32.8175 2 34.2625 2.14 ;
      RECT 32.3075 0.46 33.3025 0.6 ;
      RECT 32.3075 2.4 33.3025 2.54 ;
      RECT 30.16 0.86 31.605 1 ;
      RECT 30.16 2 31.605 2.14 ;
      RECT 29.65 0.46 30.645 0.6 ;
      RECT 29.65 2.4 30.645 2.54 ;
      RECT 27.5025 0.86 28.9475 1 ;
      RECT 27.5025 2 28.9475 2.14 ;
      RECT 26.9925 0.46 27.9875 0.6 ;
      RECT 26.9925 2.4 27.9875 2.54 ;
      RECT 24.845 0.86 26.29 1 ;
      RECT 24.845 2 26.29 2.14 ;
      RECT 24.335 0.46 25.33 0.6 ;
      RECT 24.335 2.4 25.33 2.54 ;
      RECT 22.1875 0.86 23.6325 1 ;
      RECT 22.1875 2 23.6325 2.14 ;
      RECT 21.6775 0.46 22.6725 0.6 ;
      RECT 21.6775 2.4 22.6725 2.54 ;
      RECT 19.53 0.86 20.975 1 ;
      RECT 19.53 2 20.975 2.14 ;
      RECT 19.02 0.46 20.015 0.6 ;
      RECT 19.02 2.4 20.015 2.54 ;
      RECT 16.8725 0.86 18.3175 1 ;
      RECT 16.8725 2 18.3175 2.14 ;
      RECT 16.3625 0.46 17.3575 0.6 ;
      RECT 16.3625 2.4 17.3575 2.54 ;
      RECT 14.215 0.86 15.66 1 ;
      RECT 14.215 2 15.66 2.14 ;
      RECT 13.705 0.46 14.7 0.6 ;
      RECT 13.705 2.4 14.7 2.54 ;
      RECT 11.5575 0.86 13.0025 1 ;
      RECT 11.5575 2 13.0025 2.14 ;
      RECT 11.0475 0.46 12.0425 0.6 ;
      RECT 11.0475 2.4 12.0425 2.54 ;
      RECT 8.9 0.86 10.345 1 ;
      RECT 8.9 2 10.345 2.14 ;
      RECT 8.39 0.46 9.385 0.6 ;
      RECT 8.39 2.4 9.385 2.54 ;
      RECT 6.2425 0.86 7.6875 1 ;
      RECT 6.2425 2 7.6875 2.14 ;
      RECT 5.7325 0.46 6.7275 0.6 ;
      RECT 5.7325 2.4 6.7275 2.54 ;
      RECT 3.585 0.86 5.03 1 ;
      RECT 3.585 2 5.03 2.14 ;
      RECT 3.075 0.46 4.07 0.6 ;
      RECT 3.075 2.4 4.07 2.54 ;
      RECT 0.9275 0.86 2.3725 1 ;
      RECT 0.9275 2 2.3725 2.14 ;
      RECT 0.4175 0.46 1.4125 0.6 ;
      RECT 0.4175 2.4 1.4125 2.54 ;
    LAYER via1 ;
      RECT 44.71 1.1425 44.775 1.2075 ;
      RECT 44.71 1.7925 44.775 1.8575 ;
      RECT 44.3175 0.7425 44.3825 0.8075 ;
      RECT 44.3175 2.1925 44.3825 2.2575 ;
      RECT 44.02 0.55 44.085 0.615 ;
      RECT 44.02 2.385 44.085 2.45 ;
      RECT 43.655 0.745 43.72 0.81 ;
      RECT 43.655 2.19 43.72 2.255 ;
      RECT 43.525 1.11 43.59 1.175 ;
      RECT 43.525 1.825 43.59 1.89 ;
      RECT 43.395 0.5175 43.46 0.5825 ;
      RECT 43.395 2.4175 43.46 2.4825 ;
      RECT 43.265 0.745 43.33 0.81 ;
      RECT 43.265 1.11 43.33 1.175 ;
      RECT 43.265 1.825 43.33 1.89 ;
      RECT 43.265 2.19 43.33 2.255 ;
      RECT 42.9675 0.835 43.0325 0.9 ;
      RECT 42.9675 2.1 43.0325 2.165 ;
      RECT 42.7675 0.6325 42.8325 0.6975 ;
      RECT 42.7675 2.3025 42.8325 2.3675 ;
      RECT 42.5975 0.835 42.6625 0.9 ;
      RECT 42.5975 2.1 42.6625 2.165 ;
      RECT 42.3925 0.3175 42.4575 0.3825 ;
      RECT 42.3925 2.6175 42.4575 2.6825 ;
      RECT 42.265 0.6125 42.33 0.6775 ;
      RECT 42.265 2.3225 42.33 2.3875 ;
      RECT 42.135 0.8975 42.2 0.9625 ;
      RECT 42.135 2.0375 42.2 2.1025 ;
      RECT 42.005 0.4675 42.07 0.5325 ;
      RECT 42.005 2.4675 42.07 2.5325 ;
      RECT 41.875 1.215 41.94 1.28 ;
      RECT 41.875 1.72 41.94 1.785 ;
      RECT 41.72 0.4675 41.785 0.5325 ;
      RECT 41.72 2.4675 41.785 2.5325 ;
      RECT 41.3275 0.5775 41.3925 0.6425 ;
      RECT 41.3275 2.3575 41.3925 2.4225 ;
      RECT 41.1725 0.5025 41.2375 0.5675 ;
      RECT 41.1725 2.4325 41.2375 2.4975 ;
      RECT 40.83 0.495 40.895 0.56 ;
      RECT 40.83 0.8975 40.895 0.9625 ;
      RECT 40.83 2.0375 40.895 2.1025 ;
      RECT 40.83 2.44 40.895 2.505 ;
      RECT 40.7 0.7025 40.765 0.7675 ;
      RECT 40.7 2.2325 40.765 2.2975 ;
      RECT 40.5925 0.495 40.6575 0.56 ;
      RECT 40.5925 2.44 40.6575 2.505 ;
      RECT 40.32 0.4975 40.385 0.5625 ;
      RECT 40.32 2.4375 40.385 2.5025 ;
      RECT 40.19 0.7025 40.255 0.7675 ;
      RECT 40.19 2.2325 40.255 2.2975 ;
      RECT 40.06 0.4975 40.125 0.5625 ;
      RECT 40.06 2.4375 40.125 2.5025 ;
      RECT 39.735 0.3175 39.8 0.3825 ;
      RECT 39.735 2.6175 39.8 2.6825 ;
      RECT 39.6075 0.6125 39.6725 0.6775 ;
      RECT 39.6075 2.3225 39.6725 2.3875 ;
      RECT 39.4775 0.8975 39.5425 0.9625 ;
      RECT 39.4775 2.0375 39.5425 2.1025 ;
      RECT 39.3475 0.4675 39.4125 0.5325 ;
      RECT 39.3475 2.4675 39.4125 2.5325 ;
      RECT 39.2175 1.215 39.2825 1.28 ;
      RECT 39.2175 1.72 39.2825 1.785 ;
      RECT 39.0625 0.4675 39.1275 0.5325 ;
      RECT 39.0625 2.4675 39.1275 2.5325 ;
      RECT 38.67 0.5775 38.735 0.6425 ;
      RECT 38.67 2.3575 38.735 2.4225 ;
      RECT 38.515 0.5025 38.58 0.5675 ;
      RECT 38.515 2.4325 38.58 2.4975 ;
      RECT 38.1725 0.495 38.2375 0.56 ;
      RECT 38.1725 0.8975 38.2375 0.9625 ;
      RECT 38.1725 2.0375 38.2375 2.1025 ;
      RECT 38.1725 2.44 38.2375 2.505 ;
      RECT 38.0425 0.7025 38.1075 0.7675 ;
      RECT 38.0425 2.2325 38.1075 2.2975 ;
      RECT 37.935 0.495 38 0.56 ;
      RECT 37.935 2.44 38 2.505 ;
      RECT 37.6625 0.4975 37.7275 0.5625 ;
      RECT 37.6625 2.4375 37.7275 2.5025 ;
      RECT 37.5325 0.7025 37.5975 0.7675 ;
      RECT 37.5325 2.2325 37.5975 2.2975 ;
      RECT 37.4025 0.4975 37.4675 0.5625 ;
      RECT 37.4025 2.4375 37.4675 2.5025 ;
      RECT 37.0775 0.3175 37.1425 0.3825 ;
      RECT 37.0775 2.6175 37.1425 2.6825 ;
      RECT 36.95 0.6125 37.015 0.6775 ;
      RECT 36.95 2.3225 37.015 2.3875 ;
      RECT 36.82 0.8975 36.885 0.9625 ;
      RECT 36.82 2.0375 36.885 2.1025 ;
      RECT 36.69 0.4675 36.755 0.5325 ;
      RECT 36.69 2.4675 36.755 2.5325 ;
      RECT 36.56 1.215 36.625 1.28 ;
      RECT 36.56 1.72 36.625 1.785 ;
      RECT 36.405 0.4675 36.47 0.5325 ;
      RECT 36.405 2.4675 36.47 2.5325 ;
      RECT 36.0125 0.5775 36.0775 0.6425 ;
      RECT 36.0125 2.3575 36.0775 2.4225 ;
      RECT 35.8575 0.5025 35.9225 0.5675 ;
      RECT 35.8575 2.4325 35.9225 2.4975 ;
      RECT 35.515 0.495 35.58 0.56 ;
      RECT 35.515 0.8975 35.58 0.9625 ;
      RECT 35.515 2.0375 35.58 2.1025 ;
      RECT 35.515 2.44 35.58 2.505 ;
      RECT 35.385 0.7025 35.45 0.7675 ;
      RECT 35.385 2.2325 35.45 2.2975 ;
      RECT 35.2775 0.495 35.3425 0.56 ;
      RECT 35.2775 2.44 35.3425 2.505 ;
      RECT 35.005 0.4975 35.07 0.5625 ;
      RECT 35.005 2.4375 35.07 2.5025 ;
      RECT 34.875 0.7025 34.94 0.7675 ;
      RECT 34.875 2.2325 34.94 2.2975 ;
      RECT 34.745 0.4975 34.81 0.5625 ;
      RECT 34.745 2.4375 34.81 2.5025 ;
      RECT 34.42 0.3175 34.485 0.3825 ;
      RECT 34.42 2.6175 34.485 2.6825 ;
      RECT 34.2925 0.6125 34.3575 0.6775 ;
      RECT 34.2925 2.3225 34.3575 2.3875 ;
      RECT 34.1625 0.8975 34.2275 0.9625 ;
      RECT 34.1625 2.0375 34.2275 2.1025 ;
      RECT 34.0325 0.4675 34.0975 0.5325 ;
      RECT 34.0325 2.4675 34.0975 2.5325 ;
      RECT 33.9025 1.215 33.9675 1.28 ;
      RECT 33.9025 1.72 33.9675 1.785 ;
      RECT 33.7475 0.4675 33.8125 0.5325 ;
      RECT 33.7475 2.4675 33.8125 2.5325 ;
      RECT 33.355 0.5775 33.42 0.6425 ;
      RECT 33.355 2.3575 33.42 2.4225 ;
      RECT 33.2 0.5025 33.265 0.5675 ;
      RECT 33.2 2.4325 33.265 2.4975 ;
      RECT 32.8575 0.495 32.9225 0.56 ;
      RECT 32.8575 0.8975 32.9225 0.9625 ;
      RECT 32.8575 2.0375 32.9225 2.1025 ;
      RECT 32.8575 2.44 32.9225 2.505 ;
      RECT 32.7275 0.7025 32.7925 0.7675 ;
      RECT 32.7275 2.2325 32.7925 2.2975 ;
      RECT 32.62 0.495 32.685 0.56 ;
      RECT 32.62 2.44 32.685 2.505 ;
      RECT 32.3475 0.4975 32.4125 0.5625 ;
      RECT 32.3475 2.4375 32.4125 2.5025 ;
      RECT 32.2175 0.7025 32.2825 0.7675 ;
      RECT 32.2175 2.2325 32.2825 2.2975 ;
      RECT 32.0875 0.4975 32.1525 0.5625 ;
      RECT 32.0875 2.4375 32.1525 2.5025 ;
      RECT 31.7625 0.3175 31.8275 0.3825 ;
      RECT 31.7625 2.6175 31.8275 2.6825 ;
      RECT 31.635 0.6125 31.7 0.6775 ;
      RECT 31.635 2.3225 31.7 2.3875 ;
      RECT 31.505 0.8975 31.57 0.9625 ;
      RECT 31.505 2.0375 31.57 2.1025 ;
      RECT 31.375 0.4675 31.44 0.5325 ;
      RECT 31.375 2.4675 31.44 2.5325 ;
      RECT 31.245 1.215 31.31 1.28 ;
      RECT 31.245 1.72 31.31 1.785 ;
      RECT 31.09 0.4675 31.155 0.5325 ;
      RECT 31.09 2.4675 31.155 2.5325 ;
      RECT 30.6975 0.5775 30.7625 0.6425 ;
      RECT 30.6975 2.3575 30.7625 2.4225 ;
      RECT 30.5425 0.5025 30.6075 0.5675 ;
      RECT 30.5425 2.4325 30.6075 2.4975 ;
      RECT 30.2 0.495 30.265 0.56 ;
      RECT 30.2 0.8975 30.265 0.9625 ;
      RECT 30.2 2.0375 30.265 2.1025 ;
      RECT 30.2 2.44 30.265 2.505 ;
      RECT 30.07 0.7025 30.135 0.7675 ;
      RECT 30.07 2.2325 30.135 2.2975 ;
      RECT 29.9625 0.495 30.0275 0.56 ;
      RECT 29.9625 2.44 30.0275 2.505 ;
      RECT 29.69 0.4975 29.755 0.5625 ;
      RECT 29.69 2.4375 29.755 2.5025 ;
      RECT 29.56 0.7025 29.625 0.7675 ;
      RECT 29.56 2.2325 29.625 2.2975 ;
      RECT 29.43 0.4975 29.495 0.5625 ;
      RECT 29.43 2.4375 29.495 2.5025 ;
      RECT 29.105 0.3175 29.17 0.3825 ;
      RECT 29.105 2.6175 29.17 2.6825 ;
      RECT 28.9775 0.6125 29.0425 0.6775 ;
      RECT 28.9775 2.3225 29.0425 2.3875 ;
      RECT 28.8475 0.8975 28.9125 0.9625 ;
      RECT 28.8475 2.0375 28.9125 2.1025 ;
      RECT 28.7175 0.4675 28.7825 0.5325 ;
      RECT 28.7175 2.4675 28.7825 2.5325 ;
      RECT 28.5875 1.215 28.6525 1.28 ;
      RECT 28.5875 1.72 28.6525 1.785 ;
      RECT 28.4325 0.4675 28.4975 0.5325 ;
      RECT 28.4325 2.4675 28.4975 2.5325 ;
      RECT 28.04 0.5775 28.105 0.6425 ;
      RECT 28.04 2.3575 28.105 2.4225 ;
      RECT 27.885 0.5025 27.95 0.5675 ;
      RECT 27.885 2.4325 27.95 2.4975 ;
      RECT 27.5425 0.495 27.6075 0.56 ;
      RECT 27.5425 0.8975 27.6075 0.9625 ;
      RECT 27.5425 2.0375 27.6075 2.1025 ;
      RECT 27.5425 2.44 27.6075 2.505 ;
      RECT 27.4125 0.7025 27.4775 0.7675 ;
      RECT 27.4125 2.2325 27.4775 2.2975 ;
      RECT 27.305 0.495 27.37 0.56 ;
      RECT 27.305 2.44 27.37 2.505 ;
      RECT 27.0325 0.4975 27.0975 0.5625 ;
      RECT 27.0325 2.4375 27.0975 2.5025 ;
      RECT 26.9025 0.7025 26.9675 0.7675 ;
      RECT 26.9025 2.2325 26.9675 2.2975 ;
      RECT 26.7725 0.4975 26.8375 0.5625 ;
      RECT 26.7725 2.4375 26.8375 2.5025 ;
      RECT 26.4475 0.3175 26.5125 0.3825 ;
      RECT 26.4475 2.6175 26.5125 2.6825 ;
      RECT 26.32 0.6125 26.385 0.6775 ;
      RECT 26.32 2.3225 26.385 2.3875 ;
      RECT 26.19 0.8975 26.255 0.9625 ;
      RECT 26.19 2.0375 26.255 2.1025 ;
      RECT 26.06 0.4675 26.125 0.5325 ;
      RECT 26.06 2.4675 26.125 2.5325 ;
      RECT 25.93 1.215 25.995 1.28 ;
      RECT 25.93 1.72 25.995 1.785 ;
      RECT 25.775 0.4675 25.84 0.5325 ;
      RECT 25.775 2.4675 25.84 2.5325 ;
      RECT 25.3825 0.5775 25.4475 0.6425 ;
      RECT 25.3825 2.3575 25.4475 2.4225 ;
      RECT 25.2275 0.5025 25.2925 0.5675 ;
      RECT 25.2275 2.4325 25.2925 2.4975 ;
      RECT 24.885 0.495 24.95 0.56 ;
      RECT 24.885 0.8975 24.95 0.9625 ;
      RECT 24.885 2.0375 24.95 2.1025 ;
      RECT 24.885 2.44 24.95 2.505 ;
      RECT 24.755 0.7025 24.82 0.7675 ;
      RECT 24.755 2.2325 24.82 2.2975 ;
      RECT 24.6475 0.495 24.7125 0.56 ;
      RECT 24.6475 2.44 24.7125 2.505 ;
      RECT 24.375 0.4975 24.44 0.5625 ;
      RECT 24.375 2.4375 24.44 2.5025 ;
      RECT 24.245 0.7025 24.31 0.7675 ;
      RECT 24.245 2.2325 24.31 2.2975 ;
      RECT 24.115 0.4975 24.18 0.5625 ;
      RECT 24.115 2.4375 24.18 2.5025 ;
      RECT 23.79 0.3175 23.855 0.3825 ;
      RECT 23.79 2.6175 23.855 2.6825 ;
      RECT 23.6625 0.6125 23.7275 0.6775 ;
      RECT 23.6625 2.3225 23.7275 2.3875 ;
      RECT 23.5325 0.8975 23.5975 0.9625 ;
      RECT 23.5325 2.0375 23.5975 2.1025 ;
      RECT 23.4025 0.4675 23.4675 0.5325 ;
      RECT 23.4025 2.4675 23.4675 2.5325 ;
      RECT 23.2725 1.215 23.3375 1.28 ;
      RECT 23.2725 1.72 23.3375 1.785 ;
      RECT 23.1175 0.4675 23.1825 0.5325 ;
      RECT 23.1175 2.4675 23.1825 2.5325 ;
      RECT 22.725 0.5775 22.79 0.6425 ;
      RECT 22.725 2.3575 22.79 2.4225 ;
      RECT 22.57 0.5025 22.635 0.5675 ;
      RECT 22.57 2.4325 22.635 2.4975 ;
      RECT 22.2275 0.495 22.2925 0.56 ;
      RECT 22.2275 0.8975 22.2925 0.9625 ;
      RECT 22.2275 2.0375 22.2925 2.1025 ;
      RECT 22.2275 2.44 22.2925 2.505 ;
      RECT 22.0975 0.7025 22.1625 0.7675 ;
      RECT 22.0975 2.2325 22.1625 2.2975 ;
      RECT 21.99 0.495 22.055 0.56 ;
      RECT 21.99 2.44 22.055 2.505 ;
      RECT 21.7175 0.4975 21.7825 0.5625 ;
      RECT 21.7175 2.4375 21.7825 2.5025 ;
      RECT 21.5875 0.7025 21.6525 0.7675 ;
      RECT 21.5875 2.2325 21.6525 2.2975 ;
      RECT 21.4575 0.4975 21.5225 0.5625 ;
      RECT 21.4575 2.4375 21.5225 2.5025 ;
      RECT 21.1325 0.3175 21.1975 0.3825 ;
      RECT 21.1325 2.6175 21.1975 2.6825 ;
      RECT 21.005 0.6125 21.07 0.6775 ;
      RECT 21.005 2.3225 21.07 2.3875 ;
      RECT 20.875 0.8975 20.94 0.9625 ;
      RECT 20.875 2.0375 20.94 2.1025 ;
      RECT 20.745 0.4675 20.81 0.5325 ;
      RECT 20.745 2.4675 20.81 2.5325 ;
      RECT 20.615 1.215 20.68 1.28 ;
      RECT 20.615 1.72 20.68 1.785 ;
      RECT 20.46 0.4675 20.525 0.5325 ;
      RECT 20.46 2.4675 20.525 2.5325 ;
      RECT 20.0675 0.5775 20.1325 0.6425 ;
      RECT 20.0675 2.3575 20.1325 2.4225 ;
      RECT 19.9125 0.5025 19.9775 0.5675 ;
      RECT 19.9125 2.4325 19.9775 2.4975 ;
      RECT 19.57 0.495 19.635 0.56 ;
      RECT 19.57 0.8975 19.635 0.9625 ;
      RECT 19.57 2.0375 19.635 2.1025 ;
      RECT 19.57 2.44 19.635 2.505 ;
      RECT 19.44 0.7025 19.505 0.7675 ;
      RECT 19.44 2.2325 19.505 2.2975 ;
      RECT 19.3325 0.495 19.3975 0.56 ;
      RECT 19.3325 2.44 19.3975 2.505 ;
      RECT 19.06 0.4975 19.125 0.5625 ;
      RECT 19.06 2.4375 19.125 2.5025 ;
      RECT 18.93 0.7025 18.995 0.7675 ;
      RECT 18.93 2.2325 18.995 2.2975 ;
      RECT 18.8 0.4975 18.865 0.5625 ;
      RECT 18.8 2.4375 18.865 2.5025 ;
      RECT 18.475 0.3175 18.54 0.3825 ;
      RECT 18.475 2.6175 18.54 2.6825 ;
      RECT 18.3475 0.6125 18.4125 0.6775 ;
      RECT 18.3475 2.3225 18.4125 2.3875 ;
      RECT 18.2175 0.8975 18.2825 0.9625 ;
      RECT 18.2175 2.0375 18.2825 2.1025 ;
      RECT 18.0875 0.4675 18.1525 0.5325 ;
      RECT 18.0875 2.4675 18.1525 2.5325 ;
      RECT 17.9575 1.215 18.0225 1.28 ;
      RECT 17.9575 1.72 18.0225 1.785 ;
      RECT 17.8025 0.4675 17.8675 0.5325 ;
      RECT 17.8025 2.4675 17.8675 2.5325 ;
      RECT 17.41 0.5775 17.475 0.6425 ;
      RECT 17.41 2.3575 17.475 2.4225 ;
      RECT 17.255 0.5025 17.32 0.5675 ;
      RECT 17.255 2.4325 17.32 2.4975 ;
      RECT 16.9125 0.495 16.9775 0.56 ;
      RECT 16.9125 0.8975 16.9775 0.9625 ;
      RECT 16.9125 2.0375 16.9775 2.1025 ;
      RECT 16.9125 2.44 16.9775 2.505 ;
      RECT 16.7825 0.7025 16.8475 0.7675 ;
      RECT 16.7825 2.2325 16.8475 2.2975 ;
      RECT 16.675 0.495 16.74 0.56 ;
      RECT 16.675 2.44 16.74 2.505 ;
      RECT 16.4025 0.4975 16.4675 0.5625 ;
      RECT 16.4025 2.4375 16.4675 2.5025 ;
      RECT 16.2725 0.7025 16.3375 0.7675 ;
      RECT 16.2725 2.2325 16.3375 2.2975 ;
      RECT 16.1425 0.4975 16.2075 0.5625 ;
      RECT 16.1425 2.4375 16.2075 2.5025 ;
      RECT 15.8175 0.3175 15.8825 0.3825 ;
      RECT 15.8175 2.6175 15.8825 2.6825 ;
      RECT 15.69 0.6125 15.755 0.6775 ;
      RECT 15.69 2.3225 15.755 2.3875 ;
      RECT 15.56 0.8975 15.625 0.9625 ;
      RECT 15.56 2.0375 15.625 2.1025 ;
      RECT 15.43 0.4675 15.495 0.5325 ;
      RECT 15.43 2.4675 15.495 2.5325 ;
      RECT 15.3 1.215 15.365 1.28 ;
      RECT 15.3 1.72 15.365 1.785 ;
      RECT 15.145 0.4675 15.21 0.5325 ;
      RECT 15.145 2.4675 15.21 2.5325 ;
      RECT 14.7525 0.5775 14.8175 0.6425 ;
      RECT 14.7525 2.3575 14.8175 2.4225 ;
      RECT 14.5975 0.5025 14.6625 0.5675 ;
      RECT 14.5975 2.4325 14.6625 2.4975 ;
      RECT 14.255 0.495 14.32 0.56 ;
      RECT 14.255 0.8975 14.32 0.9625 ;
      RECT 14.255 2.0375 14.32 2.1025 ;
      RECT 14.255 2.44 14.32 2.505 ;
      RECT 14.125 0.7025 14.19 0.7675 ;
      RECT 14.125 2.2325 14.19 2.2975 ;
      RECT 14.0175 0.495 14.0825 0.56 ;
      RECT 14.0175 2.44 14.0825 2.505 ;
      RECT 13.745 0.4975 13.81 0.5625 ;
      RECT 13.745 2.4375 13.81 2.5025 ;
      RECT 13.615 0.7025 13.68 0.7675 ;
      RECT 13.615 2.2325 13.68 2.2975 ;
      RECT 13.485 0.4975 13.55 0.5625 ;
      RECT 13.485 2.4375 13.55 2.5025 ;
      RECT 13.16 0.3175 13.225 0.3825 ;
      RECT 13.16 2.6175 13.225 2.6825 ;
      RECT 13.0325 0.6125 13.0975 0.6775 ;
      RECT 13.0325 2.3225 13.0975 2.3875 ;
      RECT 12.9025 0.8975 12.9675 0.9625 ;
      RECT 12.9025 2.0375 12.9675 2.1025 ;
      RECT 12.7725 0.4675 12.8375 0.5325 ;
      RECT 12.7725 2.4675 12.8375 2.5325 ;
      RECT 12.6425 1.215 12.7075 1.28 ;
      RECT 12.6425 1.72 12.7075 1.785 ;
      RECT 12.4875 0.4675 12.5525 0.5325 ;
      RECT 12.4875 2.4675 12.5525 2.5325 ;
      RECT 12.095 0.5775 12.16 0.6425 ;
      RECT 12.095 2.3575 12.16 2.4225 ;
      RECT 11.94 0.5025 12.005 0.5675 ;
      RECT 11.94 2.4325 12.005 2.4975 ;
      RECT 11.5975 0.495 11.6625 0.56 ;
      RECT 11.5975 0.8975 11.6625 0.9625 ;
      RECT 11.5975 2.0375 11.6625 2.1025 ;
      RECT 11.5975 2.44 11.6625 2.505 ;
      RECT 11.4675 0.7025 11.5325 0.7675 ;
      RECT 11.4675 2.2325 11.5325 2.2975 ;
      RECT 11.36 0.495 11.425 0.56 ;
      RECT 11.36 2.44 11.425 2.505 ;
      RECT 11.0875 0.4975 11.1525 0.5625 ;
      RECT 11.0875 2.4375 11.1525 2.5025 ;
      RECT 10.9575 0.7025 11.0225 0.7675 ;
      RECT 10.9575 2.2325 11.0225 2.2975 ;
      RECT 10.8275 0.4975 10.8925 0.5625 ;
      RECT 10.8275 2.4375 10.8925 2.5025 ;
      RECT 10.5025 0.3175 10.5675 0.3825 ;
      RECT 10.5025 2.6175 10.5675 2.6825 ;
      RECT 10.375 0.6125 10.44 0.6775 ;
      RECT 10.375 2.3225 10.44 2.3875 ;
      RECT 10.245 0.8975 10.31 0.9625 ;
      RECT 10.245 2.0375 10.31 2.1025 ;
      RECT 10.115 0.4675 10.18 0.5325 ;
      RECT 10.115 2.4675 10.18 2.5325 ;
      RECT 9.985 1.215 10.05 1.28 ;
      RECT 9.985 1.72 10.05 1.785 ;
      RECT 9.83 0.4675 9.895 0.5325 ;
      RECT 9.83 2.4675 9.895 2.5325 ;
      RECT 9.4375 0.5775 9.5025 0.6425 ;
      RECT 9.4375 2.3575 9.5025 2.4225 ;
      RECT 9.2825 0.5025 9.3475 0.5675 ;
      RECT 9.2825 2.4325 9.3475 2.4975 ;
      RECT 8.94 0.495 9.005 0.56 ;
      RECT 8.94 0.8975 9.005 0.9625 ;
      RECT 8.94 2.0375 9.005 2.1025 ;
      RECT 8.94 2.44 9.005 2.505 ;
      RECT 8.81 0.7025 8.875 0.7675 ;
      RECT 8.81 2.2325 8.875 2.2975 ;
      RECT 8.7025 0.495 8.7675 0.56 ;
      RECT 8.7025 2.44 8.7675 2.505 ;
      RECT 8.43 0.4975 8.495 0.5625 ;
      RECT 8.43 2.4375 8.495 2.5025 ;
      RECT 8.3 0.7025 8.365 0.7675 ;
      RECT 8.3 2.2325 8.365 2.2975 ;
      RECT 8.17 0.4975 8.235 0.5625 ;
      RECT 8.17 2.4375 8.235 2.5025 ;
      RECT 7.845 0.3175 7.91 0.3825 ;
      RECT 7.845 2.6175 7.91 2.6825 ;
      RECT 7.7175 0.6125 7.7825 0.6775 ;
      RECT 7.7175 2.3225 7.7825 2.3875 ;
      RECT 7.5875 0.8975 7.6525 0.9625 ;
      RECT 7.5875 2.0375 7.6525 2.1025 ;
      RECT 7.4575 0.4675 7.5225 0.5325 ;
      RECT 7.4575 2.4675 7.5225 2.5325 ;
      RECT 7.3275 1.215 7.3925 1.28 ;
      RECT 7.3275 1.72 7.3925 1.785 ;
      RECT 7.1725 0.4675 7.2375 0.5325 ;
      RECT 7.1725 2.4675 7.2375 2.5325 ;
      RECT 6.78 0.5775 6.845 0.6425 ;
      RECT 6.78 2.3575 6.845 2.4225 ;
      RECT 6.625 0.5025 6.69 0.5675 ;
      RECT 6.625 2.4325 6.69 2.4975 ;
      RECT 6.2825 0.495 6.3475 0.56 ;
      RECT 6.2825 0.8975 6.3475 0.9625 ;
      RECT 6.2825 2.0375 6.3475 2.1025 ;
      RECT 6.2825 2.44 6.3475 2.505 ;
      RECT 6.1525 0.7025 6.2175 0.7675 ;
      RECT 6.1525 2.2325 6.2175 2.2975 ;
      RECT 6.045 0.495 6.11 0.56 ;
      RECT 6.045 2.44 6.11 2.505 ;
      RECT 5.7725 0.4975 5.8375 0.5625 ;
      RECT 5.7725 2.4375 5.8375 2.5025 ;
      RECT 5.6425 0.7025 5.7075 0.7675 ;
      RECT 5.6425 2.2325 5.7075 2.2975 ;
      RECT 5.5125 0.4975 5.5775 0.5625 ;
      RECT 5.5125 2.4375 5.5775 2.5025 ;
      RECT 5.1875 0.3175 5.2525 0.3825 ;
      RECT 5.1875 2.6175 5.2525 2.6825 ;
      RECT 5.06 0.6125 5.125 0.6775 ;
      RECT 5.06 2.3225 5.125 2.3875 ;
      RECT 4.93 0.8975 4.995 0.9625 ;
      RECT 4.93 2.0375 4.995 2.1025 ;
      RECT 4.8 0.4675 4.865 0.5325 ;
      RECT 4.8 2.4675 4.865 2.5325 ;
      RECT 4.67 1.215 4.735 1.28 ;
      RECT 4.67 1.72 4.735 1.785 ;
      RECT 4.515 0.4675 4.58 0.5325 ;
      RECT 4.515 2.4675 4.58 2.5325 ;
      RECT 4.1225 0.5775 4.1875 0.6425 ;
      RECT 4.1225 2.3575 4.1875 2.4225 ;
      RECT 3.9675 0.5025 4.0325 0.5675 ;
      RECT 3.9675 2.4325 4.0325 2.4975 ;
      RECT 3.625 0.495 3.69 0.56 ;
      RECT 3.625 0.8975 3.69 0.9625 ;
      RECT 3.625 2.0375 3.69 2.1025 ;
      RECT 3.625 2.44 3.69 2.505 ;
      RECT 3.495 0.7025 3.56 0.7675 ;
      RECT 3.495 2.2325 3.56 2.2975 ;
      RECT 3.3875 0.495 3.4525 0.56 ;
      RECT 3.3875 2.44 3.4525 2.505 ;
      RECT 3.115 0.4975 3.18 0.5625 ;
      RECT 3.115 2.4375 3.18 2.5025 ;
      RECT 2.985 0.7025 3.05 0.7675 ;
      RECT 2.985 2.2325 3.05 2.2975 ;
      RECT 2.855 0.4975 2.92 0.5625 ;
      RECT 2.855 2.4375 2.92 2.5025 ;
      RECT 2.53 0.3175 2.595 0.3825 ;
      RECT 2.53 2.6175 2.595 2.6825 ;
      RECT 2.4025 0.6125 2.4675 0.6775 ;
      RECT 2.4025 2.3225 2.4675 2.3875 ;
      RECT 2.2725 0.8975 2.3375 0.9625 ;
      RECT 2.2725 2.0375 2.3375 2.1025 ;
      RECT 2.1425 0.4675 2.2075 0.5325 ;
      RECT 2.1425 2.4675 2.2075 2.5325 ;
      RECT 2.0125 1.215 2.0775 1.28 ;
      RECT 2.0125 1.72 2.0775 1.785 ;
      RECT 1.8575 0.4675 1.9225 0.5325 ;
      RECT 1.8575 2.4675 1.9225 2.5325 ;
      RECT 1.465 0.5775 1.53 0.6425 ;
      RECT 1.465 2.3575 1.53 2.4225 ;
      RECT 1.31 0.5025 1.375 0.5675 ;
      RECT 1.31 2.4325 1.375 2.4975 ;
      RECT 0.9675 0.495 1.0325 0.56 ;
      RECT 0.9675 0.8975 1.0325 0.9625 ;
      RECT 0.9675 2.0375 1.0325 2.1025 ;
      RECT 0.9675 2.44 1.0325 2.505 ;
      RECT 0.8375 0.7025 0.9025 0.7675 ;
      RECT 0.8375 2.2325 0.9025 2.2975 ;
      RECT 0.73 0.495 0.795 0.56 ;
      RECT 0.73 2.44 0.795 2.505 ;
      RECT 0.4575 0.4975 0.5225 0.5625 ;
      RECT 0.4575 2.4375 0.5225 2.5025 ;
      RECT 0.3275 0.7025 0.3925 0.7675 ;
      RECT 0.3275 2.2325 0.3925 2.2975 ;
      RECT 0.1975 0.4975 0.2625 0.5625 ;
      RECT 0.1975 2.4375 0.2625 2.5025 ;
    LAYER via2 ;
      RECT 42.3875 0.315 42.4575 0.385 ;
      RECT 42.3875 2.1 42.4575 2.17 ;
      RECT 42.3875 2.6175 42.4575 2.6875 ;
      RECT 42.13 0.895 42.2 0.965 ;
      RECT 42.13 2.035 42.2 2.105 ;
      RECT 42.07 1.2125 42.14 1.2825 ;
      RECT 42.07 1.72 42.14 1.79 ;
      RECT 41.17 0.495 41.24 0.565 ;
      RECT 41.17 2.435 41.24 2.505 ;
      RECT 40.825 0.895 40.895 0.965 ;
      RECT 40.825 2.035 40.895 2.105 ;
      RECT 40.315 0.495 40.385 0.565 ;
      RECT 40.315 2.435 40.385 2.505 ;
      RECT 39.4725 0.895 39.5425 0.965 ;
      RECT 39.4725 2.035 39.5425 2.105 ;
      RECT 38.5125 0.495 38.5825 0.565 ;
      RECT 38.5125 2.435 38.5825 2.505 ;
      RECT 38.1675 0.895 38.2375 0.965 ;
      RECT 38.1675 2.035 38.2375 2.105 ;
      RECT 37.6575 0.495 37.7275 0.565 ;
      RECT 37.6575 2.435 37.7275 2.505 ;
      RECT 36.815 0.895 36.885 0.965 ;
      RECT 36.815 2.035 36.885 2.105 ;
      RECT 35.855 0.495 35.925 0.565 ;
      RECT 35.855 2.435 35.925 2.505 ;
      RECT 35.51 0.895 35.58 0.965 ;
      RECT 35.51 2.035 35.58 2.105 ;
      RECT 35 0.495 35.07 0.565 ;
      RECT 35 2.435 35.07 2.505 ;
      RECT 34.1575 0.895 34.2275 0.965 ;
      RECT 34.1575 2.035 34.2275 2.105 ;
      RECT 33.1975 0.495 33.2675 0.565 ;
      RECT 33.1975 2.435 33.2675 2.505 ;
      RECT 32.8525 0.895 32.9225 0.965 ;
      RECT 32.8525 2.035 32.9225 2.105 ;
      RECT 32.3425 0.495 32.4125 0.565 ;
      RECT 32.3425 2.435 32.4125 2.505 ;
      RECT 31.5 0.895 31.57 0.965 ;
      RECT 31.5 2.035 31.57 2.105 ;
      RECT 30.54 0.495 30.61 0.565 ;
      RECT 30.54 2.435 30.61 2.505 ;
      RECT 30.195 0.895 30.265 0.965 ;
      RECT 30.195 2.035 30.265 2.105 ;
      RECT 29.685 0.495 29.755 0.565 ;
      RECT 29.685 2.435 29.755 2.505 ;
      RECT 28.8425 0.895 28.9125 0.965 ;
      RECT 28.8425 2.035 28.9125 2.105 ;
      RECT 27.8825 0.495 27.9525 0.565 ;
      RECT 27.8825 2.435 27.9525 2.505 ;
      RECT 27.5375 0.895 27.6075 0.965 ;
      RECT 27.5375 2.035 27.6075 2.105 ;
      RECT 27.0275 0.495 27.0975 0.565 ;
      RECT 27.0275 2.435 27.0975 2.505 ;
      RECT 26.185 0.895 26.255 0.965 ;
      RECT 26.185 2.035 26.255 2.105 ;
      RECT 25.225 0.495 25.295 0.565 ;
      RECT 25.225 2.435 25.295 2.505 ;
      RECT 24.88 0.895 24.95 0.965 ;
      RECT 24.88 2.035 24.95 2.105 ;
      RECT 24.37 0.495 24.44 0.565 ;
      RECT 24.37 2.435 24.44 2.505 ;
      RECT 23.5275 0.895 23.5975 0.965 ;
      RECT 23.5275 2.035 23.5975 2.105 ;
      RECT 22.5675 0.495 22.6375 0.565 ;
      RECT 22.5675 2.435 22.6375 2.505 ;
      RECT 22.2225 0.895 22.2925 0.965 ;
      RECT 22.2225 2.035 22.2925 2.105 ;
      RECT 21.7125 0.495 21.7825 0.565 ;
      RECT 21.7125 2.435 21.7825 2.505 ;
      RECT 20.87 0.895 20.94 0.965 ;
      RECT 20.87 2.035 20.94 2.105 ;
      RECT 19.91 0.495 19.98 0.565 ;
      RECT 19.91 2.435 19.98 2.505 ;
      RECT 19.565 0.895 19.635 0.965 ;
      RECT 19.565 2.035 19.635 2.105 ;
      RECT 19.055 0.495 19.125 0.565 ;
      RECT 19.055 2.435 19.125 2.505 ;
      RECT 18.2125 0.895 18.2825 0.965 ;
      RECT 18.2125 2.035 18.2825 2.105 ;
      RECT 17.2525 0.495 17.3225 0.565 ;
      RECT 17.2525 2.435 17.3225 2.505 ;
      RECT 16.9075 0.895 16.9775 0.965 ;
      RECT 16.9075 2.035 16.9775 2.105 ;
      RECT 16.3975 0.495 16.4675 0.565 ;
      RECT 16.3975 2.435 16.4675 2.505 ;
      RECT 15.555 0.895 15.625 0.965 ;
      RECT 15.555 2.035 15.625 2.105 ;
      RECT 14.595 0.495 14.665 0.565 ;
      RECT 14.595 2.435 14.665 2.505 ;
      RECT 14.25 0.895 14.32 0.965 ;
      RECT 14.25 2.035 14.32 2.105 ;
      RECT 13.74 0.495 13.81 0.565 ;
      RECT 13.74 2.435 13.81 2.505 ;
      RECT 12.8975 0.895 12.9675 0.965 ;
      RECT 12.8975 2.035 12.9675 2.105 ;
      RECT 11.9375 0.495 12.0075 0.565 ;
      RECT 11.9375 2.435 12.0075 2.505 ;
      RECT 11.5925 0.895 11.6625 0.965 ;
      RECT 11.5925 2.035 11.6625 2.105 ;
      RECT 11.0825 0.495 11.1525 0.565 ;
      RECT 11.0825 2.435 11.1525 2.505 ;
      RECT 10.24 0.895 10.31 0.965 ;
      RECT 10.24 2.035 10.31 2.105 ;
      RECT 9.28 0.495 9.35 0.565 ;
      RECT 9.28 2.435 9.35 2.505 ;
      RECT 8.935 0.895 9.005 0.965 ;
      RECT 8.935 2.035 9.005 2.105 ;
      RECT 8.425 0.495 8.495 0.565 ;
      RECT 8.425 2.435 8.495 2.505 ;
      RECT 7.5825 0.895 7.6525 0.965 ;
      RECT 7.5825 2.035 7.6525 2.105 ;
      RECT 6.6225 0.495 6.6925 0.565 ;
      RECT 6.6225 2.435 6.6925 2.505 ;
      RECT 6.2775 0.895 6.3475 0.965 ;
      RECT 6.2775 2.035 6.3475 2.105 ;
      RECT 5.7675 0.495 5.8375 0.565 ;
      RECT 5.7675 2.435 5.8375 2.505 ;
      RECT 4.925 0.895 4.995 0.965 ;
      RECT 4.925 2.035 4.995 2.105 ;
      RECT 3.965 0.495 4.035 0.565 ;
      RECT 3.965 2.435 4.035 2.505 ;
      RECT 3.62 0.895 3.69 0.965 ;
      RECT 3.62 2.035 3.69 2.105 ;
      RECT 3.11 0.495 3.18 0.565 ;
      RECT 3.11 2.435 3.18 2.505 ;
      RECT 2.2675 0.895 2.3375 0.965 ;
      RECT 2.2675 2.035 2.3375 2.105 ;
      RECT 1.3075 0.495 1.3775 0.565 ;
      RECT 1.3075 2.435 1.3775 2.505 ;
      RECT 0.9625 0.895 1.0325 0.965 ;
      RECT 0.9625 2.035 1.0325 2.105 ;
      RECT 0.4525 0.495 0.5225 0.565 ;
      RECT 0.4525 2.435 0.5225 2.505 ;
    LAYER via3 ;
      RECT 42.13 0.895 42.2 0.965 ;
      RECT 42.13 2.035 42.2 2.105 ;
      RECT 41.17 0.495 41.24 0.565 ;
      RECT 41.17 2.435 41.24 2.505 ;
      RECT 40.825 0.895 40.895 0.965 ;
      RECT 40.825 2.035 40.895 2.105 ;
      RECT 40.315 0.495 40.385 0.565 ;
      RECT 40.315 2.435 40.385 2.505 ;
      RECT 39.4725 0.895 39.5425 0.965 ;
      RECT 39.4725 2.035 39.5425 2.105 ;
      RECT 38.5125 0.495 38.5825 0.565 ;
      RECT 38.5125 2.435 38.5825 2.505 ;
      RECT 38.1675 0.895 38.2375 0.965 ;
      RECT 38.1675 2.035 38.2375 2.105 ;
      RECT 37.6575 0.495 37.7275 0.565 ;
      RECT 37.6575 2.435 37.7275 2.505 ;
      RECT 36.815 0.895 36.885 0.965 ;
      RECT 36.815 2.035 36.885 2.105 ;
      RECT 35.855 0.495 35.925 0.565 ;
      RECT 35.855 2.435 35.925 2.505 ;
      RECT 35.51 0.895 35.58 0.965 ;
      RECT 35.51 2.035 35.58 2.105 ;
      RECT 35 0.495 35.07 0.565 ;
      RECT 35 2.435 35.07 2.505 ;
      RECT 34.1575 0.895 34.2275 0.965 ;
      RECT 34.1575 2.035 34.2275 2.105 ;
      RECT 33.1975 0.495 33.2675 0.565 ;
      RECT 33.1975 2.435 33.2675 2.505 ;
      RECT 32.8525 0.895 32.9225 0.965 ;
      RECT 32.8525 2.035 32.9225 2.105 ;
      RECT 32.3425 0.495 32.4125 0.565 ;
      RECT 32.3425 2.435 32.4125 2.505 ;
      RECT 31.5 0.895 31.57 0.965 ;
      RECT 31.5 2.035 31.57 2.105 ;
      RECT 30.54 0.495 30.61 0.565 ;
      RECT 30.54 2.435 30.61 2.505 ;
      RECT 30.195 0.895 30.265 0.965 ;
      RECT 30.195 2.035 30.265 2.105 ;
      RECT 29.685 0.495 29.755 0.565 ;
      RECT 29.685 2.435 29.755 2.505 ;
      RECT 28.8425 0.895 28.9125 0.965 ;
      RECT 28.8425 2.035 28.9125 2.105 ;
      RECT 27.8825 0.495 27.9525 0.565 ;
      RECT 27.8825 2.435 27.9525 2.505 ;
      RECT 27.5375 0.895 27.6075 0.965 ;
      RECT 27.5375 2.035 27.6075 2.105 ;
      RECT 27.0275 0.495 27.0975 0.565 ;
      RECT 27.0275 2.435 27.0975 2.505 ;
      RECT 26.185 0.895 26.255 0.965 ;
      RECT 26.185 2.035 26.255 2.105 ;
      RECT 25.225 0.495 25.295 0.565 ;
      RECT 25.225 2.435 25.295 2.505 ;
      RECT 24.88 0.895 24.95 0.965 ;
      RECT 24.88 2.035 24.95 2.105 ;
      RECT 24.37 0.495 24.44 0.565 ;
      RECT 24.37 2.435 24.44 2.505 ;
      RECT 23.5275 0.895 23.5975 0.965 ;
      RECT 23.5275 2.035 23.5975 2.105 ;
      RECT 22.5675 0.495 22.6375 0.565 ;
      RECT 22.5675 2.435 22.6375 2.505 ;
      RECT 22.2225 0.895 22.2925 0.965 ;
      RECT 22.2225 2.035 22.2925 2.105 ;
      RECT 21.7125 0.495 21.7825 0.565 ;
      RECT 21.7125 2.435 21.7825 2.505 ;
      RECT 20.87 0.895 20.94 0.965 ;
      RECT 20.87 2.035 20.94 2.105 ;
      RECT 19.91 0.495 19.98 0.565 ;
      RECT 19.91 2.435 19.98 2.505 ;
      RECT 19.565 0.895 19.635 0.965 ;
      RECT 19.565 2.035 19.635 2.105 ;
      RECT 19.055 0.495 19.125 0.565 ;
      RECT 19.055 2.435 19.125 2.505 ;
      RECT 18.2125 0.895 18.2825 0.965 ;
      RECT 18.2125 2.035 18.2825 2.105 ;
      RECT 17.2525 0.495 17.3225 0.565 ;
      RECT 17.2525 2.435 17.3225 2.505 ;
      RECT 16.9075 0.895 16.9775 0.965 ;
      RECT 16.9075 2.035 16.9775 2.105 ;
      RECT 16.3975 0.495 16.4675 0.565 ;
      RECT 16.3975 2.435 16.4675 2.505 ;
      RECT 15.555 0.895 15.625 0.965 ;
      RECT 15.555 2.035 15.625 2.105 ;
      RECT 14.595 0.495 14.665 0.565 ;
      RECT 14.595 2.435 14.665 2.505 ;
      RECT 14.25 0.895 14.32 0.965 ;
      RECT 14.25 2.035 14.32 2.105 ;
      RECT 13.74 0.495 13.81 0.565 ;
      RECT 13.74 2.435 13.81 2.505 ;
      RECT 12.8975 0.895 12.9675 0.965 ;
      RECT 12.8975 2.035 12.9675 2.105 ;
      RECT 11.9375 0.495 12.0075 0.565 ;
      RECT 11.9375 2.435 12.0075 2.505 ;
      RECT 11.5925 0.895 11.6625 0.965 ;
      RECT 11.5925 2.035 11.6625 2.105 ;
      RECT 11.0825 0.495 11.1525 0.565 ;
      RECT 11.0825 2.435 11.1525 2.505 ;
      RECT 10.24 0.895 10.31 0.965 ;
      RECT 10.24 2.035 10.31 2.105 ;
      RECT 9.28 0.495 9.35 0.565 ;
      RECT 9.28 2.435 9.35 2.505 ;
      RECT 8.935 0.895 9.005 0.965 ;
      RECT 8.935 2.035 9.005 2.105 ;
      RECT 8.425 0.495 8.495 0.565 ;
      RECT 8.425 2.435 8.495 2.505 ;
      RECT 7.5825 0.895 7.6525 0.965 ;
      RECT 7.5825 2.035 7.6525 2.105 ;
      RECT 6.6225 0.495 6.6925 0.565 ;
      RECT 6.6225 2.435 6.6925 2.505 ;
      RECT 6.2775 0.895 6.3475 0.965 ;
      RECT 6.2775 2.035 6.3475 2.105 ;
      RECT 5.7675 0.495 5.8375 0.565 ;
      RECT 5.7675 2.435 5.8375 2.505 ;
      RECT 4.925 0.895 4.995 0.965 ;
      RECT 4.925 2.035 4.995 2.105 ;
      RECT 3.965 0.495 4.035 0.565 ;
      RECT 3.965 2.435 4.035 2.505 ;
      RECT 3.62 0.895 3.69 0.965 ;
      RECT 3.62 2.035 3.69 2.105 ;
      RECT 3.11 0.495 3.18 0.565 ;
      RECT 3.11 2.435 3.18 2.505 ;
      RECT 2.2675 0.895 2.3375 0.965 ;
      RECT 2.2675 2.035 2.3375 2.105 ;
      RECT 1.3075 0.495 1.3775 0.565 ;
      RECT 1.3075 2.435 1.3775 2.505 ;
      RECT 0.9625 0.895 1.0325 0.965 ;
      RECT 0.9625 2.035 1.0325 2.105 ;
      RECT 0.4525 0.495 0.5225 0.565 ;
      RECT 0.4525 2.435 0.5225 2.505 ;
  END
END regfile

END LIBRARY
